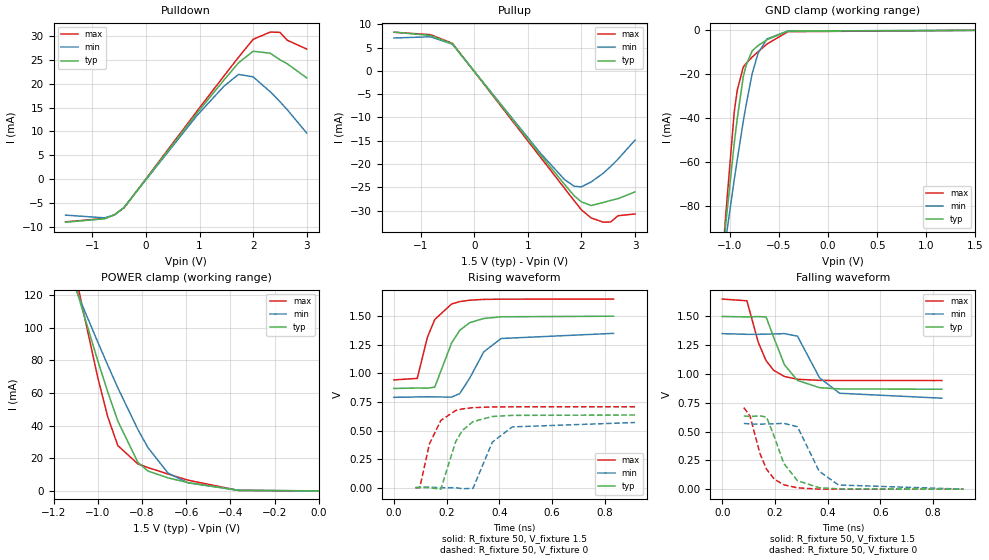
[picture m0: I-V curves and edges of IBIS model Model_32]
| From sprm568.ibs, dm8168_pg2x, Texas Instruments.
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| Model based on original model for BSHTLTCSCDVGPBFZ
|   Sub model FASTEST_6MA_10PER_1P5
[model]   Model_32
|[Description]  [1.5V-3-STATE-X-FASTEST:6MA, IND, 10%]
|   Fastest slew rate (SR[1:0] = "00"), 1.33 * RExt = 0.750 * Iout
|   (I[2:0] = "001"), 6mA nominal with Rext = 50R, ,Industrial
|   temperature range (-40C to 125C, 25C nominal),10% power supply
|   tolerance
|[Input Load]
|[Output Drive] FASTEST:6MA
|Voltage   1.5V
|Mode   3-STATE
Model_type   3-state
Polarity   Non-Inverting
Enable   Active-Low
Cref =  15.0000pF
Rref =  100.0000M
Vref =  0V
Vmeas =  0.75
C_comp   1.5249p   1.4275p   1.6205p
[Model Spec]
[Temperature Range]   25   125   -40
[Voltage Range]   1.5   1.35   1.65
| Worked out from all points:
|   slope of the pulldown table from 0 to 0.225 V, typ, clamps not added: 67.5 ohm
|   slope of the pullup table from 0 to 0.225 V, typ, clamps not added: 67.5 ohm
|   GND clamp passes 1 mA (typ) near -0.47 V on its own axis
|   POWER clamp passes 1 mA (typ) near -0.42 V on its own axis
|   rising waveform, R_fixture 50, V_fixture 1.5: 20-80 % time 68.5ps typ, 87.8ps min, 61.8ps max; typ from 0.868 V to 1.5 V
|   rising waveform, R_fixture 50, V_fixture 0: 20-80 % time 65.3ps typ, 72.3ps min, 59.7ps max; typ from 0 V to 0.636 V
|   falling waveform, R_fixture 50, V_fixture 1.5: 20-80 % time 73.3ps typ, 86.3ps min, 66.2ps max; typ from 1.5 V to 0.867 V
|   falling waveform, R_fixture 50, V_fixture 0: 20-80 % time 69.6ps typ, 78.8ps min, 62.5ps max; typ from 0.636 V to 0 V
[POWER_clamp]
-1.5V     321.6mA    260.6mA    415.8mA
-1.091V   121.1mA    120.8mA    126.6mA
-1.076V   114.1mA    115.8mA    116.8mA
-1V       79.88mA    91.3mA     69.56mA
-954.5mV  60.58mA    77.05mA    45.34mA
-909.1mV  42.84mA    63.2mA     27.8mA
-818.2mV  17.47mA    37.6mA     16.51mA
-772.7mV  12.19mA    26.53mA    14.33mA
-681.8mV  7.985mA    10.89mA    10.33mA
-590.9mV  5.092mA    4.952mA    6.596mA
-363.6mV  298.9uA    465.6uA    298.1uA
0V        1.518nA    23.05nA    396.5pA
[Pulldown]
-1.5V     -9.02mA    -7.54mA    -8.95mA
-772.7mV  -8.299mA   -8.105mA   -8.235mA
-590.9mV  -7.513mA   -7.517mA   -7.478mA
-409.1mV  -5.951mA   -5.915mA   -6.017mA
954.5mV   13.88mA    13.38mA    14.3mA
1.455V    20.79mA    19.48mA    21.63mA
1.727V    24.39mA    21.97mA    25.55mA
2V        26.82mA    21.46mA    29.32mA
2.318V    26.42mA    18.34mA    30.84mA
2.5V      25.05mA    16.26mA    30.79mA
2.636V    24.2mA     14.57mA    29.14mA
3V        21.24mA    9.67mA     27.28mA
[Pullup]
-1.5V     8.32mA     7.05mA     8.28mA
-818.2mV  7.591mA    7.315mA    7.769mA
-409.1mV  5.809mA    5.727mA    5.921mA
1.227V    -17.92mA   -17.56mA   -18.4mA
1.682V    -24.33mA   -23.3mA    -25.16mA
1.864V    -26.79mA   -24.75mA   -27.86mA
2V        -28.11mA   -24.88mA   -29.82mA
2.182V    -28.88mA   -23.81mA   -31.56mA
2.409V    -28.22mA   -21.94mA   -32.46mA
2.545V    -27.79mA   -20.51mA   -32.42mA
2.682V    -27.41mA   -18.93mA   -31.08mA
3V        -25.95mA   -14.85mA   -30.69mA
[GND_clamp]
-1.5V     -310mA     -250.5mA   -402.4mA
-1.076V   -103.5mA   -106.1mA   -105.2mA
-1.045V   -89.74mA   -96.32mA   -85.93mA
-954.5mV  -51.19mA   -67.85mA   -36.85mA
-924.2mV  -40.06mA   -58.84mA   -27.27mA
-863.6mV  -21.23mA   -41.55mA   -16.73mA
-833.3mV  -15.79mA   -33.74mA   -15.03mA
-772.7mV  -9.342mA   -19.74mA   -12.19mA
-712.1mV  -6.927mA   -10.35mA   -9.702mA
-621.2mV  -4.26mA    -3.894mA   -6.224mA
-409.1mV  -336.9uA   -288.9uA   -618.6uA
1.5V      1.518nA    2.298uA    269.6pA
[Ramp]
dV/dt_f   0.50884/0.11619298n   0.452232/0.13701948n   0.565872/0.10424319n
dV/dt_r  0.5232344/0.10555537n   0.474184/0.1177486n  0.5752104/95.752592p
R_load = 50
[Rising Waveform]
R_fixture = 50
V_fixture = 1.5
V_fixture_min = 1.35
V_fixture_max = 1.65
0s        867.9mV    790.4mV    942.9mV
88.61ps   872mV      793.8mV    956.2mV
127ps     870.7mV    795.5mV    1.315V
154.9ps   879.1mV    793.9mV    1.471V
218.9ps   1.266V     792.7mV    1.607V
250.1ps   1.377V     823.6mV    1.628V
287.9ps   1.444V     959.7mV    1.64V
340.9ps   1.48V      1.188V     1.647V
406.8ps   1.495V     1.305V     1.649V
833.3ps   1.5V       1.35V      1.65V
[Rising Waveform]
R_fixture = 50
V_fixture = 0
V_fixture_min = 0
V_fixture_max = 0
81.76ps   0V         0V         0V
98.09ps   3.332mV    2.857mV    0V
134.7ps   0V         4.954mV    383.1mV
178.1ps   -12.83mV   0V         588.6mV
234.5ps   403.6mV    0V         675.4mV
259.8ps   500.3mV    -9.191mV   689.1mV
300ps     577.5mV    -5.574mV   700.2mV
373.4ps   622.8mV    398.5mV    706.2mV
449.3ps   632.7mV    531.9mV    707.5mV
915.1ps   635.6mV    570.2mV    707.9mV
[Falling Waveform]
R_fixture = 50
V_fixture = 1.5
V_fixture_min = 1.35
V_fixture_max = 1.65
0s        1.499V     1.35V      1.65V
93.56ps   1.495V     1.344V     1.635V
136.4ps   1.498V     1.344V     1.276V
166.5ps   1.494V     1.346V     1.115V
194.9ps   1.32V      1.347V     1.032V
236.2ps   1.079V     1.35V      977.8mV
285.4ps   944.1mV    1.328V     953.8mV
369.3ps   880.9mV    966.3mV    944.4mV
445.6ps   870mV      832.5mV    943mV
833.3ps   867.2mV    789.5mV    942.7mV
[Falling Waveform]
R_fixture = 50
V_fixture = 0
V_fixture_min = 0
V_fixture_max = 0
81.76ps   635.6mV    570.4mV    707.9mV
105.2ps   630.7mV    566.5mV    635.3mV
142.9ps   636mV      564mV      310.2mV
168.1ps   625.5mV    566.6mV    173.5mV
197.5ps   455.1mV    567.4mV    86.73mV
233.6ps   223.2mV    571.4mV    37.77mV
285.4ps   73.83mV    542mV      11.67mV
367.7ps   12.79mV    156.1mV    0V
441.2ps   2.867mV    36.24mV    0V
915.1ps   0V         0V         0V
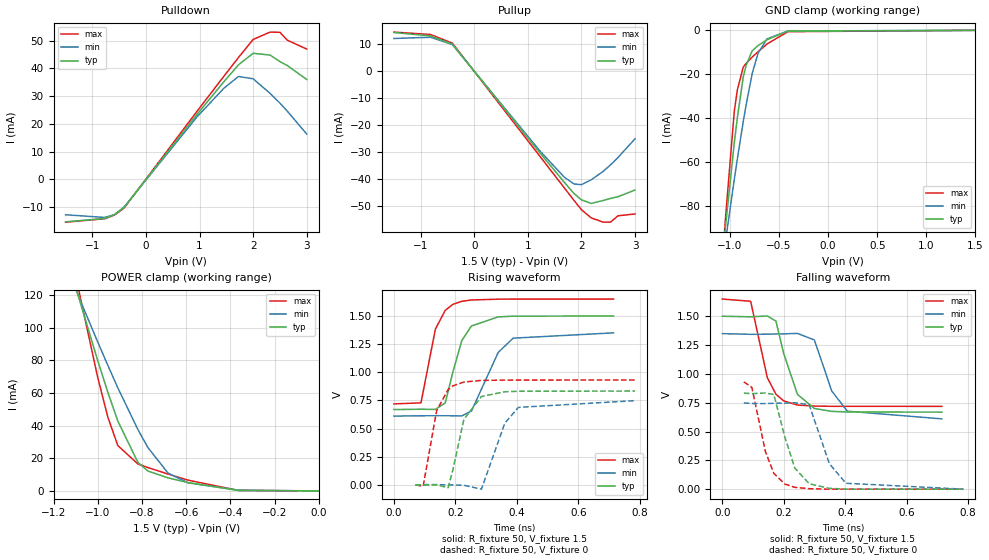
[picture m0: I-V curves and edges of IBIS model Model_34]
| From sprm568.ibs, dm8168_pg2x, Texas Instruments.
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| Model based on original model for BSHTLTCSCDVGPBFZ
|   Sub model FASTEST_10MA_10PER_1P5
[model]   Model_34
|[Description]  [1.5V-3-STATE-X-FASTEST:10MA, IND, 10%]
|   Fastest slew rate (SR[1:0] = "00"), 0.80 * RExt = 1.250 * Iout
|   (I[2:0] = "101"), 10mA nominal with Rext = 50R, ,Industrial
|   temperature range (-40C to 125C, 25C nominal),10% power supply
|   tolerance
|[Input Load]
|[Output Drive] FASTEST:10MA
|Voltage   1.5V
|Mode   3-STATE
Model_type   3-state
Polarity   Non-Inverting
Enable   Active-Low
Cref =  15.0000pF
Rref =  100.0000M
Vref =  0V
Vmeas =  0.75
C_comp   1.5249p   1.4275p   1.6205p
[Model Spec]
[Temperature Range]   25   125   -40
[Voltage Range]   1.5   1.35   1.65
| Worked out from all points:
|   slope of the pulldown table from 0 to 0.225 V, typ, clamps not added: 39.9 ohm
|   slope of the pullup table from 0 to 0.225 V, typ, clamps not added: 39.8 ohm
|   GND clamp passes 1 mA (typ) near -0.47 V on its own axis
|   POWER clamp passes 1 mA (typ) near -0.42 V on its own axis
|   rising waveform, R_fixture 50, V_fixture 1.5: 20-80 % time 50.6ps typ, 71.4ps min, 45.2ps max; typ from 0.669 V to 1.5 V
|   rising waveform, R_fixture 50, V_fixture 0: 20-80 % time 48.3ps typ, 53.3ps min, 43.9ps max; typ from 0 V to 0.833 V
|   falling waveform, R_fixture 50, V_fixture 1.5: 20-80 % time 54.6ps typ, 61.9ps min, 50.8ps max; typ from 1.5 V to 0.669 V
|   falling waveform, R_fixture 50, V_fixture 0: 20-80 % time 53ps typ, 57.1ps min, 49.4ps max; typ from 0.834 V to 0 V
[POWER_clamp]
-1.5V     321.6mA    260.6mA    415.8mA
-1.091V   121.1mA    120.8mA    126.6mA
-1.076V   114.1mA    115.8mA    116.8mA
-1V       79.88mA    91.3mA     69.56mA
-954.5mV  60.58mA    77.05mA    45.34mA
-909.1mV  42.84mA    63.2mA     27.8mA
-818.2mV  17.47mA    37.6mA     16.51mA
-772.7mV  12.19mA    26.53mA    14.33mA
-681.8mV  7.985mA    10.89mA    10.33mA
-590.9mV  5.092mA    4.952mA    6.596mA
-363.6mV  298.9uA    465.6uA    298.1uA
0V        1.518nA    23.05nA    396.5pA
[Pulldown]
-1.5V     -15.29mA   -12.74mA   -15.41mA
-772.7mV  -14.07mA   -13.69mA   -14.18mA
-590.9mV  -12.73mA   -12.7mA    -12.87mA
-409.1mV  -10.08mA   -9.986mA   -10.35mA
954.5mV   23.5mA     22.59mA    24.6mA
1.455V    35.23mA    32.88mA    37.21mA
1.727V    41.32mA    37.11mA    43.96mA
2V        45.47mA    36.28mA    50.45mA
2.318V    44.82mA    31mA       53.11mA
2.5V      42.49mA    27.5mA     53.03mA
2.636V    41.06mA    24.65mA    50.21mA
3V        36.04mA    16.36mA    46.99mA
[Pullup]
-1.5V     14.1mA     11.91mA    14.27mA
-818.2mV  12.87mA    12.36mA    13.38mA
-409.1mV  9.843mA    9.671mA    10.19mA
1.227V    -30.35mA   -29.65mA   -31.65mA
1.682V    -41.22mA   -39.34mA   -43.29mA
1.864V    -45.39mA   -41.81mA   -47.93mA
2V        -47.64mA   -42.04mA   -51.31mA
2.182V    -48.97mA   -40.26mA   -54.32mA
2.409V    -47.87mA   -37.09mA   -55.9mA
2.545V    -47.12mA   -34.69mA   -55.85mA
2.682V    -46.49mA   -32.02mA   -53.53mA
3V        -44.02mA   -25.11mA   -52.86mA
[GND_clamp]
-1.5V     -310mA     -250.5mA   -402.4mA
-1.076V   -103.5mA   -106.1mA   -105.2mA
-1.045V   -89.74mA   -96.32mA   -85.93mA
-954.5mV  -51.19mA   -67.85mA   -36.85mA
-924.2mV  -40.06mA   -58.84mA   -27.27mA
-863.6mV  -21.23mA   -41.55mA   -16.73mA
-833.3mV  -15.79mA   -33.74mA   -15.03mA
-772.7mV  -9.342mA   -19.74mA   -12.19mA
-712.1mV  -6.927mA   -10.35mA   -9.702mA
-621.2mV  -4.26mA    -3.894mA   -6.224mA
-409.1mV  -336.9uA   -288.9uA   -618.6uA
1.5V      1.518nA    2.298uA    269.6pA
[Ramp]
dV/dt_f   0.669816/86.99153p   0.596264/0.10044363n   0.74756/79.093037p
dV/dt_r   0.691208/78.486763p  0.6287512/87.727857p  0.7619776/70.723037p
R_load = 50
[Rising Waveform]
R_fixture = 50
V_fixture = 1.5
V_fixture_min = 1.35
V_fixture_max = 1.65
0s        669.2mV    611mV      719.5mV
88.05ps   672mV      614mV      728.7mV
134.9ps   670.4mV    614.3mV    1.383V
167ps     727.9mV    614.2mV    1.55V
191.9ps   1.002V     614mV      1.603V
220.9ps   1.282V     612.4mV    1.63V
252.2ps   1.411V     655.8mV    1.642V
339.3ps   1.492V     1.176V     1.649V
387.9ps   1.498V     1.303V     1.65V
714.3ps   1.5V       1.35V      1.65V
[Rising Waveform]
R_fixture = 50
V_fixture = 0
V_fixture_min = 0
V_fixture_max = 0
70.19ps   0V         0V         0V
95.12ps   2.126mV    2.536mV    -11.77mV
139ps     0V         2.818mV    659.7mV
176.2ps   -24.27mV   0V         846.4mV
191.6ps   131.5mV    0V         879mV
227.6ps   582mV      -2.744mV   913.7mV
284.8ps   785mV      -37.52mV   927.7mV
360.7ps   827.1mV    548.2mV    930.6mV
405.2ps   831.4mV    688.5mV    930.9mV
784.5ps   833.5mV    748.2mV    931.2mV
[Falling Waveform]
R_fixture = 50
V_fixture = 1.5
V_fixture_min = 1.35
V_fixture_max = 1.65
0s        1.501V     1.35V      1.65V
92.4ps    1.496V     1.344V     1.631V
146.7ps   1.503V     1.345V     967.3mV
174.6ps   1.459V     1.347V     824.7mV
199.7ps   1.18V      1.348V     766.4mV
244.6ps   823mV      1.352V     730.3mV
299.7ps   700.3mV    1.295V     721.1mV
356.3ps   675.3mV    852mV      719.2mV
406.8ps   670.1mV    676.9mV    718.8mV
714.3ps   668.5mV    610.2mV    718.6mV
[Falling Waveform]
R_fixture = 50
V_fixture = 0
V_fixture_min = 0
V_fixture_max = 0
70.19ps   833.7mV    748.4mV    931.1mV
96.31ps   829.1mV    743.2mV    883.6mV
140.2ps   834.4mV    742.7mV    328.6mV
167.7ps   822.2mV    745.5mV    137.7mV
203.4ps   454.1mV    746.5mV    44.18mV
236.2ps   182.4mV    750.2mV    15.95mV
282.8ps   46.97mV    733mV      4.069mV
348.5ps   7.416mV    221.3mV    0V
402.1ps   0V         51.3mV     0V
784.5ps   0V         0V         0V
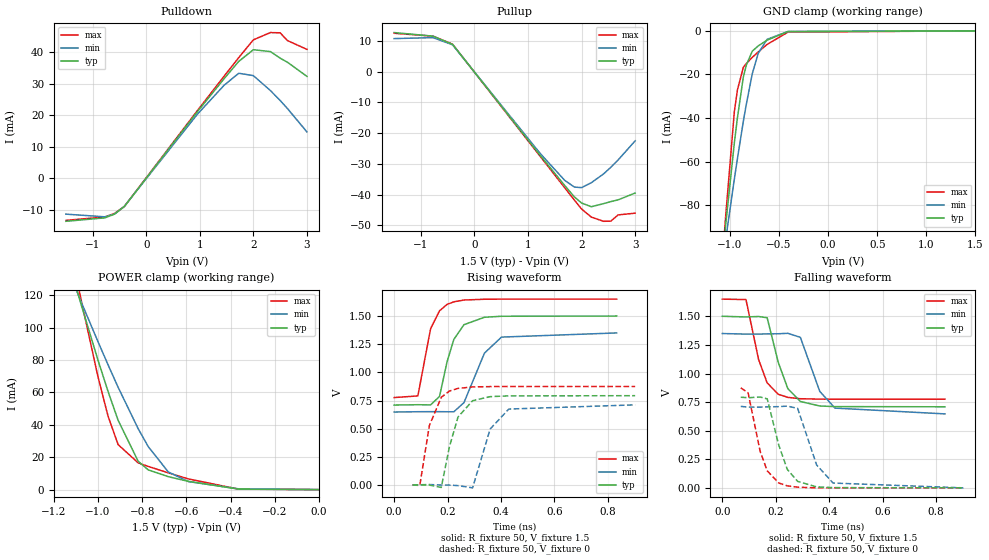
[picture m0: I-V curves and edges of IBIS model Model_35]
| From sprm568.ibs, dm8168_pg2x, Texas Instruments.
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| Model based on original model for BSHTLTCSCDVGPBFZ
|   Sub model FASTEST_9MA_10PER_1P5
[model]   Model_35
|[Description]  [1.5V-3-STATE-X-FASTEST:9MA, IND, 10%]
|   Fastest slew rate (SR[1:0] = "00"), 0.88 * RExt = 1.125 * Iout
|   (I[2:0] = "100"), 9mA nominal with Rext = 50R, ,Industrial
|   temperature range (-40C to 125C, 25C nominal),10% power supply
|   tolerance
|[Input Load]
|[Output Drive] FASTEST:9MA
|Voltage   1.5V
|Mode   3-STATE
Model_type   3-state
Polarity   Non-Inverting
Enable   Active-Low
Cref =  15.0000pF
Rref =  100.0000M
Vref =  0V
Vmeas =  0.75
C_comp   1.5249p   1.4275p   1.6205p
[Model Spec]
[Temperature Range]   25   125   -40
[Voltage Range]   1.5   1.35   1.65
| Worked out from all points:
|   slope of the pulldown table from 0 to 0.225 V, typ, clamps not added: 44.4 ohm
|   slope of the pullup table from 0 to 0.225 V, typ, clamps not added: 44.4 ohm
|   GND clamp passes 1 mA (typ) near -0.47 V on its own axis
|   POWER clamp passes 1 mA (typ) near -0.42 V on its own axis
|   rising waveform, R_fixture 50, V_fixture 1.5: 20-80 % time 54.4ps typ, 74.6ps min, 49.4ps max; typ from 0.71 V to 1.5 V
|   rising waveform, R_fixture 50, V_fixture 0: 20-80 % time 51.8ps typ, 57ps min, 47.6ps max; typ from 0 V to 0.793 V
|   falling waveform, R_fixture 50, V_fixture 1.5: 20-80 % time 59ps typ, 67.1ps min, 54.6ps max; typ from 1.5 V to 0.709 V
|   falling waveform, R_fixture 50, V_fixture 0: 20-80 % time 57.2ps typ, 61.9ps min, 52.5ps max; typ from 0.793 V to 0 V
[POWER_clamp]
-1.5V     321.6mA    260.6mA    415.8mA
-1.091V   121.1mA    120.8mA    126.6mA
-1.076V   114.1mA    115.8mA    116.8mA
-1V       79.88mA    91.3mA     69.56mA
-954.5mV  60.58mA    77.05mA    45.34mA
-909.1mV  42.84mA    63.2mA     27.8mA
-818.2mV  17.47mA    37.6mA     16.51mA
-772.7mV  12.19mA    26.53mA    14.33mA
-681.8mV  7.985mA    10.89mA    10.33mA
-590.9mV  5.092mA    4.952mA    6.596mA
-363.6mV  298.9uA    465.6uA    298.1uA
0V        1.518nA    23.05nA    396.5pA
[Pulldown]
-1.5V     -13.72mA   -11.44mA   -13.42mA
-772.7mV  -12.63mA   -12.3mA    -12.35mA
-590.9mV  -11.43mA   -11.4mA    -11.21mA
-409.1mV  -9.05mA    -8.969mA   -9.02mA
954.5mV   21.1mA     20.29mA    21.44mA
1.455V    31.62mA    29.53mA    32.42mA
1.727V    37.09mA    33.33mA    38.3mA
2V        40.81mA    32.58mA    43.95mA
2.318V    40.22mA    27.84mA    46.26mA
2.5V      38.13mA    24.69mA    46.18mA
2.636V    36.84mA    22.13mA    43.72mA
3V        32.34mA    14.69mA    40.92mA
[Pullup]
-1.5V     12.66mA    10.7mA     12.43mA
-772.7mV  11.49mA    11.01mA    11.49mA
-409.1mV  8.835mA    8.685mA    8.877mA
1.227V    -27.25mA   -26.63mA   -27.57mA
1.682V    -37mA      -35.33mA   -37.72mA
1.864V    -40.74mA   -37.55mA   -41.76mA
2V        -42.75mA   -37.75mA   -44.71mA
2.182V    -43.95mA   -36.14mA   -47.32mA
2.409V    -42.96mA   -33.3mA    -48.69mA
2.545V    -42.29mA   -31.14mA   -48.64mA
2.682V    -41.72mA   -28.75mA   -46.62mA
3V        -39.5mA    -22.54mA   -46.04mA
[GND_clamp]
-1.5V     -310mA     -250.5mA   -402.4mA
-1.076V   -103.5mA   -106.1mA   -105.2mA
-1.045V   -89.74mA   -96.32mA   -85.93mA
-954.5mV  -51.19mA   -67.85mA   -36.85mA
-924.2mV  -40.06mA   -58.84mA   -27.27mA
-863.6mV  -21.23mA   -41.55mA   -16.73mA
-833.3mV  -15.79mA   -33.74mA   -15.03mA
-772.7mV  -9.342mA   -19.74mA   -12.19mA
-712.1mV  -6.927mA   -10.35mA   -9.702mA
-621.2mV  -4.26mA    -3.894mA   -6.224mA
-409.1mV  -336.9uA   -288.9uA   -618.6uA
1.5V      1.518nA    2.298uA    269.6pA
[Ramp]
dV/dt_f   0.636864/93.541059p   0.566864/0.10807122n   0.701424/85.122008p
dV/dt_r  0.6566816/84.30946p   0.596696/93.996933p  0.7143248/77.192684p
R_load = 50
[Rising Waveform]
R_fixture = 50
V_fixture = 1.5
V_fixture_min = 1.35
V_fixture_max = 1.65
0s        709.9mV    647.9mV    776.3mV
88.89ps   712.9mV    650.7mV    791mV
136.6ps   711.4mV    651.2mV    1.388V
170ps     786.3mV    651.2mV    1.546V
198.1ps   1.093V     650.5mV    1.603V
223.5ps   1.292V     650.1mV    1.626V
261.4ps   1.423V     731.2mV    1.642V
338.2ps   1.489V     1.171V     1.649V
402ps     1.498V     1.313V     1.65V
833.3ps   1.5V       1.35V      1.65V
[Rising Waveform]
R_fixture = 50
V_fixture = 0
V_fixture_min = 0
V_fixture_max = 0
68.98ps   0V         0V         0V
96.21ps   2.319mV    2.557mV    -3.294mV
131.9ps   0V         4.385mV    527.2mV
176.5ps   -21.36mV   0V         778.4mV
207.1ps   339.8mV    0V         834.5mV
239.1ps   603.5mV    -5.16mV    857.7mV
293.8ps   748.5mV    -25.02mV   870.6mV
359.5ps   784.6mV    497.1mV    873.7mV
429.4ps   791.3mV    674.4mV    874.4mV
902.3ps   793mV      711.7mV    874.6mV
[Falling Waveform]
R_fixture = 50
V_fixture = 1.5
V_fixture_min = 1.35
V_fixture_max = 1.65
0s        1.501V     1.35V      1.651V
88.45ps   1.495V     1.345V     1.647V
135.8ps   1.499V     1.345V     1.122V
167.7ps   1.488V     1.347V     918.6mV
209.4ps   1.097V     1.348V     818.5mV
245.2ps   868.1mV    1.352V     791.5mV
292ps     755.8mV    1.317V     779.7mV
364.7ps   716.2mV    843.7mV    776.1mV
421.8ps   710.8mV    697.6mV    775.6mV
833.3ps   709.2mV    647mV      775.3mV
[Falling Waveform]
R_fixture = 50
V_fixture = 0
V_fixture_min = 0
V_fixture_max = 0
68.98ps   792.9mV    712.6mV    874.8mV
96.46ps   788.4mV    706.7mV    830.7mV
141.6ps   794.4mV    706.1mV    319.4mV
168.1ps   778.4mV    708.9mV    148.7mV
210.7ps   377.9mV    710.3mV    42.91mV
243.1ps   161.5mV    715.2mV    17.59mV
281.9ps   56.54mV    695.7mV    6.065mV
352.8ps   8.481mV    200.5mV    0V
414.5ps   2.13mV     42.03mV    0V
902.3ps   0V         0V         0V
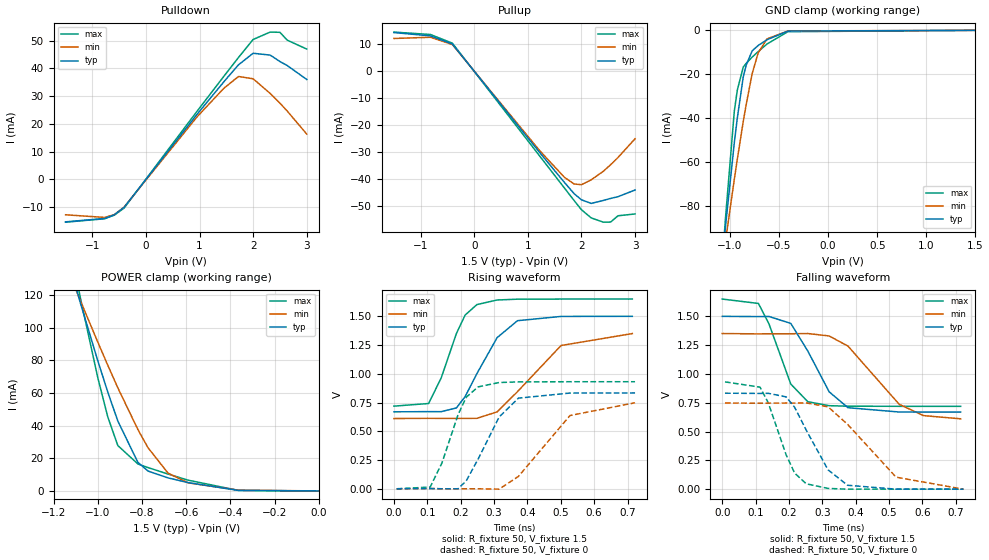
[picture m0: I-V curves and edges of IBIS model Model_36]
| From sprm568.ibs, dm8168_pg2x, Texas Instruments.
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| Model based on original model for BSHTLTCSCDVGPBFZ
|   Sub model FAST_10MA_10PER_1P5
[model]   Model_36
|[Description]  [1.5V-3-STATE-X-FAST:10MA, IND, 10%]
|   Fast slew rate (SR[1:0] = "10"), 0.80 * RExt = 1.250 * Iout
|   (I[2:0] = "101"), 10mA nominal with Rext = 50R, ,Industrial
|   temperature range (-40C to 125C, 25C nominal),10% power supply
|   tolerance
|[Input Load]
|[Output Drive] FAST:10MA
|Voltage   1.5V
|Mode   3-STATE
Model_type   3-state
Polarity   Non-Inverting
Enable   Active-Low
Cref =  15.0000pF
Rref =  100.0000M
Vref =  0V
Vmeas =  0.75
C_comp   1.5249p   1.4275p   1.6205p
[Model Spec]
[Temperature Range]   25   125   -40
[Voltage Range]   1.5   1.35   1.65
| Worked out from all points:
|   slope of the pulldown table from 0 to 0.225 V, typ, clamps not added: 39.9 ohm
|   slope of the pullup table from 0 to 0.225 V, typ, clamps not added: 39.8 ohm
|   GND clamp passes 1 mA (typ) near -0.47 V on its own axis
|   POWER clamp passes 1 mA (typ) near -0.42 V on its own axis
|   rising waveform, R_fixture 50, V_fixture 1.5: 20-80 % time 94.3ps typ, 134ps min, 70.6ps max; typ from 0.669 V to 1.5 V
|   rising waveform, R_fixture 50, V_fixture 0: 20-80 % time 88.9ps typ, 125ps min, 68.1ps max; typ from 0 V to 0.833 V
|   falling waveform, R_fixture 50, V_fixture 1.5: 20-80 % time 90.7ps typ, 130ps min, 71.1ps max; typ from 1.5 V to 0.669 V
|   falling waveform, R_fixture 50, V_fixture 0: 20-80 % time 92ps typ, 133ps min, 69.2ps max; typ from 0.833 V to 0 V
[POWER_clamp]
-1.5V     321.6mA    260.6mA    415.8mA
-1.091V   121.1mA    120.8mA    126.6mA
-1.076V   114.1mA    115.8mA    116.8mA
-1V       79.88mA    91.3mA     69.56mA
-954.5mV  60.58mA    77.05mA    45.34mA
-909.1mV  42.84mA    63.2mA     27.8mA
-818.2mV  17.47mA    37.6mA     16.51mA
-772.7mV  12.19mA    26.53mA    14.33mA
-681.8mV  7.985mA    10.89mA    10.33mA
-590.9mV  5.092mA    4.952mA    6.596mA
-363.6mV  298.9uA    465.6uA    298.1uA
0V        1.518nA    23.05nA    396.5pA
[Pulldown]
-1.5V     -15.29mA   -12.74mA   -15.41mA
-772.7mV  -14.07mA   -13.69mA   -14.18mA
-590.9mV  -12.73mA   -12.7mA    -12.87mA
-409.1mV  -10.08mA   -9.986mA   -10.35mA
954.5mV   23.5mA     22.59mA    24.6mA
1.455V    35.23mA    32.88mA    37.21mA
1.727V    41.32mA    37.11mA    43.96mA
2V        45.47mA    36.28mA    50.45mA
2.318V    44.82mA    31mA       53.11mA
2.5V      42.49mA    27.5mA     53.03mA
2.636V    41.06mA    24.65mA    50.21mA
3V        36.04mA    16.36mA    46.99mA
[Pullup]
-1.5V     14.1mA     11.91mA    14.27mA
-818.2mV  12.87mA    12.36mA    13.38mA
-409.1mV  9.843mA    9.671mA    10.19mA
1.227V    -30.35mA   -29.65mA   -31.65mA
1.682V    -41.22mA   -39.34mA   -43.29mA
1.864V    -45.39mA   -41.81mA   -47.93mA
2V        -47.64mA   -42.04mA   -51.31mA
2.182V    -48.97mA   -40.26mA   -54.32mA
2.409V    -47.87mA   -37.09mA   -55.9mA
2.545V    -47.12mA   -34.69mA   -55.85mA
2.682V    -46.49mA   -32.02mA   -53.53mA
3V        -44.02mA   -25.11mA   -52.86mA
[GND_clamp]
-1.5V     -310mA     -250.5mA   -402.4mA
-1.076V   -103.5mA   -106.1mA   -105.2mA
-1.045V   -89.74mA   -96.32mA   -85.93mA
-954.5mV  -51.19mA   -67.85mA   -36.85mA
-924.2mV  -40.06mA   -58.84mA   -27.27mA
-863.6mV  -21.23mA   -41.55mA   -16.73mA
-833.3mV  -15.79mA   -33.74mA   -15.03mA
-772.7mV  -9.342mA   -19.74mA   -12.19mA
-712.1mV  -6.927mA   -10.35mA   -9.702mA
-621.2mV  -4.26mA    -3.894mA   -6.224mA
-409.1mV  -336.9uA   -288.9uA   -618.6uA
1.5V      1.518nA    2.298uA    269.6pA
[Ramp]
dV/dt_f   0.665336/0.13627215n   0.592256/0.20022916n   0.74524/0.10888073n
dV/dt_r 0.67165152/0.1316502n 0.60468336/0.19377842n 0.74752248/0.1039235n
R_load = 50
[Rising Waveform]
R_fixture = 50
V_fixture = 1.5
V_fixture_min = 1.35
V_fixture_max = 1.65
0s        669.2mV    611mV      718.8mV
104ps     671.1mV    612.9mV    741.6mV
141.7ps   670.6mV    612.1mV    964.5mV
187.3ps   703.3mV    612.1mV    1.351V
213.4ps   802mV      612mV      1.511V
248.7ps   1.002V     612.8mV    1.602V
309.3ps   1.315V     668.9mV    1.642V
370.4ps   1.462V     845.2mV    1.649V
500.8ps   1.499V     1.246V     1.65V
714.3ps   1.5V       1.35V      1.65V
[Rising Waveform]
R_fixture = 50
V_fixture = 0
V_fixture_min = 0
V_fixture_max = 0
8.21ps    0V         0V         0V
108.6ps   2.372mV    2.355mV    14.99mV
144ps     0V         0V         225.2mV
192.1ps   0V         0V         644mV
216.8ps   69.18mV    0V         796.7mV
252.3ps   258.6mV    0V         886.2mV
315ps     623.1mV    -3.309mV   924.1mV
373.1ps   788.4mV    107.5mV    929.6mV
527.5ps   832.6mV    637mV      931.1mV
722.5ps   833.5mV    748.2mV    931.2mV
[Falling Waveform]
R_fixture = 50
V_fixture = 1.5
V_fixture_min = 1.35
V_fixture_max = 1.65
0s        1.499V     1.35V      1.649V
108.4ps   1.497V     1.347V     1.611V
140.1ps   1.498V     1.348V     1.433V
205.3ps   1.438V     1.348V     911.9mV
256.4ps   1.198V     1.35V      758.5mV
320.3ps   844.5mV    1.329V     724.1mV
376.7ps   706.6mV    1.241V     719.7mV
530.1ps   669.2mV    736.3mV    718.7mV
602.8ps   668.7mV    638.1mV    718.6mV
714.3ps   668.5mV    610.2mV    718.6mV
[Falling Waveform]
R_fixture = 50
V_fixture = 0
V_fixture_min = 0
V_fixture_max = 0
8.21ps    832.6mV    747.6mV    930.6mV
113.2ps   830.4mV    745.2mV    884.9mV
137.9ps   831.5mV    746.2mV    748.7mV
191.6ps   800.2mV    747mV      296.2mV
217ps     709.6mV    746.4mV    138.8mV
251.8ps   510.8mV    748.2mV    46.36mV
317.2ps   167mV      713.8mV    6.516mV
375.5ps   33.88mV    562.3mV    0V
520.8ps   0V         104mV      0V
722.5ps   0V         0V         0V
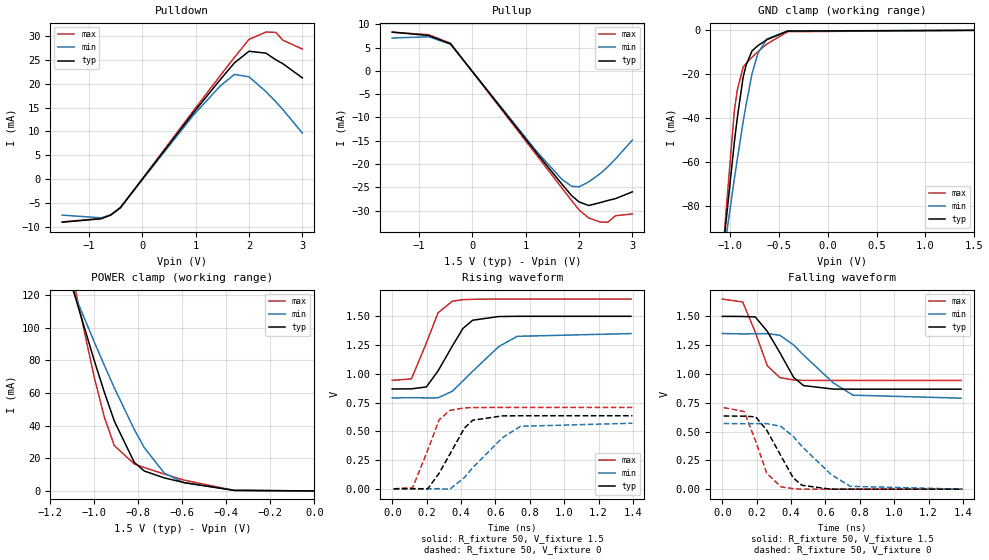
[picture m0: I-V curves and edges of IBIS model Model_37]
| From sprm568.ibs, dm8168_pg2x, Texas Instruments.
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| Model based on original model for BSHTLTCSCDVGPBFZ
|   Sub model SLOWEST_6MA_10PER_1P5
[model]   Model_37
|[Description]  [1.5V-3-STATE-X-SLOWEST:6MA, IND, 10%]
|   Slowest slew rate (SR[1:0] = "11"), 1.33 * RExt = 0.750 * Iout
|   (I[2:0] = "001"), 6mA nominal with Rext = 50R, ,Industrial
|   temperature range (-40C to 125C, 25C nominal),10% power supply
|   tolerance
|[Input Load]
|[Output Drive] SLOWEST:6MA
|Voltage   1.5V
|Mode   3-STATE
Model_type   3-state
Polarity   Non-Inverting
Enable   Active-Low
Cref =  15.0000pF
Rref =  100.0000M
Vref =  0V
Vmeas =  0.75
C_comp   1.5249p   1.4275p   1.6205p
[Model Spec]
[Temperature Range]   25   125   -40
[Voltage Range]   1.5   1.35   1.65
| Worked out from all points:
|   slope of the pulldown table from 0 to 0.225 V, typ, clamps not added: 67.5 ohm
|   slope of the pullup table from 0 to 0.225 V, typ, clamps not added: 67.5 ohm
|   GND clamp passes 1 mA (typ) near -0.47 V on its own axis
|   POWER clamp passes 1 mA (typ) near -0.42 V on its own axis
|   rising waveform, R_fixture 50, V_fixture 1.5: 20-80 % time 147ps typ, 233ps min, 104ps max; typ from 0.868 V to 1.5 V
|   rising waveform, R_fixture 50, V_fixture 0: 20-80 % time 142ps typ, 221ps min, 101ps max; typ from 0 V to 0.636 V
|   falling waveform, R_fixture 50, V_fixture 1.5: 20-80 % time 144ps typ, 241ps min, 100ps max; typ from 1.5 V to 0.867 V
|   falling waveform, R_fixture 50, V_fixture 0: 20-80 % time 140ps typ, 231ps min, 96.9ps max; typ from 0.635 V to 0 V
[POWER_clamp]
-1.5V     321.6mA    260.6mA    415.8mA
-1.091V   121.1mA    120.8mA    126.6mA
-1.076V   114.1mA    115.8mA    116.8mA
-1V       79.88mA    91.3mA     69.56mA
-954.5mV  60.58mA    77.05mA    45.34mA
-909.1mV  42.84mA    63.2mA     27.8mA
-818.2mV  17.47mA    37.6mA     16.51mA
-772.7mV  12.19mA    26.53mA    14.33mA
-681.8mV  7.985mA    10.89mA    10.33mA
-590.9mV  5.092mA    4.952mA    6.596mA
-363.6mV  298.9uA    465.6uA    298.1uA
0V        1.518nA    23.05nA    396.5pA
[Pulldown]
-1.5V     -9.02mA    -7.54mA    -8.95mA
-772.7mV  -8.299mA   -8.105mA   -8.235mA
-590.9mV  -7.513mA   -7.517mA   -7.478mA
-409.1mV  -5.951mA   -5.915mA   -6.017mA
954.5mV   13.88mA    13.38mA    14.3mA
1.455V    20.79mA    19.48mA    21.63mA
1.727V    24.39mA    21.97mA    25.55mA
2V        26.82mA    21.46mA    29.32mA
2.318V    26.42mA    18.34mA    30.84mA
2.5V      25.05mA    16.26mA    30.79mA
2.636V    24.2mA     14.57mA    29.14mA
3V        21.24mA    9.67mA     27.28mA
[Pullup]
-1.5V     8.32mA     7.05mA     8.28mA
-818.2mV  7.591mA    7.315mA    7.769mA
-409.1mV  5.809mA    5.727mA    5.921mA
1.227V    -17.92mA   -17.56mA   -18.4mA
1.682V    -24.33mA   -23.3mA    -25.16mA
1.864V    -26.79mA   -24.75mA   -27.86mA
2V        -28.11mA   -24.88mA   -29.82mA
2.182V    -28.88mA   -23.81mA   -31.56mA
2.409V    -28.22mA   -21.94mA   -32.46mA
2.545V    -27.79mA   -20.51mA   -32.42mA
2.682V    -27.41mA   -18.93mA   -31.08mA
3V        -25.95mA   -14.85mA   -30.69mA
[GND_clamp]
-1.5V     -310mA     -250.5mA   -402.4mA
-1.076V   -103.5mA   -106.1mA   -105.2mA
-1.045V   -89.74mA   -96.32mA   -85.93mA
-954.5mV  -51.19mA   -67.85mA   -36.85mA
-924.2mV  -40.06mA   -58.84mA   -27.27mA
-863.6mV  -21.23mA   -41.55mA   -16.73mA
-833.3mV  -15.79mA   -33.74mA   -15.03mA
-772.7mV  -9.342mA   -19.74mA   -12.19mA
-712.1mV  -6.927mA   -10.35mA   -9.702mA
-621.2mV  -4.26mA    -3.894mA   -6.224mA
-409.1mV  -336.9uA   -288.9uA   -618.6uA
1.5V      1.518nA    2.298uA    269.6pA
[Ramp]
dV/dt_f   0.506288/0.20734459n   0.448944/0.34634145n   0.565952/0.15085287n
dV/dt_r 0.51057768/0.20460921n 0.45951736/0.32492707n  0.5665081/0.14902098n
R_load = 50
[Rising Waveform]
R_fixture = 50
V_fixture = 1.5
V_fixture_min = 1.35
V_fixture_max = 1.65
0s        867.9mV    790.4mV    943mV
111.1ps   869.3mV    792.3mV    955.6mV
198.2ps   885.8mV    790.8mV    1.267V
266.2ps   1.025V     791.3mV    1.531V
349.2ps   1.241V     848.1mV    1.631V
410.8ps   1.394V     937.3mV    1.645V
467.7ps   1.466V     1.022V     1.648V
618.1ps   1.498V     1.235V     1.65V
726.3ps   1.5V       1.326V     1.65V
1.389ns   1.5V       1.35V      1.65V
[Rising Waveform]
R_fixture = 50
V_fixture = 0
V_fixture_min = 0
V_fixture_max = 0
8.2ps     0V         0V         0V
118.8ps   0V         2.265mV    10.53mV
206.3ps   0V         0V         337mV
273ps     136.5mV    0V         600.7mV
335ps     300.8mV    -3.13mV    681.8mV
419.7ps   527.9mV    97.73mV    703.7mV
468ps     596.4mV    184.3mV    706.4mV
641.4ps   634.3mV    444.6mV    707.8mV
746ps     635.3mV    543.8mV    707.9mV
1.397ns   635.6mV    570.2mV    707.9mV
[Falling Waveform]
R_fixture = 50
V_fixture = 1.5
V_fixture_min = 1.35
V_fixture_max = 1.65
0s        1.499V     1.35V      1.649V
118.5ps   1.498V     1.347V     1.624V
191.8ps   1.494V     1.348V     1.363V
262ps     1.369V     1.349V     1.07V
335.5ps   1.183V     1.335V     967mV
415.5ps   968.6mV    1.25V      946.7mV
473.1ps   898.4mV    1.163V     943.8mV
646.6ps   868mV      921.1mV    942.8mV
760.9ps   867.3mV    815.3mV    942.7mV
1.389ns   867.2mV    789.5mV    942.7mV
[Falling Waveform]
R_fixture = 50
V_fixture = 0
V_fixture_min = 0
V_fixture_max = 0
8.2ps     634.7mV    569.3mV    707.3mV
127.6ps   633.2mV    567.7mV    673.5mV
194.2ps   627.4mV    568.6mV    416.5mV
258.5ps   511.9mV    568.8mV    139.2mV
341.3ps   288.8mV    544.1mV    20.55mV
412.4ps   98.97mV    457.8mV    4.32mV
463.6ps   33.57mV    371.3mV    0V
630.3ps   0V         131mV      0V
744ps     0V         24.81mV    0V
1.397ns   0V         0V         0V
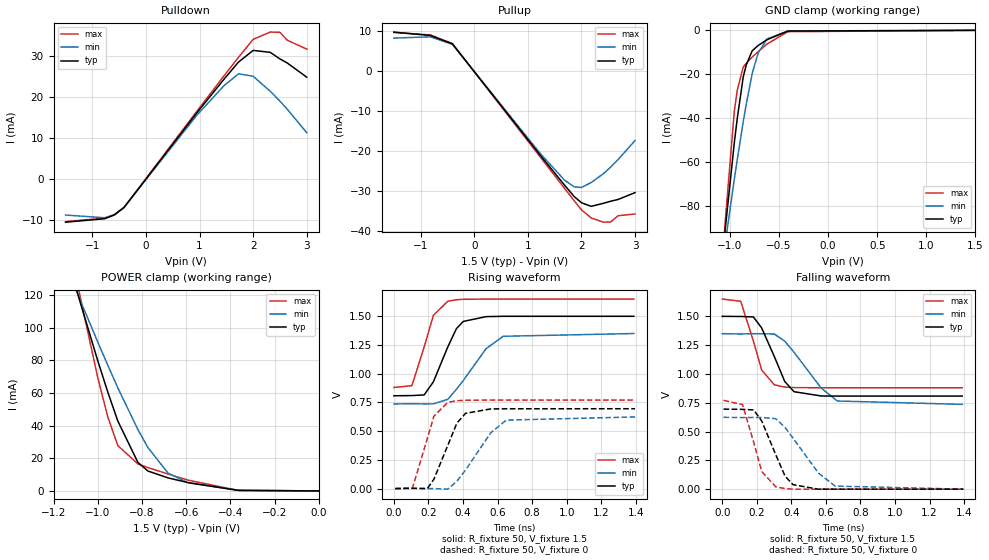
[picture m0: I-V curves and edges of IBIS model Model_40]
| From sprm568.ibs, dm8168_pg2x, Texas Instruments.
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| Model based on original model for BSHTLTCSCDVGPBFZ
|   Sub model SLOW_7MA_10PER_1P5
[model]   Model_40
|[Description]  [1.5V-3-STATE-X-SLOW:7MA, IND, 10%]
|   Slow slew rate (SR[1:0] = "01"), 1.14 * RExt = 0.875 * Iout
|   (I[2:0] = "010"), 7mA nominal with Rext = 50R, ,Industrial
|   temperature range (-40C to 125C, 25C nominal),10% power supply
|   tolerance
|[Input Load]
|[Output Drive] SLOW:7MA
|Voltage   1.5V
|Mode   3-STATE
Model_type   3-state
Polarity   Non-Inverting
Enable   Active-Low
Cref =  15.0000pF
Rref =  100.0000M
Vref =  0V
Vmeas =  0.75
C_comp   1.5249p   1.4275p   1.6205p
[Model Spec]
[Temperature Range]   25   125   -40
[Voltage Range]   1.5   1.35   1.65
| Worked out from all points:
|   slope of the pulldown table from 0 to 0.225 V, typ, clamps not added: 57.5 ohm
|   slope of the pullup table from 0 to 0.225 V, typ, clamps not added: 57.5 ohm
|   GND clamp passes 1 mA (typ) near -0.47 V on its own axis
|   POWER clamp passes 1 mA (typ) near -0.42 V on its own axis
|   rising waveform, R_fixture 50, V_fixture 1.5: 20-80 % time 117ps typ, 180ps min, 86.9ps max; typ from 0.808 V to 1.5 V
|   rising waveform, R_fixture 50, V_fixture 0: 20-80 % time 112ps typ, 168ps min, 83.5ps max; typ from 0 V to 0.695 V
|   falling waveform, R_fixture 50, V_fixture 1.5: 20-80 % time 117ps typ, 189ps min, 85.9ps max; typ from 1.5 V to 0.807 V
|   falling waveform, R_fixture 50, V_fixture 0: 20-80 % time 114ps typ, 183ps min, 83.2ps max; typ from 0.695 V to 0 V
[POWER_clamp]
-1.5V     321.6mA    260.6mA    415.8mA
-1.091V   121.1mA    120.8mA    126.6mA
-1.076V   114.1mA    115.8mA    116.8mA
-1V       79.88mA    91.3mA     69.56mA
-954.5mV  60.58mA    77.05mA    45.34mA
-909.1mV  42.84mA    63.2mA     27.8mA
-818.2mV  17.47mA    37.6mA     16.51mA
-772.7mV  12.19mA    26.53mA    14.33mA
-681.8mV  7.985mA    10.89mA    10.33mA
-590.9mV  5.092mA    4.952mA    6.596mA
-363.6mV  298.9uA    465.6uA    298.1uA
0V        1.518nA    23.05nA    396.5pA
[Pulldown]
-1.5V     -10.59mA   -8.84mA    -10.44mA
-772.7mV  -9.742mA   -9.502mA   -9.607mA
-590.9mV  -8.819mA   -8.812mA   -8.723mA
-409.1mV  -6.984mA   -6.933mA   -7.018mA
954.5mV   16.28mA    15.69mA    16.68mA
1.455V    24.41mA    22.83mA    25.23mA
1.727V    28.63mA    25.76mA    29.8mA
2V        31.49mA    25.17mA    34.2mA
2.318V    31.02mA    21.5mA     35.98mA
2.5V      29.41mA    19.07mA    35.92mA
2.636V    28.42mA    17.09mA    34mA
3V        24.94mA    11.34mA    31.82mA
[Pullup]
-1.5V     9.77mA     8.27mA     9.66mA
-818.2mV  8.911mA    8.576mA    9.063mA
-409.1mV  6.818mA    6.713mA    6.907mA
1.227V    -21.03mA   -20.59mA   -21.46mA
1.682V    -28.55mA   -27.31mA   -29.35mA
1.864V    -31.44mA   -29.02mA   -32.49mA
2V        -32.99mA   -29.17mA   -34.79mA
2.182V    -33.9mA    -27.92mA   -36.81mA
2.409V    -33.14mA   -25.72mA   -37.87mA
2.545V    -32.62mA   -24.06mA   -37.83mA
2.682V    -32.18mA   -22.2mA    -36.26mA
3V        -30.46mA   -17.41mA   -35.81mA
[GND_clamp]
-1.5V     -310mA     -250.5mA   -402.4mA
-1.076V   -103.5mA   -106.1mA   -105.2mA
-1.045V   -89.74mA   -96.32mA   -85.93mA
-954.5mV  -51.19mA   -67.85mA   -36.85mA
-924.2mV  -40.06mA   -58.84mA   -27.27mA
-863.6mV  -21.23mA   -41.55mA   -16.73mA
-833.3mV  -15.79mA   -33.74mA   -15.03mA
-772.7mV  -9.342mA   -19.74mA   -12.19mA
-712.1mV  -6.927mA   -10.35mA   -9.702mA
-621.2mV  -4.26mA    -3.894mA   -6.224mA
-409.1mV  -336.9uA   -288.9uA   -618.6uA
1.5V      1.518nA    2.298uA    269.6pA
[Ramp]
dV/dt_f   0.5542/0.17339068n   0.491888/0.27117326n   0.616528/0.13122789n
dV/dt_r  0.5591376/0.16500006n  0.5031784/0.25017584n 0.61777296/0.12651381n
R_load = 50
[Rising Waveform]
R_fixture = 50
V_fixture = 1.5
V_fixture_min = 1.35
V_fixture_max = 1.65
0s        808.1mV    736.6mV    880.1mV
104.2ps   809.9mV    738.8mV    896.2mV
175ps     815.3mV    737mV      1.233V
228.5ps   929.5mV    737.4mV    1.508V
311.5ps   1.232V     776.6mV    1.631V
361.6ps   1.392V     864.2mV    1.644V
401.2ps   1.455V     939.8mV    1.648V
533.4ps   1.497V     1.218V     1.65V
632.7ps   1.5V       1.326V     1.65V
1.389ns   1.5V       1.35V      1.65V
[Rising Waveform]
R_fixture = 50
V_fixture = 0
V_fixture_min = 0
V_fixture_max = 0
7.44ps    0V         0V         0V
107.6ps   2.409mV    2.769mV    5.233mV
193.7ps   0V         0V         438.1mV
231.6ps   82.22mV    0V         630mV
311.8ps   375.5mV    -5.011mV   751.1mV
364.2ps   569.2mV    62.98mV    765mV
414.6ps   655.1mV    161.3mV    769mV
560.5ps   693.5mV    485.5mV    770.7mV
650.6ps   694.9mV    596.1mV    770.8mV
1.396ns   695.2mV    623.8mV    770.9mV
[Falling Waveform]
R_fixture = 50
V_fixture = 1.5
V_fixture_min = 1.35
V_fixture_max = 1.65
0s        1.499V     1.349V     1.649V
106.8ps   1.498V     1.346V     1.63V
180.3ps   1.494V     1.349V     1.285V
228ps     1.399V     1.348V     1.034V
301.6ps   1.15V      1.346V     904.9mV
361.7ps   934.3mV    1.284V     885.5mV
415.8ps   845.3mV    1.187V     881.1mV
573.4ps   808.3mV    876.1mV    879.6mV
666.1ps   807.5mV    764.7mV    879.5mV
1.389ns   807.4mV    735.6mV    879.4mV
[Falling Waveform]
R_fixture = 50
V_fixture = 0
V_fixture_min = 0
V_fixture_max = 0
7.44ps    694.5mV    623.2mV    770.2mV
117.4ps   692.2mV    620.8mV    733.6mV
182.1ps   687.4mV    622.4mV    406mV
229ps     589.9mV    621.9mV    152.4mV
309.6ps   299.4mV    611.4mV    20.48mV
363.8ps   112.4mV    534.6mV    5.548mV
409.9ps   38.94mV    441.8mV    0V
556.3ps   0V         141.1mV    0V
652.8ps   0V         26.83mV    0V
1.396ns   0V         0V         0V
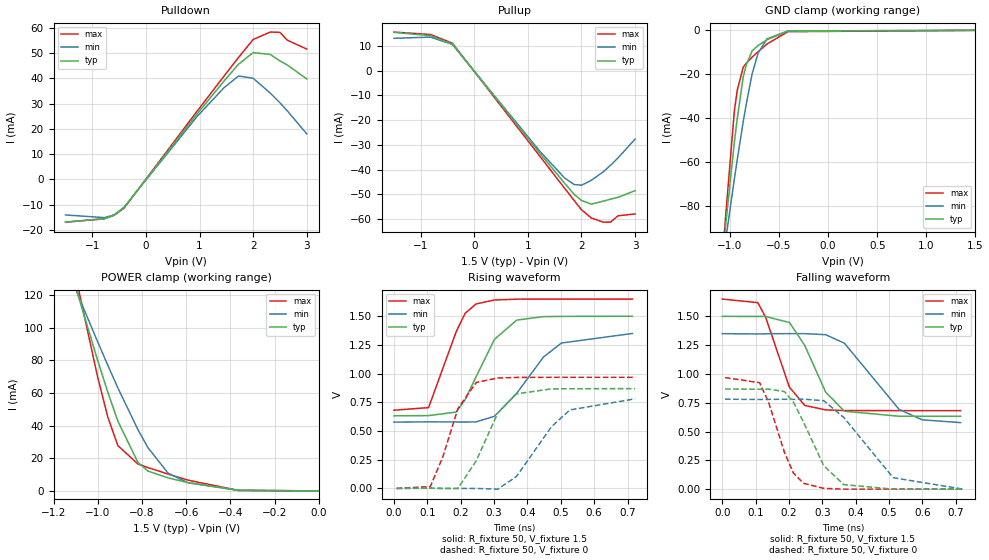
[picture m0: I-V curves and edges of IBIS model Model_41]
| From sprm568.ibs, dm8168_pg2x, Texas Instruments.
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| Model based on original model for BSHTLTCSCDVGPBFZ
|   Sub model FAST_11MA_10PER_1P5
[model]   Model_41
|[Description]  [1.5V-3-STATE-X-FAST:11MA, IND, 10%]
|   Fast slew rate (SR[1:0] = "10"), 0.73 * RExt = 1.325 * Iout
|   (I[2:0] = "110"), 11mA nominal with Rext = 50R, ,Industrial
|   temperature range (-40C to 125C, 25C nominal),10% power supply
|   tolerance
|[Input Load]
|[Output Drive] FAST:11MA
|Voltage   1.5V
|Mode   3-STATE
Model_type   3-state
Polarity   Non-Inverting
Enable   Active-Low
Cref =  15.0000pF
Rref =  100.0000M
Vref =  0V
Vmeas =  0.75
C_comp   1.5249p   1.4275p   1.6205p
[Model Spec]
[Temperature Range]   25   125   -40
[Voltage Range]   1.5   1.35   1.65
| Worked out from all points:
|   slope of the pulldown table from 0 to 0.225 V, typ, clamps not added: 36.2 ohm
|   slope of the pullup table from 0 to 0.225 V, typ, clamps not added: 36.1 ohm
|   GND clamp passes 1 mA (typ) near -0.47 V on its own axis
|   POWER clamp passes 1 mA (typ) near -0.42 V on its own axis
|   rising waveform, R_fixture 50, V_fixture 1.5: 20-80 % time 88.7ps typ, 124ps min, 68.4ps max; typ from 0.633 V to 1.5 V
|   rising waveform, R_fixture 50, V_fixture 0: 20-80 % time 84.2ps typ, 119ps min, 65.8ps max; typ from 0 V to 0.87 V
|   falling waveform, R_fixture 50, V_fixture 1.5: 20-80 % time 85.7ps typ, 124ps min, 68.3ps max; typ from 1.5 V to 0.632 V
|   falling waveform, R_fixture 50, V_fixture 0: 20-80 % time 86.4ps typ, 123ps min, 67ps max; typ from 0.869 V to 0 V
[POWER_clamp]
-1.5V     321.6mA    260.6mA    415.8mA
-1.091V   121.1mA    120.8mA    126.6mA
-1.076V   114.1mA    115.8mA    116.8mA
-1V       79.88mA    91.3mA     69.56mA
-954.5mV  60.58mA    77.05mA    45.34mA
-909.1mV  42.84mA    63.2mA     27.8mA
-818.2mV  17.47mA    37.6mA     16.51mA
-772.7mV  12.19mA    26.53mA    14.33mA
-681.8mV  7.985mA    10.89mA    10.33mA
-590.9mV  5.092mA    4.952mA    6.596mA
-363.6mV  298.9uA    465.6uA    298.1uA
0V        1.518nA    23.05nA    396.5pA
[Pulldown]
-1.5V     -16.86mA   -14.04mA   -16.9mA
-772.7mV  -15.51mA   -15.09mA   -15.55mA
-590.9mV  -14.04mA   -13.99mA   -14.12mA
-409.1mV  -11.11mA   -11mA      -11.35mA
954.5mV   25.91mA    24.89mA    26.98mA
1.455V    38.83mA    36.23mA    40.8mA
1.727V    45.55mA    40.89mA    48.2mA
2V        50.13mA    39.99mA    55.32mA
2.318V    49.42mA    34.17mA    58.25mA
2.5V      46.85mA    30.32mA    58.16mA
2.636V    45.27mA    27.17mA    55.07mA
3V        39.74mA    18.03mA    51.54mA
[Pullup]
-1.5V     15.55mA    13.13mA    15.65mA
-818.2mV  14.19mA    13.62mA    14.67mA
-409.1mV  10.85mA    10.66mA    11.17mA
1.227V    -33.46mA   -32.67mA   -34.7mA
1.682V    -45.43mA   -43.35mA   -47.47mA
1.864V    -50.03mA   -46.07mA   -52.55mA
2V        -52.51mA   -46.33mA   -56.27mA
2.182V    -53.99mA   -44.37mA   -59.58mA
2.409V    -52.78mA   -40.88mA   -61.31mA
2.545V    -51.96mA   -38.24mA   -61.26mA
2.682V    -51.26mA   -35.3mA    -58.71mA
3V        -48.54mA   -27.68mA   -57.97mA
[GND_clamp]
-1.5V     -310mA     -250.5mA   -402.4mA
-1.076V   -103.5mA   -106.1mA   -105.2mA
-1.045V   -89.74mA   -96.32mA   -85.93mA
-954.5mV  -51.19mA   -67.85mA   -36.85mA
-924.2mV  -40.06mA   -58.84mA   -27.27mA
-863.6mV  -21.23mA   -41.55mA   -16.73mA
-833.3mV  -15.79mA   -33.74mA   -15.03mA
-772.7mV  -9.342mA   -19.74mA   -12.19mA
-712.1mV  -6.927mA   -10.35mA   -9.702mA
-621.2mV  -4.26mA    -3.894mA   -6.224mA
-409.1mV  -336.9uA   -288.9uA   -618.6uA
1.5V      1.518nA    2.298uA    269.6pA
[Ramp]
dV/dt_f   0.694536/0.13104925n   0.61876/0.18856959n   0.775184/0.10361092n
dV/dt_r 0.70107072/0.12737486n 0.63137504/0.18457146n 0.77787232/99.556213p
R_load = 50
[Rising Waveform]
R_fixture = 50
V_fixture = 1.5
V_fixture_min = 1.35
V_fixture_max = 1.65
0s        632.9mV    578.2mV    681.4mV
103.8ps   634.6mV    579.9mV    704.3mV
186.5ps   665.5mV    579.1mV    1.365V
213.4ps   773.7mV    579mV      1.526V
246ps     972.2mV    579.4mV    1.607V
301.3ps   1.299V     629.1mV    1.642V
368.2ps   1.467V     830mV      1.649V
447.9ps   1.497V     1.144V     1.65V
501.8ps   1.499V     1.267V     1.65V
714.3ps   1.5V       1.35V      1.65V
[Rising Waveform]
R_fixture = 50
V_fixture = 0
V_fixture_min = 0
V_fixture_max = 0
8.21ps    0V         0V         0V
109.1ps   2.233mV    2.184mV    16.99mV
146.7ps   0V         0V         275.7mV
191.7ps   0V         0V         696mV
246.9ps   242.2mV    0V         923.7mV
311ps     656mV      -6.32mV    962.3mV
367.1ps   824.6mV    103.7mV    967.2mV
472ps     867.2mV    537.6mV    968.3mV
527.4ps   868.9mV    684.1mV    968.4mV
722.5ps   869.6mV    780.8mV    968.5mV
[Falling Waveform]
R_fixture = 50
V_fixture = 1.5
V_fixture_min = 1.35
V_fixture_max = 1.65
0s        1.499V     1.349V     1.649V
106.5ps   1.498V     1.346V     1.618V
129.9ps   1.498V     1.348V     1.492V
201.1ps   1.446V     1.349V     885.5mV
247.2ps   1.247V     1.349V     726.5mV
310ps     841mV      1.34V      687.3mV
366.1ps   676.2mV    1.266V     682.3mV
529.6ps   632.7mV    692.7mV    681.3mV
599.1ps   632.4mV    601.4mV    681.2mV
714.3ps   632.2mV    577.3mV    681.1mV
[Falling Waveform]
R_fixture = 50
V_fixture = 0
V_fixture_min = 0
V_fixture_max = 0
8.21ps    868.9mV    780.5mV    967.9mV
111.9ps   866.7mV    777.8mV    923.9mV
139.1ps   867.7mV    779mV      752.3mV
186.4ps   846.6mV    779.8mV    318.8mV
213.3ps   754.6mV    779mV      139.5mV
243.6ps   581.5mV    780.6mV    50.69mV
303.8ps   204.7mV    767.8mV    7.463mV
364ps     39.54mV    622.6mV    0V
512ps     0V         99.6mV     0V
722.5ps   0V         0V         0V
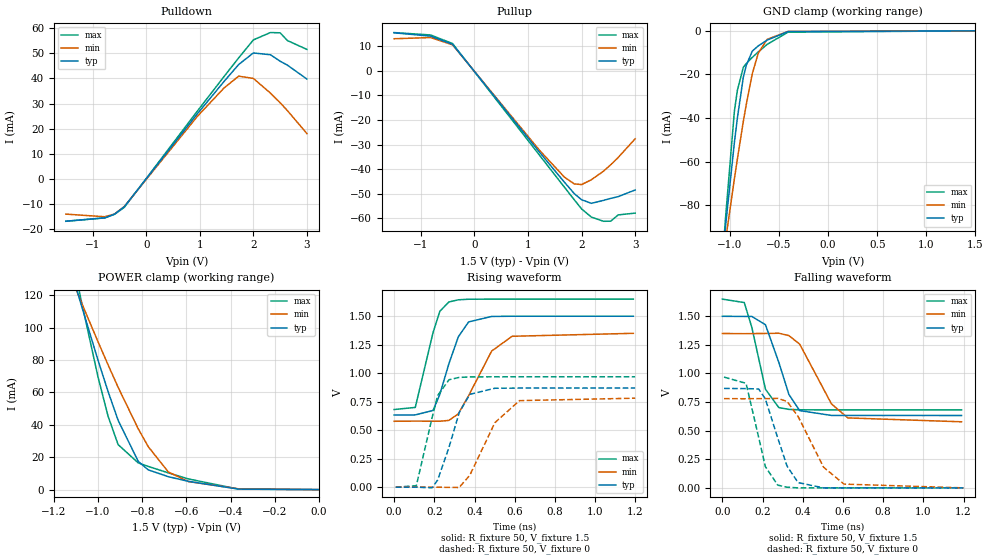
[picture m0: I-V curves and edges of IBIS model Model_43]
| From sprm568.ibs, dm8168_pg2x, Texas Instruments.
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| Model based on original model for BSHTLTCSCDVGPBFZ
|   Sub model SLOW_11MA_10PER_1P5
[model]   Model_43
|[Description]  [1.5V-3-STATE-X-SLOW:11MA, IND, 10%]
|   Slow slew rate (SR[1:0] = "01"), 0.73 * RExt = 1.325 * Iout
|   (I[2:0] = "110"), 11mA nominal with Rext = 50R, ,Industrial
|   temperature range (-40C to 125C, 25C nominal),10% power supply
|   tolerance
|[Input Load]
|[Output Drive] SLOW:11MA
|Voltage   1.5V
|Mode   3-STATE
Model_type   3-state
Polarity   Non-Inverting
Enable   Active-Low
Cref =  15.0000pF
Rref =  100.0000M
Vref =  0V
Vmeas =  0.75
C_comp   1.5249p   1.4275p   1.6205p
[Model Spec]
[Temperature Range]   25   125   -40
[Voltage Range]   1.5   1.35   1.65
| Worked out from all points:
|   slope of the pulldown table from 0 to 0.225 V, typ, clamps not added: 36.2 ohm
|   slope of the pullup table from 0 to 0.225 V, typ, clamps not added: 36.1 ohm
|   GND clamp passes 1 mA (typ) near -0.47 V on its own axis
|   POWER clamp passes 1 mA (typ) near -0.42 V on its own axis
|   rising waveform, R_fixture 50, V_fixture 1.5: 20-80 % time 95.7ps typ, 135ps min, 73.4ps max; typ from 0.633 V to 1.5 V
|   rising waveform, R_fixture 50, V_fixture 0: 20-80 % time 91ps typ, 130ps min, 71ps max; typ from 0 V to 0.87 V
|   falling waveform, R_fixture 50, V_fixture 1.5: 20-80 % time 93.7ps typ, 138ps min, 73ps max; typ from 1.5 V to 0.632 V
|   falling waveform, R_fixture 50, V_fixture 0: 20-80 % time 94.1ps typ, 137ps min, 71.9ps max; typ from 0.869 V to 0 V
[POWER_clamp]
-1.5V     321.6mA    260.6mA    415.8mA
-1.091V   121.1mA    120.8mA    126.6mA
-1.076V   114.1mA    115.8mA    116.8mA
-1V       79.88mA    91.3mA     69.56mA
-954.5mV  60.58mA    77.05mA    45.34mA
-909.1mV  42.84mA    63.2mA     27.8mA
-818.2mV  17.47mA    37.6mA     16.51mA
-772.7mV  12.19mA    26.53mA    14.33mA
-681.8mV  7.985mA    10.89mA    10.33mA
-590.9mV  5.092mA    4.952mA    6.596mA
-363.6mV  298.9uA    465.6uA    298.1uA
0V        1.518nA    23.05nA    396.5pA
[Pulldown]
-1.5V     -16.86mA   -14.04mA   -16.9mA
-772.7mV  -15.51mA   -15.09mA   -15.55mA
-590.9mV  -14.04mA   -13.99mA   -14.12mA
-409.1mV  -11.11mA   -11mA      -11.35mA
954.5mV   25.91mA    24.89mA    26.98mA
1.455V    38.83mA    36.23mA    40.8mA
1.727V    45.55mA    40.89mA    48.2mA
2V        50.13mA    39.99mA    55.32mA
2.318V    49.42mA    34.17mA    58.25mA
2.5V      46.85mA    30.32mA    58.16mA
2.636V    45.27mA    27.17mA    55.07mA
3V        39.74mA    18.03mA    51.54mA
[Pullup]
-1.5V     15.55mA    13.13mA    15.65mA
-818.2mV  14.19mA    13.62mA    14.67mA
-409.1mV  10.85mA    10.66mA    11.17mA
1.227V    -33.46mA   -32.67mA   -34.7mA
1.682V    -45.43mA   -43.35mA   -47.47mA
1.864V    -50.03mA   -46.07mA   -52.55mA
2V        -52.51mA   -46.33mA   -56.27mA
2.182V    -53.99mA   -44.37mA   -59.58mA
2.409V    -52.78mA   -40.88mA   -61.31mA
2.545V    -51.96mA   -38.24mA   -61.26mA
2.682V    -51.26mA   -35.3mA    -58.71mA
3V        -48.54mA   -27.68mA   -57.97mA
[GND_clamp]
-1.5V     -310mA     -250.5mA   -402.4mA
-1.076V   -103.5mA   -106.1mA   -105.2mA
-1.045V   -89.74mA   -96.32mA   -85.93mA
-954.5mV  -51.19mA   -67.85mA   -36.85mA
-924.2mV  -40.06mA   -58.84mA   -27.27mA
-863.6mV  -21.23mA   -41.55mA   -16.73mA
-833.3mV  -15.79mA   -33.74mA   -15.03mA
-772.7mV  -9.342mA   -19.74mA   -12.19mA
-712.1mV  -6.927mA   -10.35mA   -9.702mA
-621.2mV  -4.26mA    -3.894mA   -6.224mA
-409.1mV  -336.9uA   -288.9uA   -618.6uA
1.5V      1.518nA    2.298uA    269.6pA
[Ramp]
dV/dt_f   0.694384/0.14220511n   0.618936/0.20945458n   0.775184/0.10939435n
dV/dt_r   0.70109/0.13866583n 0.63117344/0.20326564n 0.77804632/0.10549622n
R_load = 50
[Rising Waveform]
R_fixture = 50
V_fixture = 1.5
V_fixture_min = 1.35
V_fixture_max = 1.65
0s        632.9mV    578.2mV    681.4mV
105.3ps   634.1mV    579.7mV    699.8mV
193.7ps   673.1mV    578.8mV    1.357V
227.4ps   814.1mV    578.8mV    1.543V
272.1ps   1.081V     585.8mV    1.625V
319.3ps   1.319V     643.2mV    1.644V
370.5ps   1.45V      802.5mV    1.649V
485.1ps   1.498V     1.194V     1.65V
586.9ps   1.5V       1.324V     1.65V
1.19ns    1.5V       1.35V      1.65V
[Rising Waveform]
R_fixture = 50
V_fixture = 0
V_fixture_min = 0
V_fixture_max = 0
8.2ps     0V         0V         0V
110.5ps   0V         2.017mV    12.51mV
189.1ps   -6.057mV   0V         610.6mV
216.8ps   63.54mV    0V         805.1mV
273.4ps   351.8mV    -2.024mV   942.8mV
323.9ps   654.6mV    -2.642mV   963.1mV
376.4ps   814.6mV    104.1mV    967.2mV
501.3ps   868mV      566mV      968.4mV
623.7ps   869.4mV    759.4mV    968.5mV
1.199ns   869.6mV    780.8mV    968.5mV
[Falling Waveform]
R_fixture = 50
V_fixture = 1.5
V_fixture_min = 1.35
V_fixture_max = 1.65
0s        1.499V     1.349V     1.649V
109ps     1.498V     1.347V     1.619V
146.6ps   1.498V     1.348V     1.403V
214.5ps   1.425V     1.349V     861.6mV
280.8ps   1.097V     1.351V     701.6mV
331.2ps   815.8mV    1.33V      685.5mV
384.6ps   675mV      1.256V     682.1mV
542.8ps   632.8mV    733.5mV    681.2mV
624.6ps   632.4mV    611mV      681.2mV
1.19ns    632.2mV    577.2mV    681.1mV
[Falling Waveform]
R_fixture = 50
V_fixture = 0
V_fixture_min = 0
V_fixture_max = 0
8.2ps     868.9mV    779.9mV    967.9mV
118ps     867.1mV    778.4mV    913.4mV
180.7ps   864.1mV    779.8mV    440.7mV
214.1ps   776.3mV    779.5mV    185.1mV
275.7ps   434.7mV    781.7mV    23.83mV
321.7ps   190.7mV    755.4mV    5.619mV
376.7ps   45.98mV    624.4mV    0V
503.2ps   0V         180.9mV    0V
605.3ps   0V         32.69mV    0V
1.199ns   0V         0V         0V
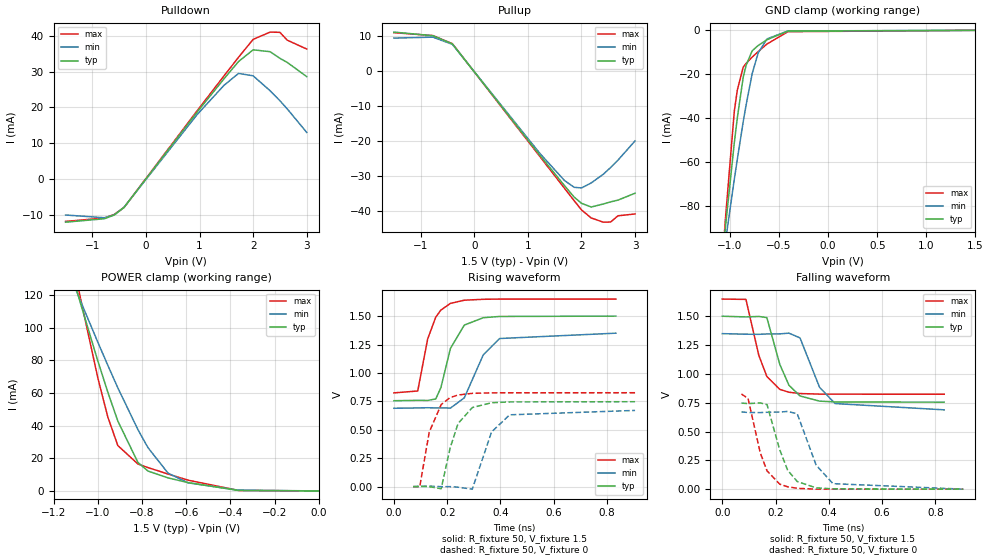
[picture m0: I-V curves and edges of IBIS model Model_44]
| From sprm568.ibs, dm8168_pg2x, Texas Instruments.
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| Model based on original model for BSHTLTCSCDVGPBFZ
|   Sub model FASTEST_8MA_10PER_1P5
[model]   Model_44
|[Description]  [1.5V-3-STATE-X-FASTEST:8MA, IND, 10%]
|   Fastest slew rate (SR[1:0] = "00"), 1.00 * RExt = 1.000 * Iout
|   (I[2:0] = "011"), 8mA nominal with Rext = 50R, ,Industrial
|   temperature range (-40C to 125C, 25C nominal),10% power supply
|   tolerance
|[Input Load]
|[Output Drive] FASTEST:8MA
|Voltage   1.5V
|Mode   3-STATE
Model_type   3-state
Polarity   Non-Inverting
Enable   Active-Low
Cref =  15.0000pF
Rref =  100.0000M
Vref =  0V
Vmeas =  0.75
C_comp   1.5249p   1.4275p   1.6205p
[Model Spec]
[Temperature Range]   25   125   -40
[Voltage Range]   1.5   1.35   1.65
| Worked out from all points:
|   slope of the pulldown table from 0 to 0.225 V, typ, clamps not added: 50.1 ohm
|   slope of the pullup table from 0 to 0.225 V, typ, clamps not added: 50.1 ohm
|   GND clamp passes 1 mA (typ) near -0.47 V on its own axis
|   POWER clamp passes 1 mA (typ) near -0.42 V on its own axis
|   rising waveform, R_fixture 50, V_fixture 1.5: 20-80 % time 58.3ps typ, 78.5ps min, 53.2ps max; typ from 0.756 V to 1.5 V
|   rising waveform, R_fixture 50, V_fixture 0: 20-80 % time 55.5ps typ, 61.5ps min, 51.2ps max; typ from 0 V to 0.747 V
|   falling waveform, R_fixture 50, V_fixture 1.5: 20-80 % time 63.9ps typ, 72.8ps min, 57.9ps max; typ from 1.5 V to 0.755 V
|   falling waveform, R_fixture 50, V_fixture 0: 20-80 % time 61.7ps typ, 67.2ps min, 55.4ps max; typ from 0.747 V to 0 V
[POWER_clamp]
-1.5V     321.6mA    260.6mA    415.8mA
-1.091V   121.1mA    120.8mA    126.6mA
-1.076V   114.1mA    115.8mA    116.8mA
-1V       79.88mA    91.3mA     69.56mA
-954.5mV  60.58mA    77.05mA    45.34mA
-909.1mV  42.84mA    63.2mA     27.8mA
-818.2mV  17.47mA    37.6mA     16.51mA
-772.7mV  12.19mA    26.53mA    14.33mA
-681.8mV  7.985mA    10.89mA    10.33mA
-590.9mV  5.092mA    4.952mA    6.596mA
-363.6mV  298.9uA    465.6uA    298.1uA
0V        1.518nA    23.05nA    396.5pA
[Pulldown]
-1.5V     -12.15mA   -10.14mA   -11.93mA
-772.7mV  -11.18mA   -10.9mA    -10.98mA
-590.9mV  -10.12mA   -10.11mA   -9.968mA
-409.1mV  -8.017mA   -7.951mA   -8.019mA
954.5mV   18.69mA    17.99mA    19.06mA
1.455V    28.01mA    26.18mA    28.82mA
1.727V    32.86mA    29.54mA    34.05mA
2V        36.15mA    28.87mA    39.08mA
2.318V    35.62mA    24.67mA    41.12mA
2.5V      33.77mA    21.88mA    41.05mA
2.636V    32.63mA    19.61mA    38.86mA
3V        28.64mA    13.01mA    36.37mA
[Pullup]
-1.5V     11.21mA    9.48mA     11.04mA
-772.7mV  10.17mA    9.762mA    10.21mA
-409.1mV  7.827mA    7.7mA      7.892mA
1.227V    -24.14mA   -23.61mA   -24.51mA
1.682V    -32.78mA   -31.32mA   -33.54mA
1.864V    -36.09mA   -33.28mA   -37.13mA
2V        -37.87mA   -33.46mA   -39.75mA
2.182V    -38.93mA   -32.03mA   -42.07mA
2.409V    -38.05mA   -29.51mA   -43.28mA
2.545V    -37.45mA   -27.6mA    -43.23mA
2.682V    -36.95mA   -25.48mA   -41.44mA
3V        -34.98mA   -19.98mA   -40.92mA
[GND_clamp]
-1.5V     -310mA     -250.5mA   -402.4mA
-1.076V   -103.5mA   -106.1mA   -105.2mA
-1.045V   -89.74mA   -96.32mA   -85.93mA
-954.5mV  -51.19mA   -67.85mA   -36.85mA
-924.2mV  -40.06mA   -58.84mA   -27.27mA
-863.6mV  -21.23mA   -41.55mA   -16.73mA
-833.3mV  -15.79mA   -33.74mA   -15.03mA
-772.7mV  -9.342mA   -19.74mA   -12.19mA
-712.1mV  -6.927mA   -10.35mA   -9.702mA
-621.2mV  -4.26mA    -3.894mA   -6.224mA
-409.1mV  -336.9uA   -288.9uA   -618.6uA
1.5V      1.518nA    2.298uA    269.6pA
[Ramp]
dV/dt_f   0.599968/0.10060699n   0.533568/0.11719928n   0.661736/90.123445p
dV/dt_r  0.6179112/90.322405p  0.5607216/0.1012291n  0.6735032/82.915016p
R_load = 50
[Rising Waveform]
R_fixture = 50
V_fixture = 1.5
V_fixture_min = 1.35
V_fixture_max = 1.65
0s        755.8mV    689.4mV    824.8mV
89.46ps   759.1mV    692.3mV    841.3mV
126.7ps   758.2mV    694.1mV    1.299V
157.1ps   771.8mV    692.4mV    1.491V
176.3ps   870.6mV    692.9mV    1.553V
212.2ps   1.216V     691.1mV    1.612V
264.2ps   1.421V     780.9mV    1.64V
335.4ps   1.486V     1.159V     1.648V
396.8ps   1.497V     1.303V     1.65V
833.3ps   1.5V       1.35V      1.65V
[Rising Waveform]
R_fixture = 50
V_fixture = 0
V_fixture_min = 0
V_fixture_max = 0
71.95ps   0V         0V         0V
96.83ps   2.581mV    2.651mV    -2.141mV
132.6ps   0V         4.597mV    479.4mV
177.4ps   -18.22mV   0V         722.1mV
211ps     339.9mV    0V         783.6mV
240.9ps   555.4mV    -4.65mV    806mV
294.3ps   695.7mV    -22.18mV   820.8mV
366.5ps   737.9mV    480.8mV    824.9mV
434.6ps   745.2mV    631.8mV    825.7mV
905.3ps   747.2mV    670.5mV    826mV
[Falling Waveform]
R_fixture = 50
V_fixture = 1.5
V_fixture_min = 1.35
V_fixture_max = 1.65
0s        1.501V     1.35V      1.65V
88.92ps   1.495V     1.345V     1.647V
137.3ps   1.499V     1.344V     1.161V
167.4ps   1.489V     1.347V     978.4mV
216.2ps   1.082V     1.348V     866.1mV
250.5ps   901.9mV    1.354V     841.4mV
291.9ps   809.1mV    1.313V     830mV
365.3ps   764.1mV    884.1mV    825mV
423.8ps   757.2mV    742.9mV    824.5mV
833.3ps   755.1mV    688.5mV    824.1mV
[Falling Waveform]
R_fixture = 50
V_fixture = 0
V_fixture_min = 0
V_fixture_max = 0
71.95ps   747.4mV    670.6mV    825.6mV
96.85ps   742.4mV    665.4mV    787.5mV
142.7ps   748.8mV    664.7mV    315.1mV
168.2ps   733.4mV    667.5mV    159.1mV
215.4ps   344.1mV    669.3mV    44.05mV
245.6ps   164mV      674.7mV    20.58mV
281.6ps   66.21mV    654.2mV    7.556mV
352.7ps   11.41mV    207.7mV    0V
415.7ps   2.629mV    47.69mV    0V
905.3ps   0V         0V         0V
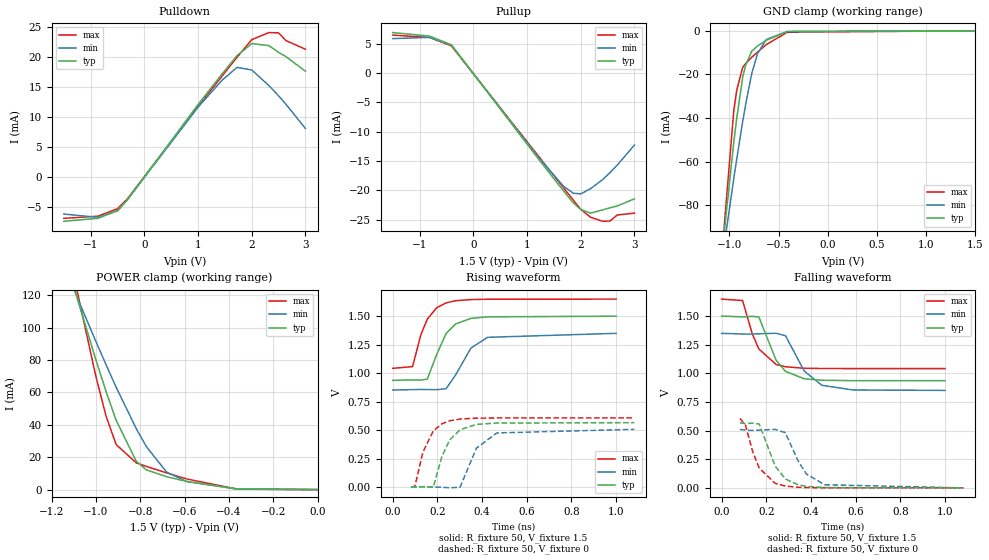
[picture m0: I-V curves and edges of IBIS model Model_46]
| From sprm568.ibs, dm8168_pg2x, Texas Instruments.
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| Model based on original model for BSHTLTCSCDVGPBFZ
|   Sub model FASTEST_5MA_10PER_1P5
[model]   Model_46
|[Description]  [1.5V-3-STATE-X-FASTEST:5MA, IND, 10%]
|   Fastest slew rate (SR[1:0] = "00"), 1.60 * RExt = 0.625 * Iout
|   (I[2:0] = "000"), 5mA nominal with Rext = 50R, ,Industrial
|   temperature range (-40C to 125C, 25C nominal),10% power supply
|   tolerance
|[Input Load]
|[Output Drive] FASTEST:5MA
|Voltage   1.5V
|Mode   3-STATE
Model_type   3-state
Polarity   Non-Inverting
Enable   Active-Low
Cref =  15.0000pF
Rref =  100.0000M
Vref =  0V
Vmeas =  0.75
C_comp   1.5249p   1.4275p   1.6205p
[Model Spec]
[Temperature Range]   25   125   -40
[Voltage Range]   1.5   1.35   1.65
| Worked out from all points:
|   slope of the pulldown table from 0 to 0.225 V, typ, clamps not added: 81.7 ohm
|   slope of the pullup table from 0 to 0.225 V, typ, clamps not added: 81.7 ohm
|   GND clamp passes 1 mA (typ) near -0.47 V on its own axis
|   POWER clamp passes 1 mA (typ) near -0.42 V on its own axis
|   rising waveform, R_fixture 50, V_fixture 1.5: 20-80 % time 74.9ps typ, 93.5ps min, 69.8ps max; typ from 0.937 V to 1.5 V
|   rising waveform, R_fixture 50, V_fixture 0: 20-80 % time 71.5ps typ, 78.4ps min, 66.9ps max; typ from 0 V to 0.566 V
|   falling waveform, R_fixture 50, V_fixture 1.5: 20-80 % time 79.4ps typ, 92.7ps min, 73.1ps max; typ from 1.5 V to 0.937 V
|   falling waveform, R_fixture 50, V_fixture 0: 20-80 % time 74.7ps typ, 83.9ps min, 68.6ps max; typ from 0.567 V to 0 V
[POWER_clamp]
-1.5V     321.6mA    260.6mA    415.8mA
-1.091V   121.1mA    120.8mA    126.6mA
-1.076V   114.1mA    115.8mA    116.8mA
-1V       79.88mA    91.3mA     69.56mA
-954.5mV  60.58mA    77.05mA    45.34mA
-909.1mV  42.84mA    63.2mA     27.8mA
-818.2mV  17.47mA    37.6mA     16.51mA
-772.7mV  12.19mA    26.53mA    14.33mA
-681.8mV  7.985mA    10.89mA    10.33mA
-590.9mV  5.092mA    4.952mA    6.596mA
-363.6mV  298.9uA    465.6uA    298.1uA
0V        1.518nA    23.05nA    396.5pA
[Pulldown]
-1.5V     -7.45mA    -6.24mA    -6.96mA
-863.6mV  -6.95mA    -6.794mA   -6.6mA
-500mV    -5.682mA   -5.687mA   -5.359mA
-318.2mV  -3.897mA   -3.877mA   -3.74mA
1V        12mA       11.57mA    11.65mA
1.455V    17.18mA    16.12mA    16.83mA
1.727V    20.16mA    18.19mA    19.88mA
2V        22.16mA    17.76mA    22.81mA
2.318V    21.82mA    15.17mA    23.99mA
2.5V      20.69mA    13.46mA    23.94mA
2.636V    19.99mA    12.06mA    22.66mA
3V        17.55mA    8mA        21.21mA
[Pullup]
-1.5V     6.87mA     5.84mA     6.44mA
-818.2mV  6.271mA    6.054mA    6.043mA
-409.1mV  4.8mA      4.74mA     4.606mA
1.227V    -14.81mA   -14.54mA   -14.31mA
1.682V    -20.1mA    -19.29mA   -19.58mA
1.864V    -22.13mA   -20.48mA   -21.67mA
2V        -23.22mA   -20.59mA   -23.2mA
2.182V    -23.86mA   -19.71mA   -24.55mA
2.409V    -23.31mA   -18.15mA   -25.25mA
2.545V    -22.95mA   -16.97mA   -25.21mA
2.682V    -22.64mA   -15.67mA   -24.17mA
3V        -21.43mA   -12.28mA   -23.87mA
[GND_clamp]
-1.5V     -310mA     -250.5mA   -402.4mA
-1.076V   -103.5mA   -106.1mA   -105.2mA
-1.045V   -89.74mA   -96.32mA   -85.93mA
-954.5mV  -51.19mA   -67.85mA   -36.85mA
-924.2mV  -40.06mA   -58.84mA   -27.27mA
-863.6mV  -21.23mA   -41.55mA   -16.73mA
-833.3mV  -15.79mA   -33.74mA   -15.03mA
-772.7mV  -9.342mA   -19.74mA   -12.19mA
-712.1mV  -6.927mA   -10.35mA   -9.702mA
-621.2mV  -4.26mA    -3.894mA   -6.224mA
-409.1mV  -336.9uA   -288.9uA   -618.6uA
1.5V      1.518nA    2.298uA    269.6pA
[Ramp]
dV/dt_f   0.452568/0.12546419n   0.401712/0.14725586n   0.486/0.11512219n
dV/dt_r  0.4651504/0.11495333n   0.421408/0.12796395n  0.4929764/0.1068926n
R_load = 50
[Rising Waveform]
R_fixture = 50
V_fixture = 1.5
V_fixture_min = 1.35
V_fixture_max = 1.65
0s        937.3mV    852.6mV    1.043V
88.74ps   941.7mV    856mV      1.058V
125.8ps   940.3mV    857.9mV    1.336V
154.9ps   948.6mV    856.3mV    1.475V
196.7ps   1.164V     855.8mV    1.574V
239ps     1.349V     864.7mV    1.617V
281.3ps   1.432V     984.2mV    1.636V
350.2ps   1.481V     1.221V     1.646V
424.5ps   1.495V     1.315V     1.649V
1ns       1.5V       1.35V      1.65V
[Rising Waveform]
R_fixture = 50
V_fixture = 0
V_fixture_min = 0
V_fixture_max = 0
81.78ps   0V         0V         0V
99.43ps   3.661mV    2.943mV    8.429mV
135.1ps   2.023mV    5.208mV    308.9mV
181.8ps   0V         2.079mV    494.5mV
220.2ps   270.4mV    0V         556.5mV
254.6ps   414.4mV    -5.423mV   582.9mV
301.5ps   504.5mV    0V         598.3mV
374.5ps   551mV      342.6mV    605.9mV
466.3ps   563.5mV    476.3mV    608mV
1.082ns   566.4mV    508.1mV    608.4mV
[Falling Waveform]
R_fixture = 50
V_fixture = 1.5
V_fixture_min = 1.35
V_fixture_max = 1.65
0s        1.501V     1.35V      1.649V
93.58ps   1.494V     1.344V     1.637V
136.8ps   1.498V     1.344V     1.347V
166.2ps   1.494V     1.346V     1.214V
243.7ps   1.115V     1.351V     1.078V
285.9ps   1.018V     1.329V     1.058V
369.2ps   953.1mV    1.022V     1.045V
448.6ps   940.1mV    896.1mV    1.043V
588.3ps   936.8mV    855.3mV    1.042V
1ns       936.6mV    851.7mV    1.042V
[Falling Waveform]
R_fixture = 50
V_fixture = 0
V_fixture_min = 0
V_fixture_max = 0
81.78ps   567.1mV    509.1mV    607.4mV
106.7ps   561.5mV    504.7mV    547.1mV
139.5ps   565.4mV    501.8mV    311.2mV
167.9ps   557.4mV    504.3mV    172.8mV
239.9ps   189.1mV    510.3mV    38.69mV
285ps     78.07mV    482.4mV    15.89mV
343ps     25.87mV    231.6mV    4.909mV
379.5ps   12.48mV    121mV      2.399mV
461.2ps   2.681mV    27.09mV    0V
1.082ns   0V         0V         0V
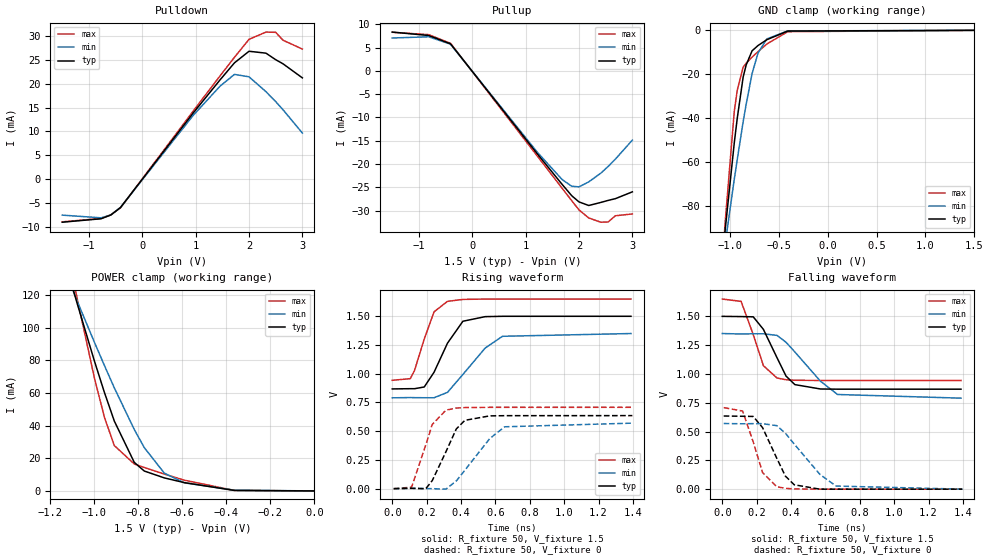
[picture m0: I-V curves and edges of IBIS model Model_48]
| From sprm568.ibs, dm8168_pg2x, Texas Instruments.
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| Model based on original model for BSHTLTCSCDVGPBFZ
|   Sub model SLOW_6MA_10PER_1P5
[model]   Model_48
|[Description]  [1.5V-3-STATE-X-SLOW:6MA, IND, 10%]
|   Slow slew rate (SR[1:0] = "01"), 1.33 * RExt = 0.750 * Iout
|   (I[2:0] = "001"), 6mA nominal with Rext = 50R, ,Industrial
|   temperature range (-40C to 125C, 25C nominal),10% power supply
|   tolerance
|[Input Load]
|[Output Drive] SLOW:6MA
|Voltage   1.5V
|Mode   3-STATE
Model_type   3-state
Polarity   Non-Inverting
Enable   Active-Low
Cref =  15.0000pF
Rref =  100.0000M
Vref =  0V
Vmeas =  0.75
C_comp   1.5249p   1.4275p   1.6205p
[Model Spec]
[Temperature Range]   25   125   -40
[Voltage Range]   1.5   1.35   1.65
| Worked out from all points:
|   slope of the pulldown table from 0 to 0.225 V, typ, clamps not added: 67.5 ohm
|   slope of the pullup table from 0 to 0.225 V, typ, clamps not added: 67.5 ohm
|   GND clamp passes 1 mA (typ) near -0.47 V on its own axis
|   POWER clamp passes 1 mA (typ) near -0.42 V on its own axis
|   rising waveform, R_fixture 50, V_fixture 1.5: 20-80 % time 122ps typ, 192ps min, 89.5ps max; typ from 0.868 V to 1.5 V
|   rising waveform, R_fixture 50, V_fixture 0: 20-80 % time 116ps typ, 180ps min, 85.6ps max; typ from 0 V to 0.636 V
|   falling waveform, R_fixture 50, V_fixture 1.5: 20-80 % time 122ps typ, 202ps min, 88.7ps max; typ from 1.5 V to 0.867 V
|   falling waveform, R_fixture 50, V_fixture 0: 20-80 % time 118ps typ, 194ps min, 85.7ps max; typ from 0.635 V to 0 V
[POWER_clamp]
-1.5V     321.6mA    260.6mA    415.8mA
-1.091V   121.1mA    120.8mA    126.6mA
-1.076V   114.1mA    115.8mA    116.8mA
-1V       79.88mA    91.3mA     69.56mA
-954.5mV  60.58mA    77.05mA    45.34mA
-909.1mV  42.84mA    63.2mA     27.8mA
-818.2mV  17.47mA    37.6mA     16.51mA
-772.7mV  12.19mA    26.53mA    14.33mA
-681.8mV  7.985mA    10.89mA    10.33mA
-590.9mV  5.092mA    4.952mA    6.596mA
-363.6mV  298.9uA    465.6uA    298.1uA
0V        1.518nA    23.05nA    396.5pA
[Pulldown]
-1.5V     -9.02mA    -7.54mA    -8.95mA
-772.7mV  -8.299mA   -8.105mA   -8.235mA
-590.9mV  -7.513mA   -7.517mA   -7.478mA
-409.1mV  -5.951mA   -5.915mA   -6.017mA
954.5mV   13.88mA    13.38mA    14.3mA
1.455V    20.79mA    19.48mA    21.63mA
1.727V    24.39mA    21.97mA    25.55mA
2V        26.82mA    21.46mA    29.32mA
2.318V    26.42mA    18.34mA    30.84mA
2.5V      25.05mA    16.26mA    30.79mA
2.636V    24.2mA     14.57mA    29.14mA
3V        21.24mA    9.67mA     27.28mA
[Pullup]
-1.5V     8.32mA     7.05mA     8.28mA
-818.2mV  7.591mA    7.315mA    7.769mA
-409.1mV  5.809mA    5.727mA    5.921mA
1.227V    -17.92mA   -17.56mA   -18.4mA
1.682V    -24.33mA   -23.3mA    -25.16mA
1.864V    -26.79mA   -24.75mA   -27.86mA
2V        -28.11mA   -24.88mA   -29.82mA
2.182V    -28.88mA   -23.81mA   -31.56mA
2.409V    -28.22mA   -21.94mA   -32.46mA
2.545V    -27.79mA   -20.51mA   -32.42mA
2.682V    -27.41mA   -18.93mA   -31.08mA
3V        -25.95mA   -14.85mA   -30.69mA
[GND_clamp]
-1.5V     -310mA     -250.5mA   -402.4mA
-1.076V   -103.5mA   -106.1mA   -105.2mA
-1.045V   -89.74mA   -96.32mA   -85.93mA
-954.5mV  -51.19mA   -67.85mA   -36.85mA
-924.2mV  -40.06mA   -58.84mA   -27.27mA
-863.6mV  -21.23mA   -41.55mA   -16.73mA
-833.3mV  -15.79mA   -33.74mA   -15.03mA
-772.7mV  -9.342mA   -19.74mA   -12.19mA
-712.1mV  -6.927mA   -10.35mA   -9.702mA
-621.2mV  -4.26mA    -3.894mA   -6.224mA
-409.1mV  -336.9uA   -288.9uA   -618.6uA
1.5V      1.518nA    2.298uA    269.6pA
[Ramp]
dV/dt_f   0.506296/0.1810334n   0.448624/0.28600213n   0.565872/0.13728853n
dV/dt_r 0.51066592/0.17218614n 0.45982072/0.26089974n 0.56667778/0.13255149n
R_load = 50
[Rising Waveform]
R_fixture = 50
V_fixture = 1.5
V_fixture_min = 1.35
V_fixture_max = 1.65
0s        867.9mV    790.4mV    943mV
104.7ps   870mV      792.8mV    957.3mV
129.3ps   869.8mV    792mV      1.028V
185.9ps   884.8mV    791.2mV    1.302V
243ps     1.013V     791.1mV    1.539V
321.1ps   1.266V     837.9mV    1.63V
411ps     1.457V     994mV      1.647V
540.7ps   1.497V     1.224V     1.65V
641.2ps   1.5V       1.326V     1.65V
1.389ns   1.5V       1.35V      1.65V
[Rising Waveform]
R_fixture = 50
V_fixture = 0
V_fixture_min = 0
V_fixture_max = 0
8.2ps     0V         0V         0V
112.4ps   2.798mV    2.691mV    12.71mV
195.1ps   0V         0V         380.6mV
232.4ps   69.41mV    0V         557.9mV
312.1ps   320.8mV    -4.488mV   683.3mV
372.3ps   519.5mV    66.8mV     701.5mV
422.4ps   594.6mV    160.5mV    705.6mV
566.6ps   633.3mV    435.2mV    707.7mV
653.5ps   635.1mV    538.3mV    707.8mV
1.397ns   635.6mV    570.2mV    707.9mV
[Falling Waveform]
R_fixture = 50
V_fixture = 1.5
V_fixture_min = 1.35
V_fixture_max = 1.65
0s        1.499V     1.35V      1.649V
109.5ps   1.497V     1.346V     1.629V
180.1ps   1.495V     1.348V     1.341V
239.3ps   1.386V     1.348V     1.071V
318.2ps   1.141V     1.334V     964.5mV
371.1ps   980.6mV    1.274V     949.1mV
422.4ps   906.9mV    1.19V      944.7mV
571.8ps   868.9mV    935.6mV    942.8mV
670.9ps   867.4mV    821.2mV    942.8mV
1.389ns   867.2mV    789.5mV    942.7mV
[Falling Waveform]
R_fixture = 50
V_fixture = 0
V_fixture_min = 0
V_fixture_max = 0
8.2ps     634.6mV    569.5mV    707.3mV
118.4ps   632.3mV    567.1mV    677.7mV
180.1ps   630.8mV    568.5mV    409mV
234.4ps   533.8mV    568.3mV    144.1mV
317.2ps   267.7mV    550.9mV    21.2mV
367.4ps   112.9mV    484.8mV    7.079mV
418.6ps   38.06mV    391.5mV    2.332mV
567.6ps   0V         128.9mV    0V
661.7ps   0V         26.93mV    0V
1.397ns   0V         0V         0V
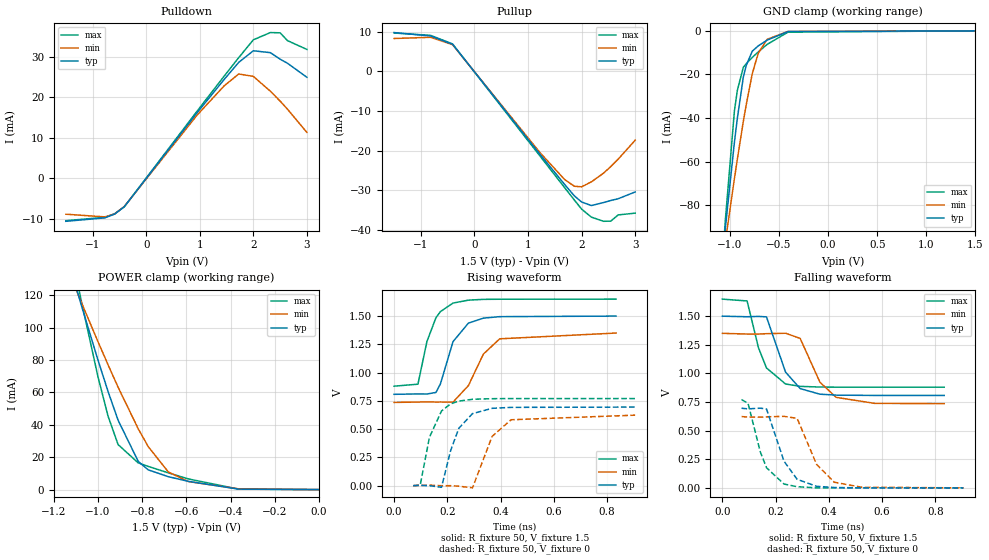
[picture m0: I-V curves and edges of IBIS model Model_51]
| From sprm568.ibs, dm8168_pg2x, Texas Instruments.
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| Model based on original model for BSHTLTCSCDVGPBFZ
|   Sub model FASTEST_7MA_10PER_1P5
[model]   Model_51
|[Description]  [1.5V-3-STATE-X-FASTEST:7MA, IND, 10%]
|   Fastest slew rate (SR[1:0] = "00"), 1.14 * RExt = 0.875 * Iout
|   (I[2:0] = "010"), 7mA nominal with Rext = 50R, ,Industrial
|   temperature range (-40C to 125C, 25C nominal),10% power supply
|   tolerance
|[Input Load]
|[Output Drive] FASTEST:7MA
|Voltage   1.5V
|Mode   3-STATE
Model_type   3-state
Polarity   Non-Inverting
Enable   Active-Low
Cref =  15.0000pF
Rref =  100.0000M
Vref =  0V
Vmeas =  0.75
C_comp   1.5249p   1.4275p   1.6205p
[Model Spec]
[Temperature Range]   25   125   -40
[Voltage Range]   1.5   1.35   1.65
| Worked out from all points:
|   slope of the pulldown table from 0 to 0.225 V, typ, clamps not added: 57.5 ohm
|   slope of the pullup table from 0 to 0.225 V, typ, clamps not added: 57.5 ohm
|   GND clamp passes 1 mA (typ) near -0.47 V on its own axis
|   POWER clamp passes 1 mA (typ) near -0.42 V on its own axis
|   rising waveform, R_fixture 50, V_fixture 1.5: 20-80 % time 63.2ps typ, 82.7ps min, 57.2ps max; typ from 0.808 V to 1.5 V
|   rising waveform, R_fixture 50, V_fixture 0: 20-80 % time 60.1ps typ, 66.7ps min, 55.3ps max; typ from 0 V to 0.695 V
|   falling waveform, R_fixture 50, V_fixture 1.5: 20-80 % time 68.2ps typ, 79.8ps min, 61.6ps max; typ from 1.5 V to 0.807 V
|   falling waveform, R_fixture 50, V_fixture 0: 20-80 % time 65.3ps typ, 73.2ps min, 58.5ps max; typ from 0.696 V to 0 V
[POWER_clamp]
-1.5V     321.6mA    260.6mA    415.8mA
-1.091V   121.1mA    120.8mA    126.6mA
-1.076V   114.1mA    115.8mA    116.8mA
-1V       79.88mA    91.3mA     69.56mA
-954.5mV  60.58mA    77.05mA    45.34mA
-909.1mV  42.84mA    63.2mA     27.8mA
-818.2mV  17.47mA    37.6mA     16.51mA
-772.7mV  12.19mA    26.53mA    14.33mA
-681.8mV  7.985mA    10.89mA    10.33mA
-590.9mV  5.092mA    4.952mA    6.596mA
-363.6mV  298.9uA    465.6uA    298.1uA
0V        1.517nA    23.05nA    396.5pA
[Pulldown]
-1.5V     -10.59mA   -8.84mA    -10.44mA
-772.7mV  -9.742mA   -9.502mA   -9.607mA
-590.9mV  -8.819mA   -8.812mA   -8.723mA
-409.1mV  -6.984mA   -6.933mA   -7.018mA
954.5mV   16.28mA    15.69mA    16.68mA
1.455V    24.41mA    22.83mA    25.23mA
1.727V    28.63mA    25.76mA    29.8mA
2V        31.49mA    25.17mA    34.2mA
2.318V    31.02mA    21.5mA     35.98mA
2.5V      29.41mA    19.07mA    35.92mA
2.636V    28.42mA    17.09mA    34mA
3V        24.94mA    11.34mA    31.82mA
[Pullup]
-1.5V     9.77mA     8.27mA     9.66mA
-818.2mV  8.911mA    8.576mA    9.063mA
-409.1mV  6.818mA    6.713mA    6.907mA
1.227V    -21.03mA   -20.59mA   -21.46mA
1.682V    -28.55mA   -27.31mA   -29.35mA
1.864V    -31.44mA   -29.02mA   -32.49mA
2V        -32.99mA   -29.17mA   -34.79mA
2.182V    -33.9mA    -27.92mA   -36.81mA
2.409V    -33.14mA   -25.72mA   -37.87mA
2.545V    -32.62mA   -24.06mA   -37.83mA
2.682V    -32.18mA   -22.2mA    -36.26mA
3V        -30.46mA   -17.41mA   -35.81mA
[GND_clamp]
-1.5V     -310mA     -250.5mA   -402.4mA
-1.076V   -103.5mA   -106.1mA   -105.2mA
-1.045V   -89.74mA   -96.32mA   -85.93mA
-954.5mV  -51.19mA   -67.85mA   -36.85mA
-924.2mV  -40.06mA   -58.84mA   -27.27mA
-863.6mV  -21.23mA   -41.55mA   -16.73mA
-833.3mV  -15.79mA   -33.74mA   -15.03mA
-772.7mV  -9.342mA   -19.74mA   -12.19mA
-712.1mV  -6.927mA   -10.35mA   -9.702mA
-621.2mV  -4.26mA    -3.894mA   -6.224mA
-409.1mV  -336.9uA   -288.9uA   -618.6uA
1.5V      1.518nA    2.298uA    269.6pA
[Ramp]
dV/dt_f   0.557552/0.10777913n   0.4958/0.12707843n   0.616848/96.466815p
dV/dt_r   0.573676/97.048329p  0.5202232/0.1086754n  0.6274656/88.509172p
R_load = 50
[Rising Waveform]
R_fixture = 50
V_fixture = 1.5
V_fixture_min = 1.35
V_fixture_max = 1.65
0s        808mV      736.5mV    880.1mV
89.45ps   811.7mV    739.5mV    897.8mV
123.2ps   810.8mV    741.5mV    1.275V
157.2ps   824.8mV    739.7mV    1.486V
174.1ps   901.5mV    740.1mV    1.54V
221.2ps   1.274V     739mV      1.615V
279.1ps   1.438V     885.7mV    1.641V
335.3ps   1.482V     1.164V     1.648V
396.6ps   1.495V     1.299V     1.649V
833.3ps   1.5V       1.35V      1.65V
[Rising Waveform]
R_fixture = 50
V_fixture = 0
V_fixture_min = 0
V_fixture_max = 0
71.93ps   0V         0V         0V
98.12ps   2.907mV    2.722mV    6.619mV
132.8ps   0V         4.865mV    428.9mV
177.9ps   -14.03mV   0V         660.2mV
212ps     308.8mV    0V         723.5mV
243.1ps   507.9mV    -4.289mV   748.2mV
294.4ps   637.4mV    -19.17mV   764.2mV
368.1ps   684.2mV    436.1mV    769.5mV
439.1ps   692.7mV    583.1mV    770.5mV
905.3ps   695.2mV    623.8mV    770.9mV
[Falling Waveform]
R_fixture = 50
V_fixture = 1.5
V_fixture_min = 1.35
V_fixture_max = 1.65
0s        1.5V       1.35V      1.649V
93ps      1.495V     1.344V     1.633V
135.6ps   1.498V     1.344V     1.225V
165.7ps   1.494V     1.347V     1.048V
237.4ps   1.011V     1.351V     907.5mV
292.3ps   867.5mV    1.306V     886.8mV
366.4ps   818.4mV    923.5mV    880.8mV
427.5ps   810.2mV    790.7mV    879.9mV
572.1ps   807.5mV    738.2mV    879.5mV
833.3ps   807.4mV    735.7mV    879.4mV
[Falling Waveform]
R_fixture = 50
V_fixture = 0
V_fixture_min = 0
V_fixture_max = 0
71.93ps   695.6mV    622.8mV    771.5mV
96.66ps   690.2mV    618.5mV    737.8mV
142.4ps   696.3mV    617.8mV    315.6mV
165.9ps   688.8mV    620.4mV    175.7mV
231.6ps   232.8mV    624.9mV    33.52mV
280.9ps   74.65mV    607.1mV    10.07mV
353.9ps   13.53mV    205.4mV    0V
420.4ps   3.117mV    49.09mV    0V
523.5ps   0V         5.43mV     0V
905.3ps   0V         0V         0V
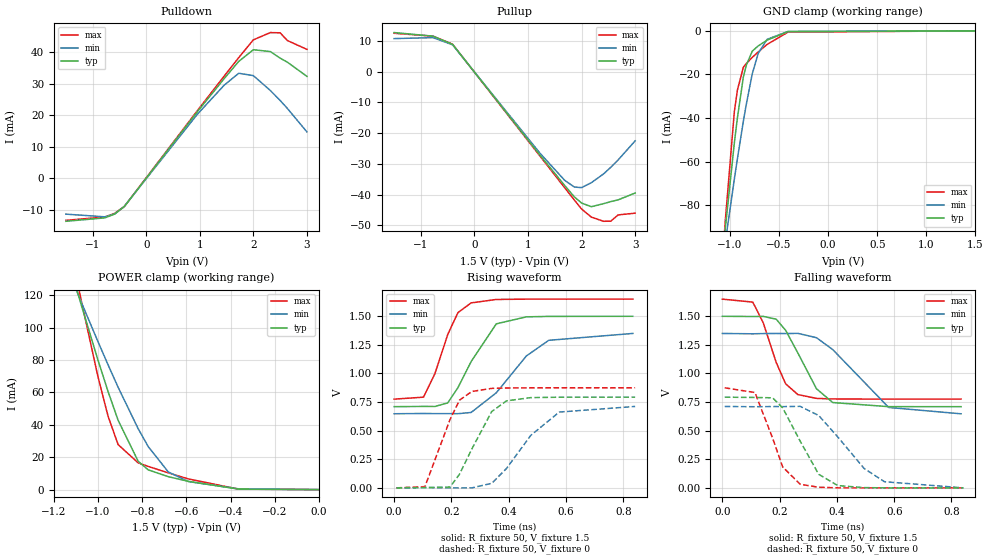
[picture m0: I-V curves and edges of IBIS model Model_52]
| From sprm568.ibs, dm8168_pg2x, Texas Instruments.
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| Model based on original model for BSHTLTCSCDVGPBFZ
|   Sub model FAST_9MA_10PER_1P5
[model]   Model_52
|[Description]  [1.5V-3-STATE-X-FAST:9MA, IND, 10%]
|   Fast slew rate (SR[1:0] = "10"), 0.88 * RExt = 1.125 * Iout
|   (I[2:0] = "100"), 9mA nominal with Rext = 50R, ,Industrial
|   temperature range (-40C to 125C, 25C nominal),10% power supply
|   tolerance
|[Input Load]
|[Output Drive] FAST:9MA
|Voltage   1.5V
|Mode   3-STATE
Model_type   3-state
Polarity   Non-Inverting
Enable   Active-Low
Cref =  15.0000pF
Rref =  100.0000M
Vref =  0V
Vmeas =  0.75
C_comp   1.5249p   1.4275p   1.6205p
[Model Spec]
[Temperature Range]   25   125   -40
[Voltage Range]   1.5   1.35   1.65
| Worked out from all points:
|   slope of the pulldown table from 0 to 0.225 V, typ, clamps not added: 44.4 ohm
|   slope of the pullup table from 0 to 0.225 V, typ, clamps not added: 44.4 ohm
|   GND clamp passes 1 mA (typ) near -0.47 V on its own axis
|   POWER clamp passes 1 mA (typ) near -0.42 V on its own axis
|   rising waveform, R_fixture 50, V_fixture 1.5: 20-80 % time 101ps typ, 145ps min, 73.9ps max; typ from 0.71 V to 1.5 V
|   rising waveform, R_fixture 50, V_fixture 0: 20-80 % time 95.7ps typ, 135ps min, 71ps max; typ from 0 V to 0.793 V
|   falling waveform, R_fixture 50, V_fixture 1.5: 20-80 % time 99.2ps typ, 144ps min, 74.1ps max; typ from 1.5 V to 0.709 V
|   falling waveform, R_fixture 50, V_fixture 0: 20-80 % time 98.9ps typ, 144ps min, 72ps max; typ from 0.792 V to 0 V
[POWER_clamp]
-1.5V     321.6mA    260.6mA    415.8mA
-1.091V   121.1mA    120.8mA    126.6mA
-1.076V   114.1mA    115.8mA    116.8mA
-1V       79.88mA    91.3mA     69.56mA
-954.5mV  60.58mA    77.05mA    45.34mA
-909.1mV  42.84mA    63.2mA     27.8mA
-818.2mV  17.47mA    37.6mA     16.51mA
-772.7mV  12.19mA    26.53mA    14.33mA
-681.8mV  7.985mA    10.89mA    10.33mA
-590.9mV  5.092mA    4.952mA    6.596mA
-363.6mV  298.9uA    465.6uA    298.1uA
0V        1.518nA    23.05nA    396.5pA
[Pulldown]
-1.5V     -13.72mA   -11.44mA   -13.42mA
-772.7mV  -12.63mA   -12.3mA    -12.35mA
-590.9mV  -11.43mA   -11.4mA    -11.21mA
-409.1mV  -9.05mA    -8.969mA   -9.02mA
954.5mV   21.1mA     20.29mA    21.44mA
1.455V    31.62mA    29.53mA    32.42mA
1.727V    37.09mA    33.33mA    38.3mA
2V        40.81mA    32.58mA    43.95mA
2.318V    40.22mA    27.84mA    46.26mA
2.5V      38.13mA    24.69mA    46.18mA
2.636V    36.84mA    22.13mA    43.72mA
3V        32.34mA    14.69mA    40.92mA
[Pullup]
-1.5V     12.66mA    10.7mA     12.43mA
-772.7mV  11.49mA    11.01mA    11.49mA
-409.1mV  8.835mA    8.685mA    8.877mA
1.227V    -27.25mA   -26.63mA   -27.57mA
1.682V    -37mA      -35.33mA   -37.72mA
1.864V    -40.74mA   -37.55mA   -41.76mA
2V        -42.75mA   -37.75mA   -44.71mA
2.182V    -43.95mA   -36.14mA   -47.32mA
2.409V    -42.96mA   -33.3mA    -48.69mA
2.545V    -42.29mA   -31.14mA   -48.64mA
2.682V    -41.72mA   -28.75mA   -46.62mA
3V        -39.5mA    -22.54mA   -46.04mA
[GND_clamp]
-1.5V     -310mA     -250.5mA   -402.4mA
-1.076V   -103.5mA   -106.1mA   -105.2mA
-1.045V   -89.74mA   -96.32mA   -85.93mA
-954.5mV  -51.19mA   -67.85mA   -36.85mA
-924.2mV  -40.06mA   -58.84mA   -27.27mA
-863.6mV  -21.23mA   -41.55mA   -16.73mA
-833.3mV  -15.79mA   -33.74mA   -15.03mA
-772.7mV  -9.342mA   -19.74mA   -12.19mA
-712.1mV  -6.927mA   -10.35mA   -9.702mA
-621.2mV  -4.26mA    -3.894mA   -6.224mA
-409.1mV  -336.9uA   -288.9uA   -618.6uA
1.5V      1.518nA    2.298uA    269.6pA
[Ramp]
dV/dt_f   0.632704/0.14699627n   0.562784/0.21841789n   0.699824/0.11437665n
dV/dt_r 0.63890112/0.14121935n 0.57537448/0.20751383n 0.70149584/0.10949647n
R_load = 50
[Rising Waveform]
R_fixture = 50
V_fixture = 1.5
V_fixture_min = 1.35
V_fixture_max = 1.65
0s        709.9mV    647.9mV    775.6mV
102.6ps   711.9mV    650.1mV    792.9mV
142.5ps   711.5mV    649.1mV    998.8mV
187.3ps   743mV      649.1mV    1.341V
222.8ps   875.8mV    648.5mV    1.532V
268.9ps   1.104V     659.1mV    1.617V
356.8ps   1.434V     831.2mV    1.647V
461.7ps   1.495V     1.153V     1.65V
539.9ps   1.499V     1.29V      1.65V
833.3ps   1.5V       1.35V      1.65V
[Rising Waveform]
R_fixture = 50
V_fixture = 0
V_fixture_min = 0
V_fixture_max = 0
8.21ps    0V         0V         0V
107.7ps   2.512mV    2.553mV    10.84mV
195.1ps   7.342mV    0V         596.6mV
228.3ps   119.3mV    0V         766.6mV
271.4ps   340.1mV    0V         842.7mV
340.7ps   667.1mV    39.39mV    869.6mV
392.3ps   760.5mV    169.2mV    873.2mV
477.2ps   789mV      459.3mV    874.3mV
576.7ps   792.5mV    662.7mV    874.5mV
841.5ps   793mV      711.7mV    874.6mV
[Falling Waveform]
R_fixture = 50
V_fixture = 1.5
V_fixture_min = 1.35
V_fixture_max = 1.65
0s        1.499V     1.349V     1.649V
106.3ps   1.497V     1.346V     1.623V
142.9ps   1.498V     1.348V     1.441V
188ps     1.474V     1.349V     1.096V
221.1ps   1.376V     1.348V     908.5mV
263.7ps   1.178V     1.35V      815.1mV
328.6ps   866mV      1.312V     781.7mV
385.5ps   745.4mV    1.208V     776.8mV
580.7ps   709.5mV    702.5mV    775.4mV
833.3ps   709.2mV    647mV      775.3mV
[Falling Waveform]
R_fixture = 50
V_fixture = 0
V_fixture_min = 0
V_fixture_max = 0
8.21ps    792.3mV    711.1mV    874mV
113.8ps   789.8mV    708.7mV    833.1mV
175.6ps   786.7mV    710.6mV    433.4mV
210.6ps   699.4mV    709.8mV    182.9mV
271.6ps   408.7mV    712.3mV    31.47mV
336.4ps   118.3mV    632.4mV    5.267mV
403.1ps   20.06mV    444.6mV    0V
495ps     2.158mV    169.3mV    0V
566ps     0V         53.57mV    0V
841.5ps   0V         0V         0V
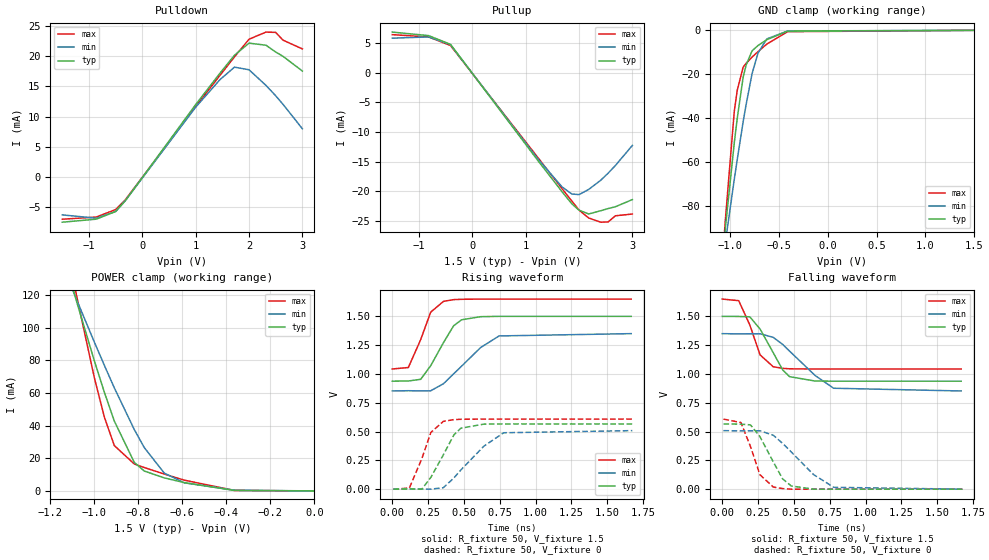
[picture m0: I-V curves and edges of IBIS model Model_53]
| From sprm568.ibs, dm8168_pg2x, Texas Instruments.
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| Model based on original model for BSHTLTCSCDVGPBFZ
|   Sub model SLOWEST_5MA_10PER_1P5
[model]   Model_53
|[Description]  [1.5V-3-STATE-X-SLOWEST:5MA, IND, 10%]
|   Slowest slew rate (SR[1:0] = "11"), 1.60 * RExt = 0.625 * Iout
|   (I[2:0] = "000"), 5mA nominal with Rext = 50R, ,Industrial
|   temperature range (-40C to 125C, 25C nominal),10% power supply
|   tolerance
|[Input Load]
|[Output Drive] SLOWEST:5MA
|Voltage   1.5V
|Mode   3-STATE
Model_type   3-state
Polarity   Non-Inverting
Enable   Active-Low
Cref =  15.0000pF
Rref =  100.0000M
Vref =  0V
Vmeas =  0.75
C_comp   1.5249p   1.4275p   1.6205p
[Model Spec]
[Temperature Range]   25   125   -40
[Voltage Range]   1.5   1.35   1.65
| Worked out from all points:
|   slope of the pulldown table from 0 to 0.225 V, typ, clamps not added: 81.7 ohm
|   slope of the pullup table from 0 to 0.225 V, typ, clamps not added: 81.7 ohm
|   GND clamp passes 1 mA (typ) near -0.47 V on its own axis
|   POWER clamp passes 1 mA (typ) near -0.42 V on its own axis
|   rising waveform, R_fixture 50, V_fixture 1.5: 20-80 % time 153ps typ, 250ps min, 107ps max; typ from 0.937 V to 1.5 V
|   rising waveform, R_fixture 50, V_fixture 0: 20-80 % time 147ps typ, 238ps min, 103ps max; typ from 0 V to 0.566 V
|   falling waveform, R_fixture 50, V_fixture 1.5: 20-80 % time 149ps typ, 257ps min, 102ps max; typ from 1.5 V to 0.937 V
|   falling waveform, R_fixture 50, V_fixture 0: 20-80 % time 144ps typ, 247ps min, 99.3ps max; typ from 0.565 V to 0 V
[POWER_clamp]
-1.5V     321.6mA    260.6mA    415.8mA
-1.091V   121.1mA    120.8mA    126.6mA
-1.076V   114.1mA    115.8mA    116.8mA
-1V       79.88mA    91.3mA     69.56mA
-954.5mV  60.58mA    77.05mA    45.34mA
-909.1mV  42.84mA    63.2mA     27.8mA
-818.2mV  17.47mA    37.6mA     16.51mA
-772.7mV  12.19mA    26.53mA    14.33mA
-681.8mV  7.985mA    10.89mA    10.33mA
-590.9mV  5.092mA    4.952mA    6.596mA
-363.6mV  298.9uA    465.6uA    298.1uA
0V        1.518nA    23.05nA    396.5pA
[Pulldown]
-1.5V     -7.45mA    -6.24mA    -6.96mA
-863.6mV  -6.95mA    -6.794mA   -6.6mA
-500mV    -5.682mA   -5.687mA   -5.359mA
-318.2mV  -3.897mA   -3.877mA   -3.74mA
1V        12mA       11.57mA    11.65mA
1.455V    17.18mA    16.12mA    16.83mA
1.727V    20.16mA    18.19mA    19.88mA
2V        22.16mA    17.76mA    22.81mA
2.318V    21.82mA    15.17mA    23.99mA
2.5V      20.69mA    13.46mA    23.94mA
2.636V    19.99mA    12.06mA    22.66mA
3V        17.55mA    8mA        21.21mA
[Pullup]
-1.5V     6.87mA     5.84mA     6.44mA
-818.2mV  6.271mA    6.054mA    6.043mA
-409.1mV  4.8mA      4.74mA     4.606mA
1.227V    -14.81mA   -14.54mA   -14.31mA
1.682V    -20.1mA    -19.29mA   -19.58mA
1.864V    -22.13mA   -20.48mA   -21.67mA
2V        -23.22mA   -20.59mA   -23.2mA
2.182V    -23.86mA   -19.71mA   -24.55mA
2.409V    -23.31mA   -18.15mA   -25.25mA
2.545V    -22.95mA   -16.97mA   -25.21mA
2.682V    -22.64mA   -15.67mA   -24.17mA
3V        -21.43mA   -12.28mA   -23.87mA
[GND_clamp]
-1.5V     -310mA     -250.5mA   -402.4mA
-1.076V   -103.5mA   -106.1mA   -105.2mA
-1.045V   -89.74mA   -96.32mA   -85.93mA
-954.5mV  -51.19mA   -67.85mA   -36.85mA
-924.2mV  -40.06mA   -58.84mA   -27.27mA
-863.6mV  -21.23mA   -41.55mA   -16.73mA
-833.3mV  -15.79mA   -33.74mA   -15.03mA
-772.7mV  -9.342mA   -19.74mA   -12.19mA
-712.1mV  -6.927mA   -10.35mA   -9.702mA
-621.2mV  -4.26mA    -3.894mA   -6.224mA
-409.1mV  -336.9uA   -288.9uA   -618.6uA
1.5V      1.518nA    2.298uA    269.6pA
[Ramp]
dV/dt_f   0.450816/0.21619172n   0.398992/0.36026706n   0.486/0.15859638n
dV/dt_r 0.45458752/0.21204457n 0.40934344/0.33876801n 0.48679424/0.15603352n
R_load = 50
[Rising Waveform]
R_fixture = 50
V_fixture = 1.5
V_fixture_min = 1.35
V_fixture_max = 1.65
0s        937.3mV    852.6mV    1.043V
112.1ps   938.8mV    854.5mV    1.056V
198.2ps   953.5mV    853.1mV    1.298V
267.7ps   1.071V     853.7mV    1.536V
357.2ps   1.272V     915.3mV    1.63V
428ps     1.418V     1.001V     1.645V
483.1ps   1.47V      1.067V     1.648V
616.1ps   1.497V     1.229V     1.65V
745.3ps   1.5V       1.33V      1.65V
1.667ns   1.5V       1.35V      1.65V
[Rising Waveform]
R_fixture = 50
V_fixture = 0
V_fixture_min = 0
V_fixture_max = 0
8.2ps     0V         0V         0V
119.2ps   2.05mV     2.427mV    9.532mV
205.9ps   0V         0V         264.2mV
269.2ps   102.6mV    0V         492.1mV
356.3ps   297.9mV    12.87mV    588.7mV
430ps     471.5mV    97.38mV    603.8mV
478.6ps   529.2mV    166.8mV    606.6mV
638.4ps   564.5mV    372.5mV    608.3mV
777.2ps   566.2mV    489.6mV    608.4mV
1.675ns   566.4mV    508.1mV    608.4mV
[Falling Waveform]
R_fixture = 50
V_fixture = 1.5
V_fixture_min = 1.35
V_fixture_max = 1.65
0s        1.499V     1.349V     1.649V
114.8ps   1.498V     1.347V     1.635V
192.1ps   1.495V     1.348V     1.424V
263.6ps   1.389V     1.348V     1.165V
355.3ps   1.184V     1.317V     1.062V
422ps     1.033V     1.255V     1.048V
469.8ps   975.9mV    1.197V     1.044V
647.8ps   937.8mV    985.9mV    1.042V
776.6ps   936.7mV    875.5mV    1.042V
1.667ns   936.6mV    851.7mV    1.042V
[Falling Waveform]
R_fixture = 50
V_fixture = 0
V_fixture_min = 0
V_fixture_max = 0
8.2ps     565.5mV    507.7mV    607.8mV
130ps     563.8mV    505.6mV    578.2mV
196.6ps   557.8mV    506.5mV    370.5mV
262.4ps   456.6mV    506.7mV    125.7mV
356.4ps   235.4mV    467.2mV    18.02mV
421ps     89.24mV    397.3mV    5.035mV
480.9ps   27.87mV    322.7mV    0V
636.2ps   0V         127.1mV    0V
778ps     0V         15.95mV    0V
1.675ns   0V         0V         0V
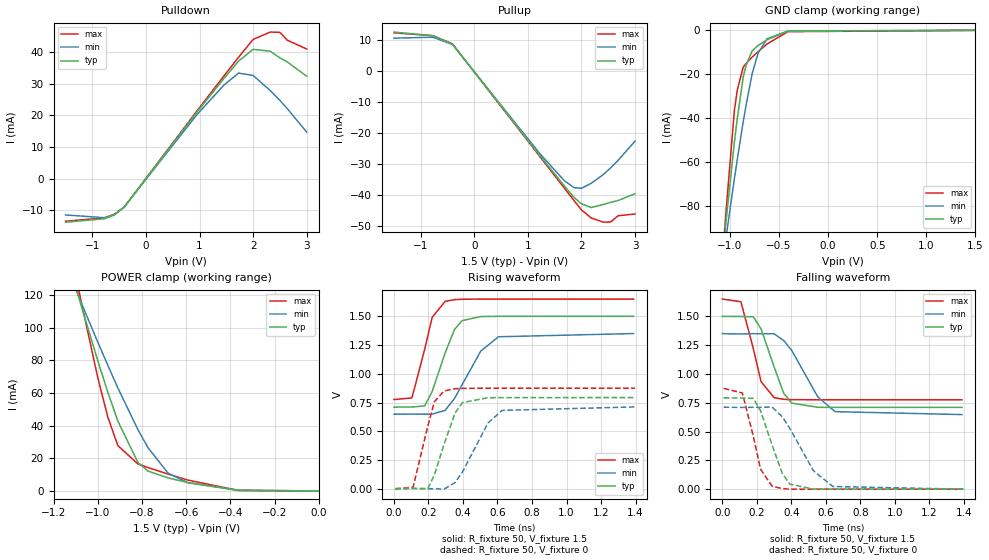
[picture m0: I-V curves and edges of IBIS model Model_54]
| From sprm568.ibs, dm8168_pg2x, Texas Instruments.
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| Model based on original model for BSHTLTCSCDVGPBFZ
|   Sub model SLOW_9MA_10PER_1P5
[model]   Model_54
|[Description]  [1.5V-3-STATE-X-SLOW:9MA, IND, 10%]
|   Slow slew rate (SR[1:0] = "01"), 0.88 * RExt = 1.125 * Iout
|   (I[2:0] = "100"), 9mA nominal with Rext = 50R, ,Industrial
|   temperature range (-40C to 125C, 25C nominal),10% power supply
|   tolerance
|[Input Load]
|[Output Drive] SLOW:9MA
|Voltage   1.5V
|Mode   3-STATE
Model_type   3-state
Polarity   Non-Inverting
Enable   Active-Low
Cref =  15.0000pF
Rref =  100.0000M
Vref =  0V
Vmeas =  0.75
C_comp   1.5249p   1.4275p   1.6205p
[Model Spec]
[Temperature Range]   25   125   -40
[Voltage Range]   1.5   1.35   1.65
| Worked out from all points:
|   slope of the pulldown table from 0 to 0.225 V, typ, clamps not added: 44.4 ohm
|   slope of the pullup table from 0 to 0.225 V, typ, clamps not added: 44.4 ohm
|   GND clamp passes 1 mA (typ) near -0.47 V on its own axis
|   POWER clamp passes 1 mA (typ) near -0.42 V on its own axis
|   rising waveform, R_fixture 50, V_fixture 1.5: 20-80 % time 109ps typ, 158ps min, 79ps max; typ from 0.71 V to 1.5 V
|   rising waveform, R_fixture 50, V_fixture 0: 20-80 % time 104ps typ, 148ps min, 76.1ps max; typ from 0 V to 0.793 V
|   falling waveform, R_fixture 50, V_fixture 1.5: 20-80 % time 109ps typ, 160ps min, 78.7ps max; typ from 1.5 V to 0.709 V
|   falling waveform, R_fixture 50, V_fixture 0: 20-80 % time 108ps typ, 161ps min, 76.5ps max; typ from 0.792 V to 0 V
[POWER_clamp]
-1.5V     321.6mA    260.6mA    415.8mA
-1.091V   121.1mA    120.8mA    126.6mA
-1.076V   114.1mA    115.8mA    116.8mA
-1V       79.88mA    91.3mA     69.56mA
-954.5mV  60.58mA    77.05mA    45.34mA
-909.1mV  42.84mA    63.2mA     27.8mA
-818.2mV  17.47mA    37.6mA     16.51mA
-772.7mV  12.19mA    26.53mA    14.33mA
-681.8mV  7.985mA    10.89mA    10.33mA
-590.9mV  5.092mA    4.952mA    6.596mA
-363.6mV  298.9uA    465.6uA    298.1uA
0V        1.518nA    23.05nA    396.5pA
[Pulldown]
-1.5V     -13.72mA   -11.44mA   -13.42mA
-772.7mV  -12.63mA   -12.3mA    -12.35mA
-590.9mV  -11.43mA   -11.4mA    -11.21mA
-409.1mV  -9.05mA    -8.969mA   -9.02mA
954.5mV   21.1mA     20.29mA    21.44mA
1.455V    31.62mA    29.53mA    32.42mA
1.727V    37.09mA    33.33mA    38.3mA
2V        40.81mA    32.58mA    43.95mA
2.318V    40.22mA    27.84mA    46.26mA
2.5V      38.13mA    24.69mA    46.18mA
2.636V    36.84mA    22.13mA    43.72mA
3V        32.34mA    14.69mA    40.92mA
[Pullup]
-1.5V     12.66mA    10.7mA     12.43mA
-772.7mV  11.49mA    11.01mA    11.49mA
-409.1mV  8.835mA    8.685mA    8.877mA
1.227V    -27.25mA   -26.63mA   -27.57mA
1.682V    -37mA      -35.33mA   -37.72mA
1.864V    -40.74mA   -37.55mA   -41.76mA
2V        -42.75mA   -37.75mA   -44.71mA
2.182V    -43.95mA   -36.14mA   -47.32mA
2.409V    -42.96mA   -33.3mA    -48.69mA
2.545V    -42.29mA   -31.14mA   -48.64mA
2.682V    -41.72mA   -28.75mA   -46.62mA
3V        -39.5mA    -22.54mA   -46.04mA
[GND_clamp]
-1.5V     -310mA     -250.5mA   -402.4mA
-1.076V   -103.5mA   -106.1mA   -105.2mA
-1.045V   -89.74mA   -96.32mA   -85.93mA
-954.5mV  -51.19mA   -67.85mA   -36.85mA
-924.2mV  -40.06mA   -58.84mA   -27.27mA
-863.6mV  -21.23mA   -41.55mA   -16.73mA
-833.3mV  -15.79mA   -33.74mA   -15.03mA
-772.7mV  -9.342mA   -19.74mA   -12.19mA
-712.1mV  -6.927mA   -10.35mA   -9.702mA
-621.2mV  -4.26mA    -3.894mA   -6.224mA
-409.1mV  -336.9uA   -288.9uA   -618.6uA
1.5V      1.518nA    2.298uA    269.6pA
[Ramp]
dV/dt_f   0.632712/0.15852514n   0.563032/0.24472839n   0.699824/0.11998509n
dV/dt_r 0.63898296/0.15259227n 0.57522672/0.22902544n 0.70168392/0.11536384n
R_load = 50
[Rising Waveform]
R_fixture = 50
V_fixture = 1.5
V_fixture_min = 1.35
V_fixture_max = 1.65
0s        709.9mV    647.9mV    775.6mV
104.5ps   711.3mV    649.9mV    790.3mV
177.8ps   720mV      648.1mV    1.21V
221.3ps   843.6mV    649.1mV    1.49V
296.3ps   1.179V     681.2mV    1.63V
350.4ps   1.384V     783.4mV    1.645V
394.2ps   1.462V     902.6mV    1.648V
503.5ps   1.498V     1.198V     1.65V
606ps     1.5V       1.322V     1.65V
1.389ns   1.5V       1.35V      1.65V
[Rising Waveform]
R_fixture = 50
V_fixture = 0
V_fixture_min = 0
V_fixture_max = 0
8.2ps     0V         0V         0V
111.1ps   2.126mV    2.275mV    13.27mV
196.1ps   0V         0V         543.9mV
234.6ps   119.8mV    0V         757.3mV
289.8ps   383.7mV    -3.94mV    849.7mV
353.8ps   658.1mV    52.75mV    870mV
396.9ps   749.3mV    145.3mV    873mV
545.2ps   791.8mV    572.5mV    874.5mV
627.6ps   792.7mV    681.6mV    874.6mV
1.397ns   793mV      711.7mV    874.6mV
[Falling Waveform]
R_fixture = 50
V_fixture = 1.5
V_fixture_min = 1.35
V_fixture_max = 1.65
0s        1.499V     1.349V     1.649V
108ps     1.498V     1.346V     1.626V
180.1ps   1.495V     1.349V     1.219V
224.8ps   1.39V      1.348V     932.5mV
300.8ps   1.059V     1.348V     793.5mV
356.6ps   830.5mV    1.288V     779.3mV
402.1ps   746.6mV    1.204V     776.5mV
553.6ps   709.9mV    800.4mV    775.5mV
653.3ps   709.4mV    672.4mV    775.4mV
1.389ns   709.2mV    647mV      775.3mV
[Falling Waveform]
R_fixture = 50
V_fixture = 0
V_fixture_min = 0
V_fixture_max = 0
8.2ps     792.1mV    711mV      874mV
116.5ps   790.3mV    708.9mV    834.3mV
179.3ps   788.1mV    710.5mV    463.3mV
222.2ps   679mV      710.1mV    172.5mV
289ps     381.5mV    711.7mV    25.11mV
348.5ps   134.4mV    627.2mV    5.117mV
391.8ps   43.61mV    526.1mV    0V
527.9ps   0V         160.3mV    0V
641.1ps   0V         22.89mV    0V
1.397ns   0V         0V         0V
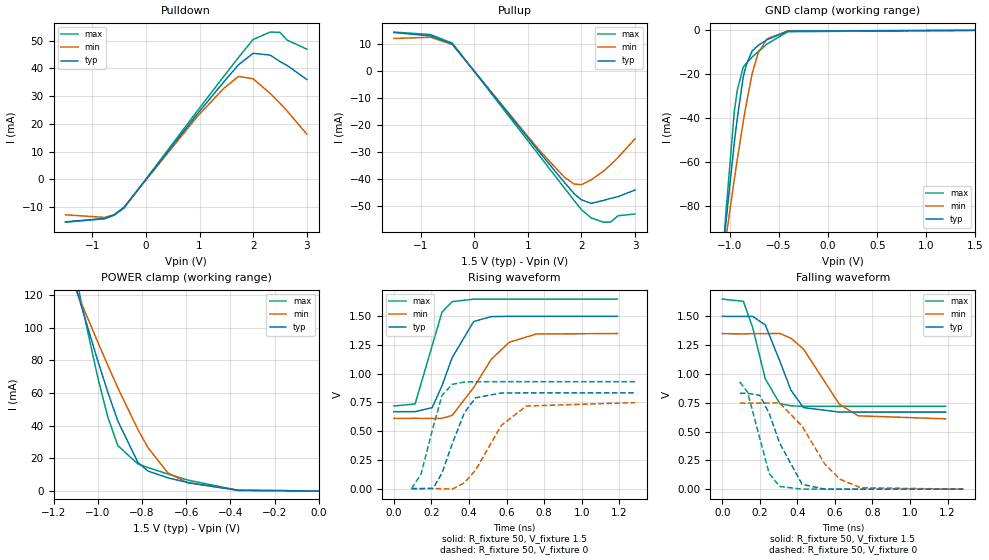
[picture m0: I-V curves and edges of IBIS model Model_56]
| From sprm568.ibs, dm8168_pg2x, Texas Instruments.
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| Model based on original model for BSHTLTCSCDVGPBFZ
|   Sub model SLOWEST_10MA_10PER_1P5
[model]   Model_56
|[Description]  [1.5V-3-STATE-X-SLOWEST:10MA, IND, 10%]
|   Slowest slew rate (SR[1:0] = "11"), 0.80 * RExt = 1.250 * Iout
|   (I[2:0] = "101"), 10mA nominal with Rext = 50R, ,Industrial
|   temperature range (-40C to 125C, 25C nominal),10% power supply
|   tolerance
|[Input Load]
|[Output Drive] SLOWEST:10MA
|Voltage   1.5V
|Mode   3-STATE
Model_type   3-state
Polarity   Non-Inverting
Enable   Active-Low
Cref =  15.0000pF
Rref =  100.0000M
Vref =  0V
Vmeas =  0.75
C_comp   1.5249p   1.4275p   1.6205p
[Model Spec]
[Temperature Range]   25   125   -40
[Voltage Range]   1.5   1.35   1.65
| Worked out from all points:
|   slope of the pulldown table from 0 to 0.225 V, typ, clamps not added: 39.9 ohm
|   slope of the pullup table from 0 to 0.225 V, typ, clamps not added: 39.8 ohm
|   GND clamp passes 1 mA (typ) near -0.47 V on its own axis
|   POWER clamp passes 1 mA (typ) near -0.42 V on its own axis
|   rising waveform, R_fixture 50, V_fixture 1.5: 20-80 % time 123ps typ, 180ps min, 90.4ps max; typ from 0.669 V to 1.5 V
|   rising waveform, R_fixture 50, V_fixture 0: 20-80 % time 115ps typ, 168ps min, 88ps max; typ from 0 V to 0.833 V
|   falling waveform, R_fixture 50, V_fixture 1.5: 20-80 % time 117ps typ, 176ps min, 87.8ps max; typ from 1.5 V to 0.669 V
|   falling waveform, R_fixture 50, V_fixture 0: 20-80 % time 118ps typ, 180ps min, 86ps max; typ from 0.833 V to 0 V
[POWER_clamp]
-1.5V     321.6mA    260.6mA    415.8mA
-1.091V   121.1mA    120.8mA    126.6mA
-1.076V   114.1mA    115.8mA    116.8mA
-1V       79.88mA    91.3mA     69.56mA
-954.5mV  60.58mA    77.05mA    45.34mA
-909.1mV  42.84mA    63.2mA     27.8mA
-818.2mV  17.47mA    37.6mA     16.51mA
-772.7mV  12.19mA    26.53mA    14.33mA
-681.8mV  7.985mA    10.89mA    10.33mA
-590.9mV  5.092mA    4.952mA    6.596mA
-363.6mV  298.9uA    465.6uA    298.1uA
0V        1.518nA    23.05nA    396.5pA
[Pulldown]
-1.5V     -15.29mA   -12.74mA   -15.41mA
-772.7mV  -14.07mA   -13.69mA   -14.18mA
-590.9mV  -12.73mA   -12.7mA    -12.87mA
-409.1mV  -10.08mA   -9.986mA   -10.35mA
954.5mV   23.5mA     22.59mA    24.6mA
1.455V    35.23mA    32.88mA    37.21mA
1.727V    41.32mA    37.11mA    43.96mA
2V        45.47mA    36.28mA    50.45mA
2.318V    44.82mA    31mA       53.11mA
2.5V      42.49mA    27.5mA     53.03mA
2.636V    41.06mA    24.65mA    50.21mA
3V        36.04mA    16.36mA    46.99mA
[Pullup]
-1.5V     14.1mA     11.91mA    14.27mA
-818.2mV  12.87mA    12.36mA    13.38mA
-409.1mV  9.843mA    9.671mA    10.19mA
1.227V    -30.35mA   -29.65mA   -31.65mA
1.682V    -41.22mA   -39.34mA   -43.29mA
1.864V    -45.39mA   -41.81mA   -47.93mA
2V        -47.64mA   -42.04mA   -51.31mA
2.182V    -48.97mA   -40.26mA   -54.32mA
2.409V    -47.87mA   -37.09mA   -55.9mA
2.545V    -47.12mA   -34.69mA   -55.85mA
2.682V    -46.49mA   -32.02mA   -53.53mA
3V        -44.02mA   -25.11mA   -52.86mA
[GND_clamp]
-1.5V     -310mA     -250.5mA   -402.4mA
-1.076V   -103.5mA   -106.1mA   -105.2mA
-1.045V   -89.74mA   -96.32mA   -85.93mA
-954.5mV  -51.19mA   -67.85mA   -36.85mA
-924.2mV  -40.06mA   -58.84mA   -27.27mA
-863.6mV  -21.23mA   -41.55mA   -16.73mA
-833.3mV  -15.79mA   -33.74mA   -15.03mA
-772.7mV  -9.342mA   -19.74mA   -12.19mA
-712.1mV  -6.927mA   -10.35mA   -9.702mA
-621.2mV  -4.26mA    -3.894mA   -6.224mA
-409.1mV  -336.9uA   -288.9uA   -618.6uA
1.5V      1.518nA    2.298uA    269.6pA
[Ramp]
dV/dt_f   0.665504/0.17255533n   0.59284/0.26964328n   0.74524/0.12912092n
dV/dt_r 0.67145792/0.17522198n 0.60391592/0.26496747n 0.74732944/0.12850822n
R_load = 50
[Rising Waveform]
R_fixture = 50
V_fixture = 1.5
V_fixture_min = 1.35
V_fixture_max = 1.65
0s        669.2mV    611.1mV    718.8mV
112.8ps   669.8mV    612.2mV    737mV
203.7ps   704.6mV    611.1mV    1.244V
255.9ps   895.3mV    611.6mV    1.536V
310.1ps   1.14V      637.5mV    1.628V
424.8ps   1.455V     880.2mV    1.649V
518.4ps   1.497V     1.125V     1.65V
614.1ps   1.5V       1.274V     1.65V
758.1ps   1.5V       1.346V     1.65V
1.19ns    1.5V       1.35V      1.65V
[Rising Waveform]
R_fixture = 50
V_fixture = 0
V_fixture_min = 0
V_fixture_max = 0
93.25ps   0V         0V         0V
144.4ps   0V         0V         125.5mV
208.9ps   3.52mV     0V         536.5mV
255.9ps   134.6mV    0V         810mV
309.8ps   386.9mV    -4.885mV   908.1mV
375.1ps   660mV      49.72mV    927.6mV
435.4ps   791.1mV    162.6mV    930.4mV
571.9ps   832.3mV    550.3mV    931.1mV
705.1ps   833.3mV    718.9mV    931.2mV
1.284ns   833.5mV    748.2mV    931.2mV
[Falling Waveform]
R_fixture = 50
V_fixture = 1.5
V_fixture_min = 1.35
V_fixture_max = 1.65
0s        1.499V     1.349V     1.649V
112.5ps   1.498V     1.347V     1.629V
161.6ps   1.499V     1.349V     1.405V
229.1ps   1.425V     1.349V     957.2mV
306.6ps   1.111V     1.351V     742mV
366.1ps   857.2mV    1.309V     722.6mV
432.8ps   707.5mV    1.215V     719.3mV
622.9ps   668.8mV    738.2mV    718.6mV
723.6ps   668.6mV    636.2mV    718.6mV
1.19ns    668.5mV    610.1mV    718.6mV
[Falling Waveform]
R_fixture = 50
V_fixture = 0
V_fixture_min = 0
V_fixture_max = 0
93.25ps   832.6mV    747.5mV    930.3mV
134.6ps   831.4mV    746.8mV    842.5mV
199.9ps   814mV      747.3mV    442.6mV
249.8ps   659.2mV    747.1mV    136.3mV
305.2ps   401.2mV    749mV      24.02mV
425.1ps   41.93mV    546.7mV    0V
546.6ps   0V         216.7mV    0V
628.7ps   0V         84.8mV     0V
736.5ps   0V         12.81mV    0V
1.284ns   0V         0V         0V
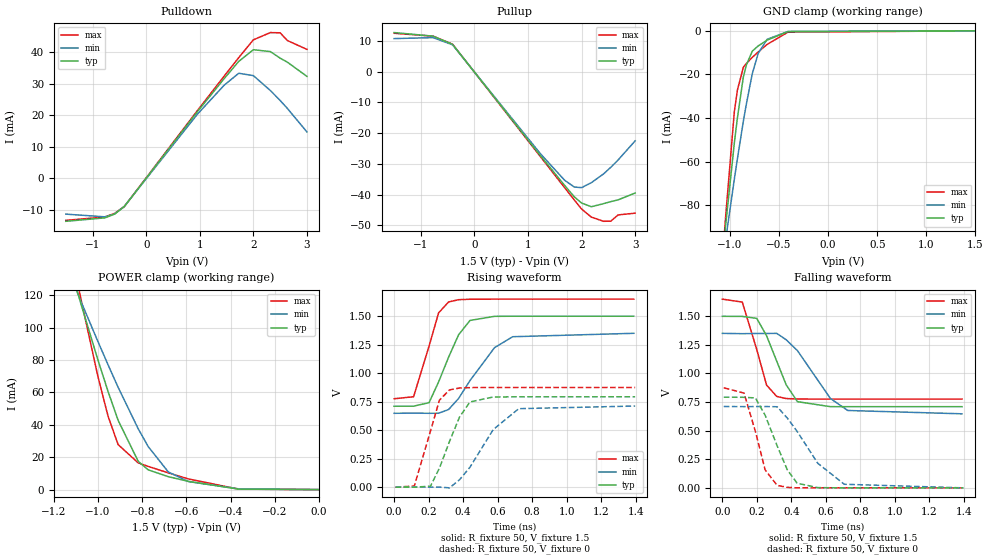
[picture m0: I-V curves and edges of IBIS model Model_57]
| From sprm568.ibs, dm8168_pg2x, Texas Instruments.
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| Model based on original model for BSHTLTCSCDVGPBFZ
|   Sub model SLOWEST_9MA_10PER_1P5
[model]   Model_57
|[Description]  [1.5V-3-STATE-X-SLOWEST:9MA, IND, 10%]
|   Slowest slew rate (SR[1:0] = "11"), 0.88 * RExt = 1.125 * Iout
|   (I[2:0] = "100"), 9mA nominal with Rext = 50R, ,Industrial
|   temperature range (-40C to 125C, 25C nominal),10% power supply
|   tolerance
|[Input Load]
|[Output Drive] SLOWEST:9MA
|Voltage   1.5V
|Mode   3-STATE
Model_type   3-state
Polarity   Non-Inverting
Enable   Active-Low
Cref =  15.0000pF
Rref =  100.0000M
Vref =  0V
Vmeas =  0.75
C_comp   1.5249p   1.4275p   1.6205p
[Model Spec]
[Temperature Range]   25   125   -40
[Voltage Range]   1.5   1.35   1.65
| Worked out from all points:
|   slope of the pulldown table from 0 to 0.225 V, typ, clamps not added: 44.4 ohm
|   slope of the pullup table from 0 to 0.225 V, typ, clamps not added: 44.4 ohm
|   GND clamp passes 1 mA (typ) near -0.47 V on its own axis
|   POWER clamp passes 1 mA (typ) near -0.42 V on its own axis
|   rising waveform, R_fixture 50, V_fixture 1.5: 20-80 % time 132ps typ, 195ps min, 93.6ps max; typ from 0.71 V to 1.5 V
|   rising waveform, R_fixture 50, V_fixture 0: 20-80 % time 125ps typ, 186ps min, 91ps max; typ from 0 V to 0.793 V
|   falling waveform, R_fixture 50, V_fixture 1.5: 20-80 % time 129ps typ, 192ps min, 90.7ps max; typ from 1.5 V to 0.709 V
|   falling waveform, R_fixture 50, V_fixture 0: 20-80 % time 128ps typ, 197ps min, 88.5ps max; typ from 0.793 V to 0 V
[POWER_clamp]
-1.5V     321.6mA    260.6mA    415.8mA
-1.091V   121.1mA    120.8mA    126.6mA
-1.076V   114.1mA    115.8mA    116.8mA
-1V       79.88mA    91.3mA     69.56mA
-954.5mV  60.58mA    77.05mA    45.34mA
-909.1mV  42.84mA    63.2mA     27.8mA
-818.2mV  17.47mA    37.6mA     16.51mA
-772.7mV  12.19mA    26.53mA    14.33mA
-681.8mV  7.985mA    10.89mA    10.33mA
-590.9mV  5.092mA    4.952mA    6.596mA
-363.6mV  298.9uA    465.6uA    298.1uA
0V        1.518nA    23.05nA    396.5pA
[Pulldown]
-1.5V     -13.72mA   -11.44mA   -13.42mA
-772.7mV  -12.63mA   -12.3mA    -12.35mA
-590.9mV  -11.43mA   -11.4mA    -11.21mA
-409.1mV  -9.05mA    -8.969mA   -9.02mA
954.5mV   21.1mA     20.29mA    21.44mA
1.455V    31.62mA    29.53mA    32.42mA
1.727V    37.09mA    33.33mA    38.3mA
2V        40.81mA    32.58mA    43.95mA
2.318V    40.22mA    27.84mA    46.26mA
2.5V      38.13mA    24.69mA    46.18mA
2.636V    36.84mA    22.13mA    43.72mA
3V        32.34mA    14.69mA    40.92mA
[Pullup]
-1.5V     12.66mA    10.7mA     12.43mA
-772.7mV  11.49mA    11.01mA    11.49mA
-409.1mV  8.835mA    8.685mA    8.877mA
1.227V    -27.25mA   -26.63mA   -27.57mA
1.682V    -37mA      -35.33mA   -37.72mA
1.864V    -40.74mA   -37.55mA   -41.76mA
2V        -42.75mA   -37.75mA   -44.71mA
2.182V    -43.95mA   -36.14mA   -47.32mA
2.409V    -42.96mA   -33.3mA    -48.69mA
2.545V    -42.29mA   -31.14mA   -48.64mA
2.682V    -41.72mA   -28.75mA   -46.62mA
3V        -39.5mA    -22.54mA   -46.04mA
[GND_clamp]
-1.5V     -310mA     -250.5mA   -402.4mA
-1.076V   -103.5mA   -106.1mA   -105.2mA
-1.045V   -89.74mA   -96.32mA   -85.93mA
-954.5mV  -51.19mA   -67.85mA   -36.85mA
-924.2mV  -40.06mA   -58.84mA   -27.27mA
-863.6mV  -21.23mA   -41.55mA   -16.73mA
-833.3mV  -15.79mA   -33.74mA   -15.03mA
-772.7mV  -9.342mA   -19.74mA   -12.19mA
-712.1mV  -6.927mA   -10.35mA   -9.702mA
-621.2mV  -4.26mA    -3.894mA   -6.224mA
-409.1mV  -336.9uA   -288.9uA   -618.6uA
1.5V      1.518nA    2.298uA    269.6pA
[Ramp]
dV/dt_f   0.632872/0.18546709n   0.563352/0.29962549n   0.699824/0.13417336n
dV/dt_r 0.63880616/0.18547635n 0.57470912/0.28429446n 0.70137144/0.13333905n
R_load = 50
[Rising Waveform]
R_fixture = 50
V_fixture = 1.5
V_fixture_min = 1.35
V_fixture_max = 1.65
0s        709.9mV    648mV      775.6mV
112.8ps   710.6mV    649.2mV    793.2mV
202.4ps   741.2mV    648mV      1.237V
257.8ps   923.1mV    648.5mV    1.529V
315.4ps   1.139V     680.8mV    1.625V
373.4ps   1.336V     777.4mV    1.645V
439.8ps   1.463V     935.3mV    1.649V
582ps     1.499V     1.224V     1.65V
687.1ps   1.5V       1.32V      1.65V
1.389ns   1.5V       1.35V      1.65V
[Rising Waveform]
R_fixture = 50
V_fixture = 0
V_fixture_min = 0
V_fixture_max = 0
8.2ps     0V         0V         0V
117.1ps   0V         0V         9.37mV
210.7ps   8.167mV    0V         492.1mV
262.9ps   167.5mV    0V         764mV
321.1ps   401.2mV    -6.416mV   853.1mV
379.5ps   616.3mV    65.31mV    870.1mV
439.5ps   747.4mV    174.5mV    873.6mV
574.5ps   791.3mV    505.6mV    874.5mV
722.5ps   792.8mV    688.6mV    874.6mV
1.397ns   793mV      711.7mV    874.6mV
[Falling Waveform]
R_fixture = 50
V_fixture = 1.5
V_fixture_min = 1.35
V_fixture_max = 1.65
0s        1.499V     1.35V      1.649V
115.6ps   1.498V     1.347V     1.623V
199.3ps   1.481V     1.349V     1.209V
256.3ps   1.329V     1.349V     898.1mV
315.2ps   1.107V     1.35V      798.6mV
370.1ps   900mV      1.294V     780.4mV
435.3ps   753mV      1.199V     776.3mV
626.3ps   709.6mV    781.1mV    775.4mV
726.7ps   709.3mV    676mV      775.4mV
1.389ns   709.2mV    647mV      775.3mV
[Falling Waveform]
R_fixture = 50
V_fixture = 0
V_fixture_min = 0
V_fixture_max = 0
8.2ps     792.6mV    710.8mV    874mV
125.7ps   791.1mV    709.7mV    828.3mV
191.6ps   785.7mV    710.4mV    491.9mV
248.3ps   633.6mV    710.6mV    156.2mV
317.8ps   366.6mV    708.6mV    21.34mV
376.8ps   156.6mV    609mV      4.518mV
433.6ps   40.51mV    493.1mV    0V
553.2ps   2.004mV    214.5mV    0V
707ps     0V         31.37mV    0V
1.397ns   0V         0V         0V
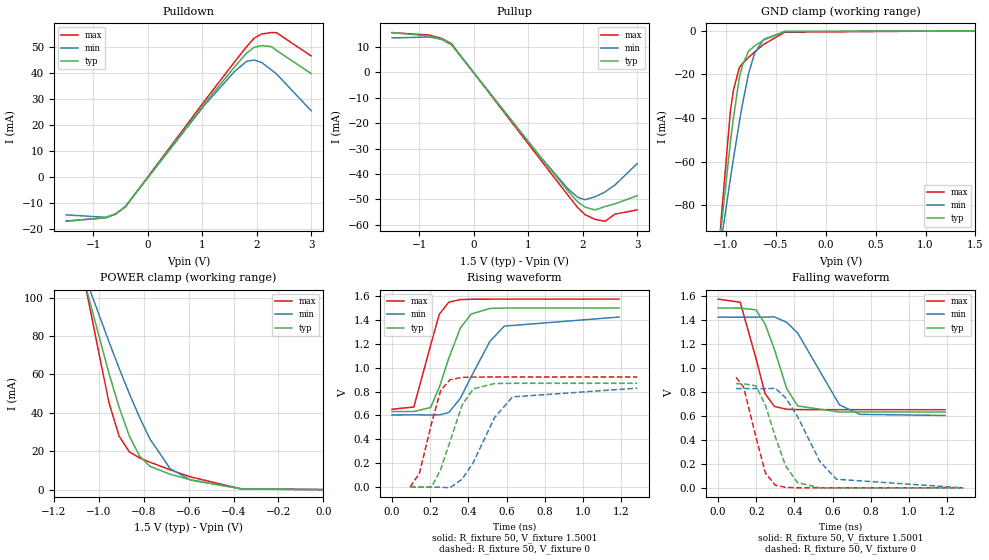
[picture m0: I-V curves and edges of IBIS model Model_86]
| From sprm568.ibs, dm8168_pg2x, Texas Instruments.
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| Model based on original model for BSHTLTCSCDVGPBFZ
|   Sub model SLOWEST_11MA_5PER_1P5
[model]   Model_86
|[Description]  [1.5V-3-STATE-X-SLOWEST:11MA, IND, 5%]
|   Slowest slew rate (SR[1:0] = "11"), 0.73 * RExt = 1.325 * Iout
|   (I[2:0] = "110"), 11mA nominal with Rext = 50R, ,Industrial
|   temperature range (-40C to 125C, 25C nominal),5% power supply
|   tolerance
|[Input Load]
|[Output Drive] SLOWEST:11MA
|Voltage   1.5V
|Mode   3-STATE
Model_type   3-state
Polarity   Non-Inverting
Enable   Active-Low
Cref =  15.0000pF
Rref =  100.0000M
Vref =  0V
Vmeas =  0.75005
C_comp   1.5249p   1.4275p   1.6205p
[Model Spec]
[Temperature Range]   25   125   -40
[Voltage Range]   1.5   1.425   1.575
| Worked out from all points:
|   slope of the pulldown table from 0 to 0.225 V, typ, clamps not added: 36.2 ohm
|   slope of the pullup table from 0 to 0.225 V, typ, clamps not added: 36.1 ohm
|   GND clamp passes 1 mA (typ) near -0.47 V on its own axis
|   POWER clamp passes 1 mA (typ) near -0.42 V on its own axis
|   rising waveform, R_fixture 50, V_fixture 1.5001: 20-80 % time 115ps typ, 165ps min, 87.1ps max; typ from 0.633 V to 1.5 V
|   rising waveform, R_fixture 50, V_fixture 0: 20-80 % time 109ps typ, 161ps min, 85ps max; typ from 0 V to 0.87 V
|   falling waveform, R_fixture 50, V_fixture 1.5001: 20-80 % time 110ps typ, 168ps min, 84.4ps max; typ from 1.5 V to 0.632 V
|   falling waveform, R_fixture 50, V_fixture 0: 20-80 % time 110ps typ, 166ps min, 83.6ps max; typ from 0.869 V to 0 V
[POWER_clamp]
-1.5V     321.7mA    260.6mA    415.9mA
-1.076V   114.2mA    115.8mA    116.9mA
-1.061V   107.2mA    110.9mA    107.1mA
-954.6mV  60.59mA    77.06mA    45.35mA
-909.2mV  42.85mA    63.21mA    27.81mA
-863.7mV  27.9mA     49.99mA    19.69mA
-818.2mV  17.49mA    37.63mA    16.52mA
-772.8mV  12.19mA    26.53mA    14.33mA
-681.9mV  7.985mA    10.89mA    10.33mA
-590.9mV  5.094mA    4.955mA    6.6mA
-363.7mV  298.5uA    465.2uA    297.6uA
0V        1.518nA    24.08nA    367.8pA
[Pulldown]
-1.5V     -16.86mA   -14.4mA    -16.76mA
-772.8mV  -15.51mA   -15.32mA   -15.47mA
-590.9mV  -14.04mA   -14.17mA   -14.06mA
-409.1mV  -11.11mA   -11.14mA   -11.31mA
1.046V    28.3mA     27.74mA    29.33mA
1.591V    42.23mA    40.49mA    44.13mA
1.818V    47.67mA    44.47mA    50.1mA
1.955V    49.8mA     44.93mA    53.33mA
2.091V    50.46mA    43.98mA    54.91mA
2.273V    50.06mA    41.13mA    55.45mA
2.364V    48.6mA     39.6mA     55.4mA
3V        39.74mA    25.5mA     46.51mA
[Pullup]
-1.5V     15.55mA    13.43mA    15.5mA
-818.2mV  14.19mA    13.81mA    14.58mA
-590.9mV  13.04mA    12.91mA    13.28mA
-409.1mV  10.85mA    10.77mA    11.13mA
1.227V    -33.46mA   -33.35mA   -34.46mA
1.727V    -46.61mA   -45.78mA   -48.31mA
1.909V    -51.03mA   -49.2mA    -53.23mA
2.046V    -53.04mA   -50.12mA   -56.04mA
2.227V    -54.15mA   -48.98mA   -57.84mA
2.409V    -52.79mA   -47.07mA   -58.6mA
2.591V    -51.74mA   -44.37mA   -55.8mA
3V        -48.54mA   -35.95mA   -54.13mA
[GND_clamp]
-1.5V     -310.1mA   -250.5mA   -402.5mA
-1.076V   -103.6mA   -106.2mA   -105.2mA
-1.046V   -89.81mA   -96.36mA   -86.02mA
-954.6mV  -51.22mA   -67.87mA   -36.88mA
-924.3mV  -40.08mA   -58.86mA   -27.29mA
-863.7mV  -21.24mA   -41.56mA   -16.73mA
-833.4mV  -15.8mA    -33.75mA   -15.03mA
-772.8mV  -9.345mA   -19.75mA   -12.19mA
-712.2mV  -6.928mA   -10.35mA   -9.704mA
-621.3mV  -4.261mA   -3.896mA   -6.225mA
-409.1mV  -337.1uA   -289.1uA   -618.9uA
1.5V      1.518nA    257.2nA    299pA
[Ramp]
dV/dt_f   0.694672/0.16816054n   0.65828/0.25005793n   0.738624/0.12339165n
dV/dt_r 0.70089704/0.17137771n 0.66949008/0.25047145n 0.74106456/0.12380034n
R_load = 50
[Rising Waveform]
R_fixture = 50
V_fixture = 1.5001
V_fixture_min = 1.425
V_fixture_max = 1.575
0s        633.2mV    604.5mV    652.6mV
113.9ps   633.4mV    605.3mV    671mV
201.8ps   666.5mV    604.3mV    1.188V
247.6ps   835.5mV    605.1mV    1.448V
297ps     1.079V     624.1mV    1.549V
358.2ps   1.334V     744mV      1.571V
414.5ps   1.45V      924.4mV    1.574V
513.5ps   1.497V     1.223V     1.575V
589ps     1.5V       1.349V     1.575V
1.19ns    1.5V       1.425V     1.575V
[Rising Waveform]
R_fixture = 50
V_fixture = 0
V_fixture_min = 0
V_fixture_max = 0
94.23ps   0V         0V         0V
143.3ps   0V         0V         115.2mV
206.7ps   0V         0V         532.8mV
254.4ps   145.8mV    0V         808.5mV
302.9ps   378.1mV    -6.513mV   898.9mV
366.6ps   685.8mV    66.08mV    919.1mV
425.2ps   822.8mV    204.7mV    921.8mV
536.9ps   867.8mV    581.4mV    922.4mV
631.2ps   869.4mV    755.8mV    922.5mV
1.285ns   869.7mV    828.9mV    922.5mV
[Falling Waveform]
R_fixture = 50
V_fixture = 1.5001
V_fixture_min = 1.425
V_fixture_max = 1.575
0s        1.5V       1.424V     1.574V
115.9ps   1.499V     1.423V     1.548V
198.4ps   1.485V     1.424V     1.08V
246.1ps   1.367V     1.424V     786.2mV
295.1ps   1.155V     1.426V     679.2mV
359.3ps   828.5mV    1.38V      655.4mV
416.9ps   683.1mV    1.292V     652.6mV
636.3ps   632.5mV    691.6mV    651.9mV
744.3ps   632.4mV    612.9mV    651.9mV
1.19ns    632.3mV    603.6mV    651.8mV
[Falling Waveform]
R_fixture = 50
V_fixture = 0
V_fixture_min = 0
V_fixture_max = 0
94.23ps   868.9mV    828.2mV    921.7mV
134ps     867.7mV    827.6mV    837.7mV
198.4ps   851.1mV    828.1mV    422.7mV
248.5ps   687mV      827.8mV    122.5mV
300.4ps   422.7mV    829.6mV    21.9mV
353.8ps   183.7mV    751.9mV    4.197mV
416.1ps   44.5mV     595.5mV    0V
532.7ps   0V         222.1mV    0V
620.3ps   0V         71.88mV    0V
1.285ns   0V         0V         0V
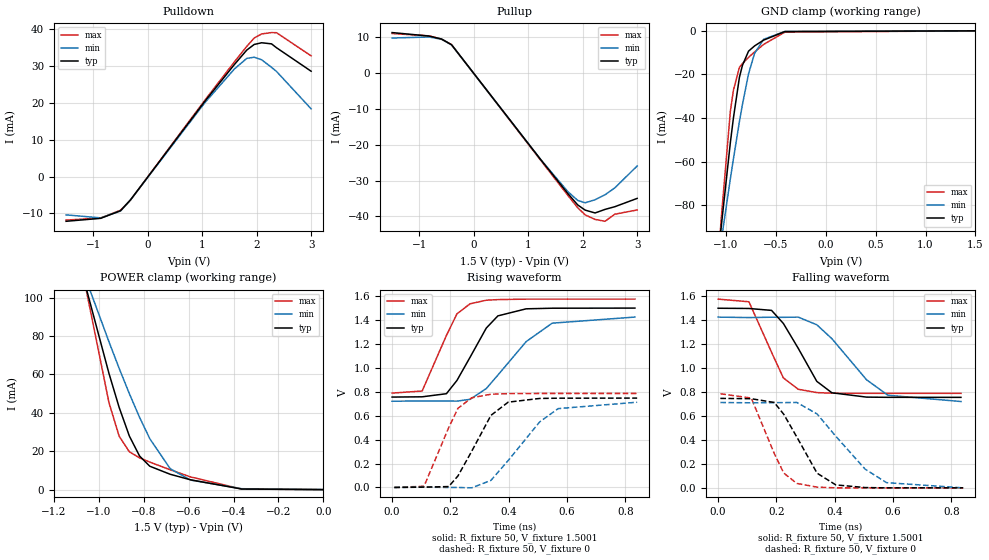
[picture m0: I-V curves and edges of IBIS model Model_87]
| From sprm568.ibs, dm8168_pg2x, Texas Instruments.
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| Model based on original model for BSHTLTCSCDVGPBFZ
|   Sub model FAST_8MA_5PER_1P5
[model]   Model_87
|[Description]  [1.5V-3-STATE-X-FAST:8MA, IND, 5%]
|   Fast slew rate (SR[1:0] = "10"), 1.00 * RExt = 1.000 * Iout
|   (I[2:0] = "011"), 8mA nominal with Rext = 50R, ,Industrial
|   temperature range (-40C to 125C, 25C nominal),5% power supply
|   tolerance
|[Input Load]
|[Output Drive] FAST:8MA
|Voltage   1.5V
|Mode   3-STATE
Model_type   3-state
Polarity   Non-Inverting
Enable   Active-Low
Cref =  15.0000pF
Rref =  100.0000M
Vref =  0V
Vmeas =  0.75005
C_comp   1.5249p   1.4275p   1.6205p
[Model Spec]
[Temperature Range]   25   125   -40
[Voltage Range]   1.5   1.425   1.575
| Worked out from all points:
|   slope of the pulldown table from 0 to 0.225 V, typ, clamps not added: 50.1 ohm
|   slope of the pullup table from 0 to 0.225 V, typ, clamps not added: 50.1 ohm
|   GND clamp passes 1 mA (typ) near -0.47 V on its own axis
|   POWER clamp passes 1 mA (typ) near -0.42 V on its own axis
|   rising waveform, R_fixture 50, V_fixture 1.5001: 20-80 % time 103ps typ, 154ps min, 78.2ps max; typ from 0.756 V to 1.5 V
|   rising waveform, R_fixture 50, V_fixture 0: 20-80 % time 99.2ps typ, 141ps min, 75.2ps max; typ from 0 V to 0.747 V
|   falling waveform, R_fixture 50, V_fixture 1.5001: 20-80 % time 104ps typ, 152ps min, 77.9ps max; typ from 1.5 V to 0.755 V
|   falling waveform, R_fixture 50, V_fixture 0: 20-80 % time 101ps typ, 153ps min, 75.5ps max; typ from 0.747 V to 0 V
[POWER_clamp]
-1.5V     321.7mA    260.6mA    415.9mA
-1.076V   114.2mA    115.8mA    116.9mA
-1.061V   107.2mA    110.9mA    107.1mA
-954.6mV  60.59mA    77.06mA    45.35mA
-909.2mV  42.85mA    63.21mA    27.81mA
-863.7mV  27.9mA     49.99mA    19.69mA
-818.2mV  17.49mA    37.63mA    16.52mA
-772.8mV  12.19mA    26.53mA    14.33mA
-681.9mV  7.985mA    10.89mA    10.33mA
-590.9mV  5.094mA    4.955mA    6.6mA
-363.7mV  298.5uA    465.2uA    297.6uA
0V        1.518nA    24.08nA    367.8pA
[Pulldown]
-1.5V     -12.15mA   -10.4mA    -11.83mA
-863.7mV  -11.34mA   -11.22mA   -11.25mA
-500mV    -9.267mA   -9.352mA   -9.148mA
-318.2mV  -6.354mA   -6.371mA   -6.385mA
1.046V    20.42mA    20.05mA    20.72mA
1.591V    30.47mA    29.26mA    31.18mA
1.818V    34.39mA    32.13mA    35.4mA
1.955V    35.92mA    32.45mA    37.67mA
2.091V    36.38mA    31.76mA    38.77mA
2.273V    36.08mA    29.69mA    39.15mA
2.364V    35.03mA    28.59mA    39.11mA
3V        28.64mA    18.41mA    32.82mA
[Pullup]
-1.5V     11.21mA    9.69mA     10.94mA
-818.2mV  10.23mA    9.978mA    10.29mA
-590.9mV  9.401mA    9.328mA    9.374mA
-409.1mV  7.828mA    7.781mA    7.859mA
1.227V    -24.14mA   -24.11mA   -24.35mA
1.727V    -33.63mA   -33.09mA   -34.13mA
1.909V    -36.81mA   -35.55mA   -37.6mA
2.046V    -38.25mA   -36.2mA    -39.57mA
2.227V    -39.04mA   -35.36mA   -40.83mA
2.409V    -38.05mA   -33.98mA   -41.36mA
2.591V    -37.29mA   -32.03mA   -39.38mA
3V        -34.98mA   -25.95mA   -38.2mA
[GND_clamp]
-1.5V     -310.1mA   -250.5mA   -402.5mA
-1.076V   -103.6mA   -106.2mA   -105.2mA
-1.046V   -89.81mA   -96.36mA   -86.02mA
-954.6mV  -51.22mA   -67.87mA   -36.88mA
-924.3mV  -40.08mA   -58.86mA   -27.29mA
-863.7mV  -21.24mA   -41.56mA   -16.73mA
-833.4mV  -15.8mA    -33.75mA   -15.03mA
-772.8mV  -9.345mA   -19.75mA   -12.19mA
-712.2mV  -6.928mA   -10.35mA   -9.704mA
-621.3mV  -4.261mA   -3.896mA   -6.225mA
-409.1mV  -337.1uA   -289.1uA   -618.9uA
1.5V      1.518nA    257.2nA    299pA
[Ramp]
dV/dt_f   0.596008/0.15568375n   0.563744/0.22543869n   0.629272/0.12060237n
dV/dt_r 0.60140536/0.14772322n 0.57539688/0.2137572n 0.63083936/0.1163411n
R_load = 50
[Rising Waveform]
R_fixture = 50
V_fixture = 1.5001
V_fixture_min = 1.425
V_fixture_max = 1.575
0s        755.9mV    721.1mV    789.3mV
103.1ps   758.1mV    723.6mV    806.4mV
186.4ps   784.1mV    722.6mV    1.271V
222.6ps   895.1mV    722mV      1.452V
267.6ps   1.089V     737mV      1.536V
323.2ps   1.333V     827.2mV    1.566V
363.1ps   1.435V     940mV      1.571V
460.2ps   1.494V     1.22V      1.575V
549.3ps   1.499V     1.374V     1.575V
833.3ps   1.5V       1.425V     1.575V
[Rising Waveform]
R_fixture = 50
V_fixture = 0
V_fixture_min = 0
V_fixture_max = 0
7.64ps    0V         0V         0V
109.6ps   2.689mV    2.536mV    10.35mV
194.2ps   7.541mV    0V         500mV
225.9ps   96.08mV    0V         661.8mV
273ps     302mV      -3.322mV   750mV
339.2ps   603mV      59.17mV    779.6mV
398.3ps   713.3mV    225mV      784.6mV
506.3ps   744.5mV    548.2mV    786.1mV
569.8ps   746.5mV    659.4mV    786.2mV
841ps     747.3mV    712.8mV    786.3mV
[Falling Waveform]
R_fixture = 50
V_fixture = 1.5001
V_fixture_min = 1.425
V_fixture_max = 1.575
0s        1.499V     1.425V     1.575V
105.7ps   1.497V     1.421V     1.553V
183.4ps   1.481V     1.424V     1.131V
223.9ps   1.372V     1.423V     917.5mV
274.8ps   1.165V     1.425V     822.9mV
338.6ps   888.9mV    1.361V     795mV
390.4ps   793.4mV    1.245V     790.1mV
509.3ps   757.3mV    902.2mV    788.7mV
582.7ps   755.6mV    772.8mV    788.6mV
833.3ps   755.2mV    720.6mV    788.5mV
[Falling Waveform]
R_fixture = 50
V_fixture = 0
V_fixture_min = 0
V_fixture_max = 0
7.64ps    746.6mV    712.3mV    785.4mV
113.8ps   744mV      709.8mV    749.3mV
192.7ps   712.4mV    711.4mV    286.1mV
225.3ps   613.8mV    711.4mV    123.2mV
270.1ps   424mV      712.8mV    37.01mV
339.7ps   122.2mV    616.5mV    6.1mV
403.8ps   24.79mV    430.6mV    0V
504.4ps   2.433mV    156.3mV    0V
578.1ps   0V         43.33mV    0V
841ps     0V         0V         0V
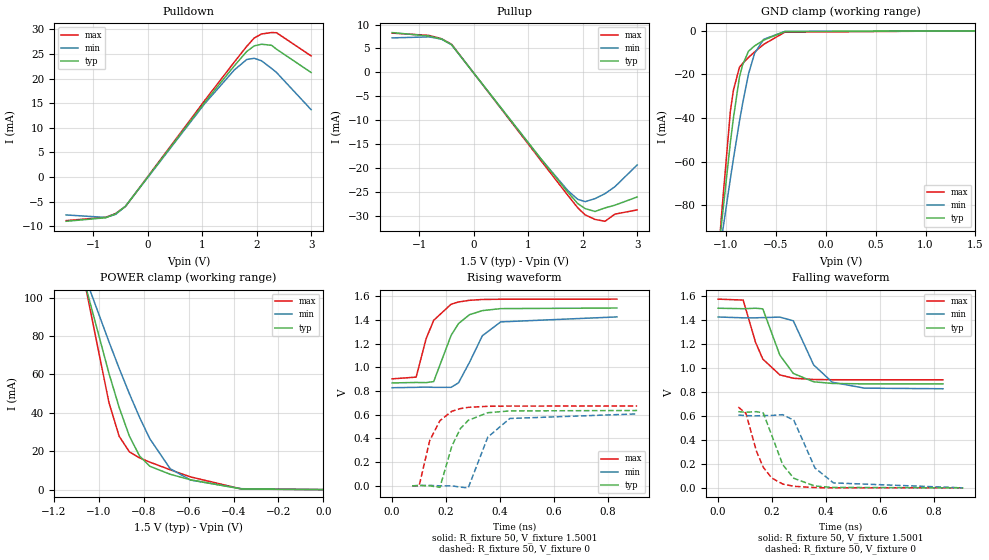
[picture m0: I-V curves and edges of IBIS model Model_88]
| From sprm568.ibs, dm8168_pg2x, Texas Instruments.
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| Model based on original model for BSHTLTCSCDVGPBFZ
|   Sub model FASTEST_6MA_5PER_1P5
[model]   Model_88
|[Description]  [1.5V-3-STATE-X-FASTEST:6MA, IND, 5%]
|   Fastest slew rate (SR[1:0] = "00"), 1.33 * RExt = 0.750 * Iout
|   (I[2:0] = "001"), 6mA nominal with Rext = 50R, ,Industrial
|   temperature range (-40C to 125C, 25C nominal),5% power supply
|   tolerance
|[Input Load]
|[Output Drive] FASTEST:6MA
|Voltage   1.5V
|Mode   3-STATE
Model_type   3-state
Polarity   Non-Inverting
Enable   Active-Low
Cref =  15.0000pF
Rref =  100.0000M
Vref =  0V
Vmeas =  0.75005
C_comp   1.5249p   1.4275p   1.6205p
[Model Spec]
[Temperature Range]   25   125   -40
[Voltage Range]   1.5   1.425   1.575
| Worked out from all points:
|   slope of the pulldown table from 0 to 0.225 V, typ, clamps not added: 67.5 ohm
|   slope of the pullup table from 0 to 0.225 V, typ, clamps not added: 67.5 ohm
|   GND clamp passes 1 mA (typ) near -0.47 V on its own axis
|   POWER clamp passes 1 mA (typ) near -0.42 V on its own axis
|   rising waveform, R_fixture 50, V_fixture 1.5001: 20-80 % time 68.5ps typ, 83.2ps min, 62.3ps max; typ from 0.868 V to 1.5 V
|   rising waveform, R_fixture 50, V_fixture 0: 20-80 % time 65.3ps typ, 70.5ps min, 60.4ps max; typ from 0 V to 0.636 V
|   falling waveform, R_fixture 50, V_fixture 1.5001: 20-80 % time 73.4ps typ, 84.4ps min, 66.4ps max; typ from 1.5 V to 0.867 V
|   falling waveform, R_fixture 50, V_fixture 0: 20-80 % time 69.6ps typ, 77.9ps min, 62.9ps max; typ from 0.636 V to 0 V
[POWER_clamp]
-1.5V     321.7mA    260.6mA    415.9mA
-1.076V   114.2mA    115.8mA    116.9mA
-1.061V   107.2mA    110.9mA    107.1mA
-954.6mV  60.59mA    77.06mA    45.35mA
-909.2mV  42.85mA    63.21mA    27.81mA
-863.7mV  27.9mA     49.99mA    19.69mA
-818.2mV  17.49mA    37.63mA    16.52mA
-772.8mV  12.19mA    26.53mA    14.33mA
-681.9mV  7.985mA    10.89mA    10.33mA
-590.9mV  5.094mA    4.955mA    6.6mA
-363.7mV  298.5uA    465.2uA    297.6uA
0V        1.518nA    24.08nA    367.8pA
[Pulldown]
-1.5V     -9.02mA    -7.73mA    -8.88mA
-772.8mV  -8.3mA     -8.227mA   -8.195mA
-590.9mV  -7.513mA   -7.616mA   -7.446mA
-409.1mV  -5.951mA   -5.987mA   -5.996mA
1.046V    15.16mA    14.91mA    15.55mA
1.591V    22.62mA    21.77mA    23.39mA
1.818V    25.52mA    23.89mA    26.56mA
1.955V    26.65mA    24.13mA    28.26mA
2.091V    26.99mA    23.61mA    29.08mA
2.273V    26.77mA    22.07mA    29.36mA
2.364V    25.98mA    21.25mA    29.33mA
3V        21.24mA    13.68mA    24.61mA
[Pullup]
-1.5V     8.32mA     7.21mA     8.21mA
-818.2mV  7.591mA    7.42mA     7.72mA
-590.9mV  6.976mA    6.937mA    7.031mA
-409.1mV  5.81mA     5.788mA    5.897mA
1.227V    -17.92mA   -17.93mA   -18.27mA
1.727V    -24.96mA   -24.61mA   -25.61mA
1.909V    -27.32mA   -26.44mA   -28.21mA
2.046V    -28.38mA   -26.92mA   -29.69mA
2.227V    -28.97mA   -26.29mA   -30.63mA
2.409V    -28.23mA   -25.26mA   -31.02mA
2.591V    -27.66mA   -23.81mA   -29.53mA
3V        -25.95mA   -19.28mA   -28.64mA
[GND_clamp]
-1.5V     -310.1mA   -250.5mA   -402.5mA
-1.076V   -103.6mA   -106.2mA   -105.2mA
-1.046V   -89.81mA   -96.36mA   -86.02mA
-954.6mV  -51.22mA   -67.87mA   -36.88mA
-924.3mV  -40.08mA   -58.86mA   -27.29mA
-863.7mV  -21.24mA   -41.56mA   -16.73mA
-833.4mV  -15.8mA    -33.75mA   -15.03mA
-772.8mV  -9.345mA   -19.75mA   -12.19mA
-712.2mV  -6.928mA   -10.35mA   -9.704mA
-621.3mV  -4.261mA   -3.896mA   -6.225mA
-409.1mV  -337.1uA   -289.1uA   -618.9uA
1.5V      1.518nA    257.2nA    299pA
[Ramp]
dV/dt_f   0.50888/0.11619544n   0.481864/0.13352865n   0.538608/0.10414123n
dV/dt_r  0.5232664/0.10554759n  0.5041456/0.11496225n  0.5483152/95.546097p
R_load = 50
[Rising Waveform]
R_fixture = 50
V_fixture = 1.5001
V_fixture_min = 1.425
V_fixture_max = 1.575
0s        868mV      827.6mV    902.5mV
89.1ps    872mV      831mV      917.1mV
125.9ps   870.8mV    833mV      1.24V
154ps     879.1mV    831.1mV    1.396V
218.6ps   1.269V     831mV      1.532V
246.2ps   1.369V     869.3mV    1.551V
286.9ps   1.444V     1.042V     1.565V
334.5ps   1.478V     1.266V     1.572V
402.3ps   1.495V     1.383V     1.574V
833.3ps   1.5V       1.425V     1.575V
[Rising Waveform]
R_fixture = 50
V_fixture = 0
V_fixture_min = 0
V_fixture_max = 0
74.84ps   0V         0V         0V
100.1ps   3.207mV    2.893mV    0V
139.6ps   0V         4.059mV    383.1mV
177.2ps   -12.82mV   0V         549.6mV
221.5ps   335.7mV    0V         629.5mV
252.9ps   482.6mV    -10.84mV   651.3mV
282.2ps   552.6mV    -16.96mV   662.1mV
354.5ps   616.8mV    410.7mV    671mV
436.2ps   632mV      568.3mV    673mV
908.2ps   635.6mV    607mV      673.5mV
[Falling Waveform]
R_fixture = 50
V_fixture = 1.5001
V_fixture_min = 1.425
V_fixture_max = 1.575
0s        1.499V     1.426V     1.575V
92.83ps   1.495V     1.419V     1.567V
138.6ps   1.499V     1.419V     1.215V
165.5ps   1.494V     1.421V     1.075V
228.6ps   1.108V     1.425V     942.8mV
278.7ps   954.7mV    1.394V     914.8mV
354ps     885.1mV    1.026V     904.1mV
423.4ps   871.4mV    881.1mV    902.3mV
543ps     867.6mV    832.1mV    901.8mV
833.3ps   867.3mV    827.1mV    901.7mV
[Falling Waveform]
R_fixture = 50
V_fixture = 0
V_fixture_min = 0
V_fixture_max = 0
74.84ps   635.6mV    607.4mV    673.4mV
102.8ps   630.7mV    603.1mV    623mV
141.8ps   636mV      600.8mV    307.8mV
167.1ps   625.6mV    603.4mV    172.3mV
198.3ps   441.5mV    604.2mV    82.69mV
239.3ps   193.7mV    610.6mV    31.83mV
280.6ps   79.73mV    564.1mV    13.01mV
359ps     15.18mV    165.3mV    2.278mV
427.6ps   3.748mV    41.27mV    0V
908.2ps   0V         0V         0V
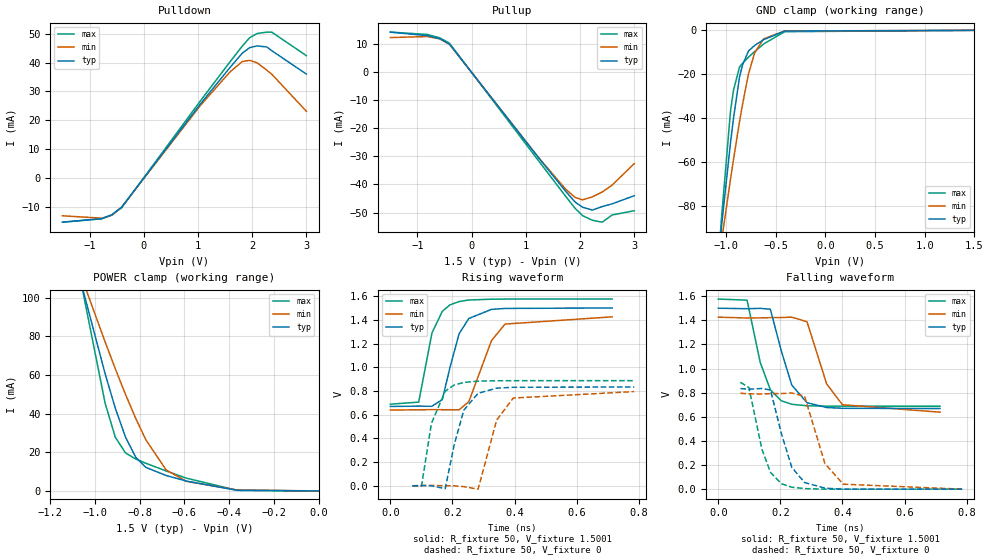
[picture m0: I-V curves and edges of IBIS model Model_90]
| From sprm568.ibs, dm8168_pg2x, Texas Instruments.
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| Model based on original model for BSHTLTCSCDVGPBFZ
|   Sub model FASTEST_10MA_5PER_1P5
[model]   Model_90
|[Description]  [1.5V-3-STATE-X-FASTEST:10MA, IND, 5%]
|   Fastest slew rate (SR[1:0] = "00"), 0.80 * RExt = 1.250 * Iout
|   (I[2:0] = "101"), 10mA nominal with Rext = 50R, ,Industrial
|   temperature range (-40C to 125C, 25C nominal),5% power supply
|   tolerance
|[Input Load]
|[Output Drive] FASTEST:10MA
|Voltage   1.5V
|Mode   3-STATE
Model_type   3-state
Polarity   Non-Inverting
Enable   Active-Low
Cref =  15.0000pF
Rref =  100.0000M
Vref =  0V
Vmeas =  0.75005
C_comp   1.5249p   1.4275p   1.6205p
[Model Spec]
[Temperature Range]   25   125   -40
[Voltage Range]   1.5   1.425   1.575
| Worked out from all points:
|   slope of the pulldown table from 0 to 0.225 V, typ, clamps not added: 39.9 ohm
|   slope of the pullup table from 0 to 0.225 V, typ, clamps not added: 39.8 ohm
|   GND clamp passes 1 mA (typ) near -0.47 V on its own axis
|   POWER clamp passes 1 mA (typ) near -0.42 V on its own axis
|   rising waveform, R_fixture 50, V_fixture 1.5001: 20-80 % time 50.6ps typ, 65.5ps min, 45.5ps max; typ from 0.669 V to 1.5 V
|   rising waveform, R_fixture 50, V_fixture 0: 20-80 % time 48.3ps typ, 51.8ps min, 44ps max; typ from 0 V to 0.834 V
|   falling waveform, R_fixture 50, V_fixture 1.5001: 20-80 % time 54.5ps typ, 59.9ps min, 51ps max; typ from 1.5 V to 0.669 V
|   falling waveform, R_fixture 50, V_fixture 0: 20-80 % time 53ps typ, 56ps min, 49.6ps max; typ from 0.834 V to 0 V
[POWER_clamp]
-1.5V     321.7mA    260.6mA    415.9mA
-1.076V   114.2mA    115.8mA    116.9mA
-1.061V   107.2mA    110.9mA    107.1mA
-954.6mV  60.59mA    77.06mA    45.35mA
-909.2mV  42.85mA    63.21mA    27.81mA
-863.7mV  27.9mA     49.99mA    19.69mA
-818.2mV  17.49mA    37.63mA    16.52mA
-772.8mV  12.19mA    26.53mA    14.33mA
-681.9mV  7.985mA    10.89mA    10.33mA
-590.9mV  5.094mA    4.955mA    6.6mA
-363.7mV  298.5uA    465.2uA    297.6uA
0V        1.518nA    24.08nA    367.8pA
[Pulldown]
-1.5V     -15.29mA   -13.07mA   -15.28mA
-772.8mV  -14.07mA   -13.9mA    -14.11mA
-590.9mV  -12.74mA   -12.86mA   -12.82mA
-409.1mV  -10.08mA   -10.11mA   -10.32mA
1.046V    25.68mA    25.17mA    26.75mA
1.591V    38.31mA    36.75mA    40.25mA
1.818V    43.24mA    40.36mA    45.69mA
1.955V    45.18mA    40.77mA    48.64mA
2.091V    45.77mA    39.91mA    50.06mA
2.273V    45.4mA     37.32mA    50.56mA
2.364V    44.07mA    35.93mA    50.51mA
3V        36.04mA    23.14mA    42.4mA
[Pullup]
-1.5V     14.1mA     12.18mA    14.13mA
-818.2mV  12.87mA    12.54mA    13.29mA
-590.9mV  11.83mA    11.72mA    12.11mA
-409.1mV  9.844mA    9.773mA    10.15mA
1.227V    -30.36mA   -30.27mA   -31.43mA
1.727V    -42.29mA   -41.55mA   -44.05mA
1.909V    -46.29mA   -44.65mA   -48.54mA
2.046V    -48.11mA   -45.48mA   -51.1mA
2.227V    -49.12mA   -44.44mA   -52.74mA
2.409V    -47.87mA   -42.71mA   -53.43mA
2.591V    -46.92mA   -40.26mA   -50.87mA
3V        -44.02mA   -32.61mA   -49.35mA
[GND_clamp]
-1.5V     -310.1mA   -250.5mA   -402.5mA
-1.076V   -103.6mA   -106.2mA   -105.2mA
-1.046V   -89.81mA   -96.36mA   -86.02mA
-954.6mV  -51.22mA   -67.87mA   -36.88mA
-924.3mV  -40.08mA   -58.86mA   -27.29mA
-863.7mV  -21.24mA   -41.56mA   -16.73mA
-833.4mV  -15.8mA    -33.75mA   -15.03mA
-772.8mV  -9.345mA   -19.75mA   -12.19mA
-712.2mV  -6.928mA   -10.35mA   -9.704mA
-621.3mV  -4.261mA   -3.896mA   -6.225mA
-409.1mV  -337.1uA   -289.1uA   -618.9uA
1.5V      1.518nA    257.2nA    299pA
[Ramp]
dV/dt_f   0.669864/87.003099p   0.633872/97.606683p   0.71256/79.867155p
dV/dt_r   0.69126/78.484022p   0.666572/85.514205p  0.7275984/70.847508p
R_load = 50
[Rising Waveform]
R_fixture = 50
V_fixture = 1.5001
V_fixture_min = 1.425
V_fixture_max = 1.575
0s        669.2mV    638.7mV    688.3mV
91.26ps   671.9mV    641.3mV    706mV
133.9ps   670.5mV    642.4mV    1.289V
167.4ps   727.9mV    641.8mV    1.472V
191.9ps   997.3mV    641.7mV    1.526V
221.3ps   1.282V     641.2mV    1.554V
252.6ps   1.411V     709.3mV    1.567V
325.6ps   1.488V     1.224V     1.574V
369.4ps   1.496V     1.364V     1.575V
714.3ps   1.5V       1.425V     1.575V
[Rising Waveform]
R_fixture = 50
V_fixture = 0
V_fixture_min = 0
V_fixture_max = 0
71.27ps   0V         0V         0V
100.4ps   2.056mV    2.481mV    0V
132.3ps   0V         4.122mV    527.6mV
176.6ps   -24.23mV   0V         797.6mV
204.9ps   338.9mV    0V         849.4mV
236.5ps   637.7mV    -7.495mV   871.9mV
282.6ps   780.4mV    -28.43mV   882.9mV
342.2ps   823.4mV    553.5mV    885.9mV
395.8ps   831mV      740.1mV    886.5mV
785.6ps   833.5mV    794.6mV    886.9mV
[Falling Waveform]
R_fixture = 50
V_fixture = 1.5001
V_fixture_min = 1.425
V_fixture_max = 1.575
0s        1.5V       1.426V     1.576V
92.67ps   1.496V     1.419V     1.567V
135.1ps   1.499V     1.42V      1.05V
167.7ps   1.492V     1.422V     823.9mV
202.7ps   1.148V     1.423V     733mV
236.8ps   862.7mV    1.426V     703.5mV
285.8ps   716.7mV    1.388V     691.3mV
349ps     676.8mV    872.8mV    688.3mV
399.9ps   670.4mV    700mV      687.9mV
714.3ps   668.6mV    638.2mV    687.6mV
[Falling Waveform]
R_fixture = 50
V_fixture = 0
V_fixture_min = 0
V_fixture_max = 0
71.27ps   833.8mV    795.3mV    885.9mV
98.58ps   829.1mV    790.1mV    842.4mV
140.5ps   834.5mV    789.1mV    330.9mV
168.1ps   822.2mV    792mV      139.2mV
203.2ps   461mV      792.8mV    45.31mV
236.5ps   182.4mV    797.3mV    16.2mV
278ps     55mV       770.6mV    4.914mV
343.7ps   8.238mV    210.6mV    0V
402.4ps   0V         41.27mV    0V
785.6ps   0V         0V         0V
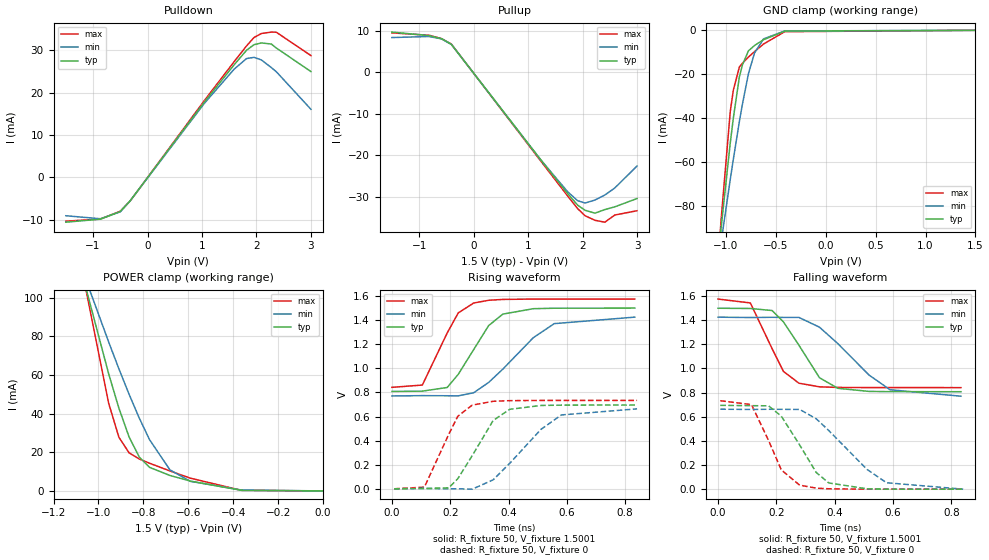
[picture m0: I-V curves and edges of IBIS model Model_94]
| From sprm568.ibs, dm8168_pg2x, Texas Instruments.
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| Model based on original model for BSHTLTCSCDVGPBFZ
|   Sub model FAST_7MA_5PER_1P5
[model]   Model_94
|[Description]  [1.5V-3-STATE-X-FAST:7MA, IND, 5%]
|   Fast slew rate (SR[1:0] = "10"), 1.14 * RExt = 0.875 * Iout
|   (I[2:0] = "010"), 7mA nominal with Rext = 50R, ,Industrial
|   temperature range (-40C to 125C, 25C nominal),5% power supply
|   tolerance
|[Input Load]
|[Output Drive] FAST:7MA
|Voltage   1.5V
|Mode   3-STATE
Model_type   3-state
Polarity   Non-Inverting
Enable   Active-Low
Cref =  15.0000pF
Rref =  100.0000M
Vref =  0V
Vmeas =  0.75005
C_comp   1.5249p   1.4275p   1.6205p
[Model Spec]
[Temperature Range]   25   125   -40
[Voltage Range]   1.5   1.425   1.575
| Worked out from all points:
|   slope of the pulldown table from 0 to 0.225 V, typ, clamps not added: 57.5 ohm
|   slope of the pullup table from 0 to 0.225 V, typ, clamps not added: 57.5 ohm
|   GND clamp passes 1 mA (typ) near -0.47 V on its own axis
|   POWER clamp passes 1 mA (typ) near -0.42 V on its own axis
|   rising waveform, R_fixture 50, V_fixture 1.5001: 20-80 % time 108ps typ, 165ps min, 81.8ps max; typ from 0.808 V to 1.5 V
|   rising waveform, R_fixture 50, V_fixture 0: 20-80 % time 103ps typ, 155ps min, 78.4ps max; typ from 0 V to 0.695 V
|   falling waveform, R_fixture 50, V_fixture 1.5001: 20-80 % time 108ps typ, 170ps min, 81.3ps max; typ from 1.5 V to 0.807 V
|   falling waveform, R_fixture 50, V_fixture 0: 20-80 % time 104ps typ, 165ps min, 78.5ps max; typ from 0.694 V to 0 V
[POWER_clamp]
-1.5V     321.7mA    260.6mA    415.9mA
-1.076V   114.2mA    115.8mA    116.9mA
-1.061V   107.2mA    110.9mA    107.1mA
-954.6mV  60.59mA    77.06mA    45.35mA
-909.2mV  42.85mA    63.21mA    27.81mA
-863.7mV  27.9mA     49.99mA    19.69mA
-818.2mV  17.49mA    37.63mA    16.52mA
-772.8mV  12.19mA    26.53mA    14.33mA
-681.9mV  7.985mA    10.89mA    10.33mA
-590.9mV  5.094mA    4.955mA    6.6mA
-363.7mV  298.5uA    465.2uA    297.6uA
0V        1.518nA    24.08nA    367.8pA
[Pulldown]
-1.5V     -10.59mA   -9.07mA    -10.35mA
-863.7mV  -9.876mA   -9.778mA   -9.846mA
-500mV    -8.072mA   -8.154mA   -8.005mA
-318.2mV  -5.535mA   -5.556mA   -5.589mA
1.046V    17.79mA    17.48mA    18.14mA
1.591V    26.54mA    25.51mA    27.28mA
1.818V    29.96mA    28.01mA    30.98mA
1.955V    31.28mA    28.29mA    32.97mA
2.091V    31.69mA    27.68mA    33.92mA
2.273V    31.43mA    25.88mA    34.25mA
2.364V    30.5mA     24.91mA    34.22mA
3V        24.94mA    16.04mA    28.71mA
[Pullup]
-1.5V     9.77mA     8.45mA     9.58mA
-818.2mV  8.911mA    8.699mA    9.007mA
-590.9mV  8.189mA    8.133mA    8.203mA
-409.1mV  6.819mA    6.785mA    6.878mA
1.227V    -21.03mA   -21.02mA   -21.31mA
1.727V    -29.3mA    -28.85mA   -29.87mA
1.909V    -32.06mA   -30.99mA   -32.91mA
2.046V    -33.31mA   -31.56mA   -34.63mA
2.227V    -34.01mA   -30.83mA   -35.73mA
2.409V    -33.14mA   -29.62mA   -36.19mA
2.591V    -32.48mA   -27.92mA   -34.46mA
3V        -30.47mA   -22.61mA   -33.42mA
[GND_clamp]
-1.5V     -310.1mA   -250.5mA   -402.5mA
-1.076V   -103.6mA   -106.2mA   -105.2mA
-1.046V   -89.81mA   -96.36mA   -86.02mA
-954.6mV  -51.22mA   -67.87mA   -36.88mA
-924.3mV  -40.08mA   -58.86mA   -27.29mA
-863.7mV  -21.24mA   -41.56mA   -16.73mA
-833.4mV  -15.8mA    -33.75mA   -15.03mA
-772.8mV  -9.345mA   -19.75mA   -12.19mA
-712.2mV  -6.928mA   -10.35mA   -9.704mA
-621.3mV  -4.261mA   -3.896mA   -6.225mA
-409.1mV  -337.1uA   -289.1uA   -618.9uA
1.5V      1.518nA    257.2nA    299pA
[Ramp]
dV/dt_f   0.554232/0.16197936n   0.52396/0.24366512n   0.586912/0.12586219n
dV/dt_r 0.55906352/0.15397691n 0.53518248/0.22811101n 0.58793864/0.12101879n
R_load = 50
[Rising Waveform]
R_fixture = 50
V_fixture = 1.5001
V_fixture_min = 1.425
V_fixture_max = 1.575
0s        808.1mV    770.8mV    842.1mV
104.4ps   810.6mV    773.3mV    861.2mV
189.8ps   841.1mV    772.4mV    1.294V
227.6ps   950.4mV    771.6mV    1.46V
280.4ps   1.155V     797.1mV    1.542V
332ps     1.355V     883.1mV    1.565V
380.5ps   1.45V      993.3mV    1.572V
484.9ps   1.495V     1.254V     1.575V
556.9ps   1.499V     1.371V     1.575V
833.3ps   1.5V       1.425V     1.575V
[Rising Waveform]
R_fixture = 50
V_fixture = 0
V_fixture_min = 0
V_fixture_max = 0
7.64ps    0V         0V         0V
111.5ps   2.829mV    2.624mV    13.76mV
194.9ps   7.989mV    0V         452mV
226.4ps   84.66mV    0V         603.1mV
275.5ps   275.1mV    -3.131mV   694.5mV
347.4ps   566.9mV    74.28mV    726.5mV
403.9ps   659.7mV    210.6mV    731.6mV
511.5ps   691.7mV    493.6mV    733.4mV
581.3ps   694.4mV    613mV      733.5mV
841ps     695.3mV    663.5mV    733.6mV
[Falling Waveform]
R_fixture = 50
V_fixture = 1.5001
V_fixture_min = 1.425
V_fixture_max = 1.575
0s        1.499V     1.425V     1.575V
110.8ps   1.497V     1.422V     1.543V
185.3ps   1.48V      1.424V     1.165V
224.4ps   1.386V     1.423V     975.4mV
277.4ps   1.193V     1.423V     878mV
348ps     923.4mV    1.342V     847.9mV
411ps     835.6mV    1.206V     842.8mV
518ps     809.9mV    945.5mV    841.6mV
590.2ps   807.9mV    823.5mV    841.5mV
833.3ps   807.4mV    770.2mV    841.4mV
[Falling Waveform]
R_fixture = 50
V_fixture = 0
V_fixture_min = 0
V_fixture_max = 0
7.64ps    694.3mV    662.5mV    732.8mV
114.7ps   691.8mV    660.4mV    700.7mV
173.2ps   690.7mV    662mV      404.2mV
217.1ps   604.7mV    661.5mV    159.3mV
280.1ps   365.9mV    660.4mV    33.06mV
336.8ps   138.4mV    583.5mV    8.582mV
379.8ps   51.66mV    485.9mV    3.113mV
511ps     2.963mV    163.8mV    0V
577.9ps   0V         53.21mV    0V
841ps     0V         0V         0V
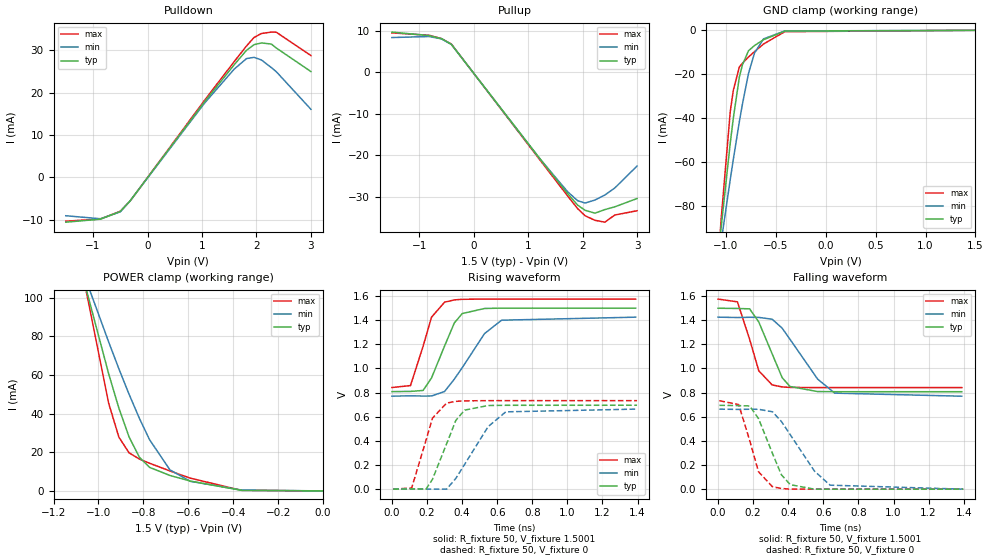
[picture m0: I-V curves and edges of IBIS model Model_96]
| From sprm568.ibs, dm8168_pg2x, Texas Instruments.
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| Model based on original model for BSHTLTCSCDVGPBFZ
|   Sub model SLOW_7MA_5PER_1P5
[model]   Model_96
|[Description]  [1.5V-3-STATE-X-SLOW:7MA, IND, 5%]
|   Slow slew rate (SR[1:0] = "01"), 1.14 * RExt = 0.875 * Iout
|   (I[2:0] = "010"), 7mA nominal with Rext = 50R, ,Industrial
|   temperature range (-40C to 125C, 25C nominal),5% power supply
|   tolerance
|[Input Load]
|[Output Drive] SLOW:7MA
|Voltage   1.5V
|Mode   3-STATE
Model_type   3-state
Polarity   Non-Inverting
Enable   Active-Low
Cref =  15.0000pF
Rref =  100.0000M
Vref =  0V
Vmeas =  0.75005
C_comp   1.5249p   1.4275p   1.6205p
[Model Spec]
[Temperature Range]   25   125   -40
[Voltage Range]   1.5   1.425   1.575
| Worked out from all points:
|   slope of the pulldown table from 0 to 0.225 V, typ, clamps not added: 57.5 ohm
|   slope of the pullup table from 0 to 0.225 V, typ, clamps not added: 57.5 ohm
|   GND clamp passes 1 mA (typ) near -0.47 V on its own axis
|   POWER clamp passes 1 mA (typ) near -0.42 V on its own axis
|   rising waveform, R_fixture 50, V_fixture 1.5001: 20-80 % time 117ps typ, 180ps min, 86.6ps max; typ from 0.808 V to 1.5 V
|   rising waveform, R_fixture 50, V_fixture 0: 20-80 % time 112ps typ, 169ps min, 83.4ps max; typ from 0 V to 0.695 V
|   falling waveform, R_fixture 50, V_fixture 1.5001: 20-80 % time 117ps typ, 189ps min, 85.9ps max; typ from 1.5 V to 0.807 V
|   falling waveform, R_fixture 50, V_fixture 0: 20-80 % time 114ps typ, 183ps min, 83.1ps max; typ from 0.695 V to 0 V
[POWER_clamp]
-1.5V     321.7mA    260.6mA    415.9mA
-1.076V   114.2mA    115.8mA    116.9mA
-1.061V   107.2mA    110.9mA    107.1mA
-954.6mV  60.59mA    77.06mA    45.35mA
-909.2mV  42.85mA    63.21mA    27.81mA
-863.7mV  27.9mA     49.99mA    19.69mA
-818.2mV  17.49mA    37.63mA    16.52mA
-772.8mV  12.19mA    26.53mA    14.33mA
-681.9mV  7.985mA    10.89mA    10.33mA
-590.9mV  5.094mA    4.955mA    6.6mA
-363.7mV  298.5uA    465.2uA    297.6uA
0V        1.518nA    24.08nA    367.8pA
[Pulldown]
-1.5V     -10.59mA   -9.07mA    -10.35mA
-863.7mV  -9.876mA   -9.778mA   -9.846mA
-500mV    -8.072mA   -8.154mA   -8.005mA
-318.2mV  -5.535mA   -5.556mA   -5.589mA
1.046V    17.79mA    17.48mA    18.14mA
1.591V    26.54mA    25.51mA    27.28mA
1.818V    29.96mA    28.01mA    30.98mA
1.955V    31.28mA    28.29mA    32.97mA
2.091V    31.69mA    27.68mA    33.92mA
2.273V    31.43mA    25.88mA    34.25mA
2.364V    30.5mA     24.91mA    34.22mA
3V        24.94mA    16.04mA    28.71mA
[Pullup]
-1.5V     9.77mA     8.45mA     9.58mA
-818.2mV  8.911mA    8.699mA    9.007mA
-590.9mV  8.189mA    8.133mA    8.203mA
-409.1mV  6.819mA    6.785mA    6.878mA
1.227V    -21.03mA   -21.02mA   -21.31mA
1.727V    -29.3mA    -28.85mA   -29.87mA
1.909V    -32.06mA   -30.99mA   -32.91mA
2.046V    -33.31mA   -31.56mA   -34.63mA
2.227V    -34.01mA   -30.83mA   -35.73mA
2.409V    -33.14mA   -29.62mA   -36.19mA
2.591V    -32.48mA   -27.92mA   -34.46mA
3V        -30.47mA   -22.61mA   -33.42mA
[GND_clamp]
-1.5V     -310.1mA   -250.5mA   -402.5mA
-1.076V   -103.6mA   -106.2mA   -105.2mA
-1.046V   -89.81mA   -96.36mA   -86.02mA
-954.6mV  -51.22mA   -67.87mA   -36.88mA
-924.3mV  -40.08mA   -58.86mA   -27.29mA
-863.7mV  -21.24mA   -41.56mA   -16.73mA
-833.4mV  -15.8mA    -33.75mA   -15.03mA
-772.8mV  -9.345mA   -19.75mA   -12.19mA
-712.2mV  -6.928mA   -10.35mA   -9.704mA
-621.3mV  -4.261mA   -3.896mA   -6.225mA
-409.1mV  -337.1uA   -289.1uA   -618.9uA
1.5V      1.518nA    257.2nA    299pA
[Ramp]
dV/dt_f   0.55424/0.17343346n   0.524216/0.27173516n   0.58692/0.131447n
dV/dt_r 0.55917752/0.16500227n 0.53481752/0.25113108n 0.58817192/0.12676555n
R_load = 50
[Rising Waveform]
R_fixture = 50
V_fixture = 1.5001
V_fixture_min = 1.425
V_fixture_max = 1.575
0s        808.1mV    770.8mV    842.1mV
105.9ps   810mV      773.2mV    858.3mV
177.7ps   817.8mV    771.5mV    1.184V
225.8ps   921.6mV    772mV      1.425V
300.1ps   1.186V     809mV      1.549V
355.6ps   1.377V     911.5mV    1.568V
401ps     1.455V     1.007V     1.573V
527.8ps   1.497V     1.289V     1.575V
625.2ps   1.5V       1.4V       1.575V
1.389ns   1.5V       1.425V     1.575V
[Rising Waveform]
R_fixture = 50
V_fixture = 0
V_fixture_min = 0
V_fixture_max = 0
7.64ps    0V         0V         0V
112.6ps   2.605mV    2.445mV    10.2mV
194.2ps   0V         0V         404.5mV
231ps     81.24mV    0V         587.8mV
311.3ps   374.2mV    0V         713.2mV
364ps     569.2mV    88.75mV    727.5mV
414.4ps   655.1mV    205.5mV    731.6mV
548.6ps   693mV      518.7mV    733.5mV
649ps     694.9mV    640.6mV    733.6mV
1.397ns   695.3mV    663.5mV    733.6mV
[Falling Waveform]
R_fixture = 50
V_fixture = 1.5001
V_fixture_min = 1.425
V_fixture_max = 1.575
0s        1.499V     1.425V     1.575V
110.5ps   1.497V     1.422V     1.552V
180.1ps   1.494V     1.424V     1.241V
232.2ps   1.385V     1.423V     980.9mV
308.5ps   1.121V     1.408V     863.6mV
365.5ps   923.7mV    1.334V     847mV
409.9ps   850.8mV    1.242V     843.2mV
567.2ps   808.7mV    912.5mV    841.5mV
664.7ps   807.6mV    795.7mV    841.4mV
1.389ns   807.4mV    770.2mV    841.4mV
[Falling Waveform]
R_fixture = 50
V_fixture = 0
V_fixture_min = 0
V_fixture_max = 0
7.64ps    694.6mV    663mV      732.8mV
117.7ps   692.2mV    660.7mV    700.9mV
180.1ps   689.3mV    662.1mV    405.3mV
230.5ps   584.9mV    661.7mV    144.6mV
309.8ps   297.7mV    641.4mV    20.08mV
360.6ps   120.3mV    561.9mV    6.073mV
411.8ps   37.15mV    450.7mV    0V
549.5ps   0V         149.7mV    0V
638.7ps   0V         33.06mV    0V
1.397ns   0V         0V         0V
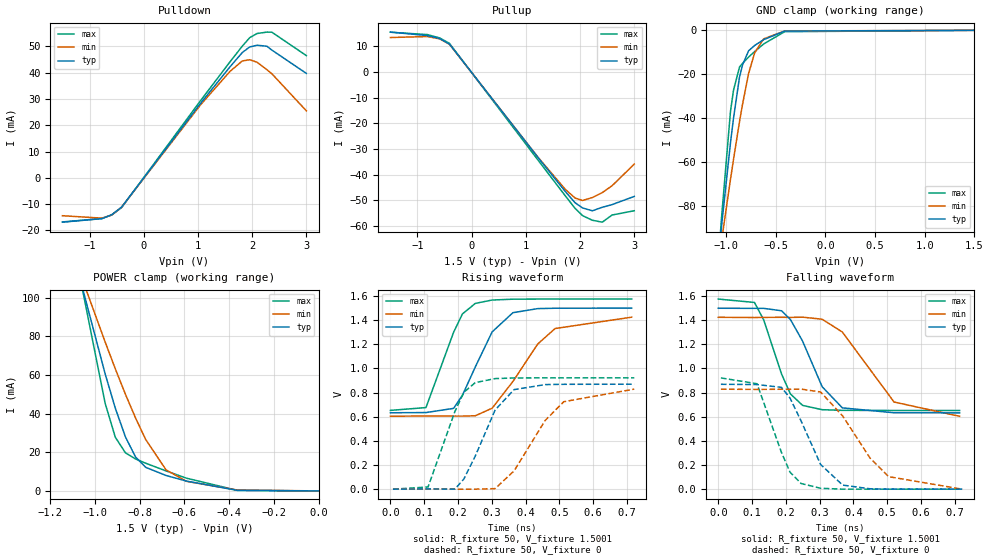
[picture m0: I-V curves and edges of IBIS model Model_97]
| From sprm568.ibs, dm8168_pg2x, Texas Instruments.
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| Model based on original model for BSHTLTCSCDVGPBFZ
|   Sub model FAST_11MA_5PER_1P5
[model]   Model_97
|[Description]  [1.5V-3-STATE-X-FAST:11MA, IND, 5%]
|   Fast slew rate (SR[1:0] = "10"), 0.73 * RExt = 1.325 * Iout
|   (I[2:0] = "110"), 11mA nominal with Rext = 50R, ,Industrial
|   temperature range (-40C to 125C, 25C nominal),5% power supply
|   tolerance
|[Input Load]
|[Output Drive] FAST:11MA
|Voltage   1.5V
|Mode   3-STATE
Model_type   3-state
Polarity   Non-Inverting
Enable   Active-Low
Cref =  15.0000pF
Rref =  100.0000M
Vref =  0V
Vmeas =  0.75005
C_comp   1.5249p   1.4275p   1.6205p
[Model Spec]
[Temperature Range]   25   125   -40
[Voltage Range]   1.5   1.425   1.575
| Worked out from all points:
|   slope of the pulldown table from 0 to 0.225 V, typ, clamps not added: 36.2 ohm
|   slope of the pullup table from 0 to 0.225 V, typ, clamps not added: 36.1 ohm
|   GND clamp passes 1 mA (typ) near -0.47 V on its own axis
|   POWER clamp passes 1 mA (typ) near -0.42 V on its own axis
|   rising waveform, R_fixture 50, V_fixture 1.5001: 20-80 % time 88.6ps typ, 124ps min, 68ps max; typ from 0.633 V to 1.5 V
|   rising waveform, R_fixture 50, V_fixture 0: 20-80 % time 84.2ps typ, 119ps min, 65.8ps max; typ from 0 V to 0.87 V
|   falling waveform, R_fixture 50, V_fixture 1.5001: 20-80 % time 85.7ps typ, 124ps min, 68.2ps max; typ from 1.5 V to 0.632 V
|   falling waveform, R_fixture 50, V_fixture 0: 20-80 % time 86.4ps typ, 123ps min, 66.9ps max; typ from 0.869 V to 0 V
[POWER_clamp]
-1.5V     321.7mA    260.6mA    415.9mA
-1.076V   114.2mA    115.8mA    116.9mA
-1.061V   107.2mA    110.9mA    107.1mA
-954.6mV  60.59mA    77.06mA    45.35mA
-909.2mV  42.85mA    63.21mA    27.81mA
-863.7mV  27.9mA     49.99mA    19.69mA
-818.2mV  17.49mA    37.63mA    16.52mA
-772.8mV  12.19mA    26.53mA    14.33mA
-681.9mV  7.985mA    10.89mA    10.33mA
-590.9mV  5.094mA    4.955mA    6.6mA
-363.7mV  298.5uA    465.2uA    297.6uA
0V        1.518nA    24.08nA    367.8pA
[Pulldown]
-1.5V     -16.86mA   -14.4mA    -16.76mA
-772.8mV  -15.51mA   -15.32mA   -15.47mA
-590.9mV  -14.04mA   -14.17mA   -14.06mA
-409.1mV  -11.11mA   -11.14mA   -11.31mA
1.046V    28.3mA     27.74mA    29.33mA
1.591V    42.23mA    40.49mA    44.13mA
1.818V    47.67mA    44.47mA    50.1mA
1.955V    49.8mA     44.93mA    53.33mA
2.091V    50.46mA    43.98mA    54.91mA
2.273V    50.06mA    41.13mA    55.45mA
2.364V    48.6mA     39.6mA     55.4mA
3V        39.74mA    25.5mA     46.51mA
[Pullup]
-1.5V     15.55mA    13.43mA    15.5mA
-818.2mV  14.19mA    13.81mA    14.58mA
-590.9mV  13.04mA    12.91mA    13.28mA
-409.1mV  10.85mA    10.77mA    11.13mA
1.227V    -33.46mA   -33.35mA   -34.46mA
1.727V    -46.61mA   -45.78mA   -48.31mA
1.909V    -51.03mA   -49.2mA    -53.23mA
2.046V    -53.04mA   -50.12mA   -56.04mA
2.227V    -54.15mA   -48.98mA   -57.84mA
2.409V    -52.79mA   -47.07mA   -58.6mA
2.591V    -51.74mA   -44.37mA   -55.8mA
3V        -48.54mA   -35.95mA   -54.13mA
[GND_clamp]
-1.5V     -310.1mA   -250.5mA   -402.5mA
-1.076V   -103.6mA   -106.2mA   -105.2mA
-1.046V   -89.81mA   -96.36mA   -86.02mA
-954.6mV  -51.22mA   -67.87mA   -36.88mA
-924.3mV  -40.08mA   -58.86mA   -27.29mA
-863.7mV  -21.24mA   -41.56mA   -16.73mA
-833.4mV  -15.8mA    -33.75mA   -15.03mA
-772.8mV  -9.345mA   -19.75mA   -12.19mA
-712.2mV  -6.928mA   -10.35mA   -9.704mA
-621.3mV  -4.261mA   -3.896mA   -6.225mA
-409.1mV  -337.1uA   -289.1uA   -618.9uA
1.5V      1.518nA    257.2nA    299pA
[Ramp]
dV/dt_f   0.694592/0.13104018n   0.657624/0.18794267n   0.738624/0.10377604n
dV/dt_r 0.70111816/0.12737429n 0.67003048/0.18559856n 0.74127568/99.631705p
R_load = 50
[Rising Waveform]
R_fixture = 50
V_fixture = 1.5001
V_fixture_min = 1.425
V_fixture_max = 1.575
0s        632.9mV    604.5mV    652.6mV
105.3ps   634.8mV    606mV      676.1mV
187ps     669.2mV    605.4mV    1.299V
213.3ps   777.9mV    605.2mV    1.452V
251.4ps   1.013V     608.2mV    1.539V
301.2ps   1.303V     670.7mV    1.567V
362.6ps   1.462V     892.1mV    1.574V
436.3ps   1.496V     1.203V     1.575V
487.6ps   1.499V     1.331V     1.575V
714.3ps   1.5V       1.425V     1.575V
[Rising Waveform]
R_fixture = 50
V_fixture = 0
V_fixture_min = 0
V_fixture_max = 0
7.64ps    0V         0V         0V
111.5ps   2.171mV    2.011mV    17.97mV
190.7ps   0V         0V         641.6mV
217.5ps   84.05mV    0V         803mV
251.2ps   274.1mV    0V         882.7mV
310.1ps   656.4mV    4.499mV    916.1mV
366.2ps   824.8mV    151.8mV    921.2mV
458.3ps   866.4mV    569.9mV    922.3mV
513.3ps   868.8mV    724.8mV    922.4mV
721.9ps   869.6mV    828.9mV    922.5mV
[Falling Waveform]
R_fixture = 50
V_fixture = 1.5001
V_fixture_min = 1.425
V_fixture_max = 1.575
0s        1.499V     1.424V     1.575V
107ps     1.498V     1.422V     1.547V
134.3ps   1.498V     1.423V     1.403V
187.1ps   1.478V     1.424V     954.8mV
213.4ps   1.406V     1.423V     789.3mV
249.6ps   1.226V     1.425V     693.9mV
307.4ps   848.9mV    1.408V     658.4mV
367.1ps   673.7mV    1.302V     653mV
520.3ps   632.9mV    721.9mV    652mV
714.3ps   632.3mV    603.6mV    651.8mV
[Falling Waveform]
R_fixture = 50
V_fixture = 0
V_fixture_min = 0
V_fixture_max = 0
7.64ps    868.9mV    828.4mV    921.7mV
114.6ps   866.8mV    826.3mV    873.5mV
186.8ps   843.5mV    827.9mV    305.5mV
212.3ps   754.9mV    827.1mV    140.7mV
245.2ps   564.1mV    828.9mV    46.77mV
302.8ps   204.8mV    804.9mV    7.433mV
368.1ps   33.73mV    606.7mV    0V
449.1ps   3.197mV    258.1mV    0V
504.1ps   0V         103.7mV    0V
721.9ps   0V         0V         0V
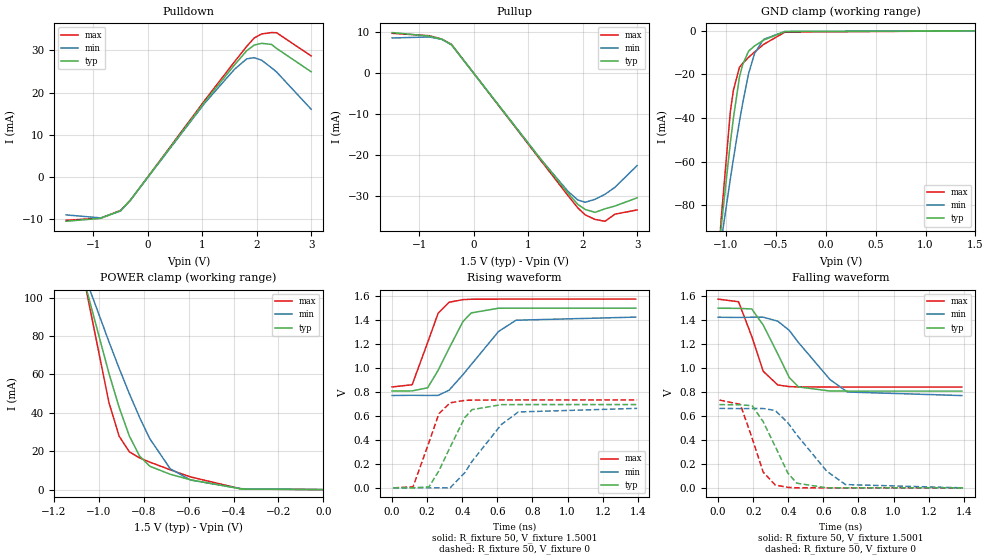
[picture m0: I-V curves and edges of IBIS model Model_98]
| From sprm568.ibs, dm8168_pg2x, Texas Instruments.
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| Model based on original model for BSHTLTCSCDVGPBFZ
|   Sub model SLOWEST_7MA_5PER_1P5
[model]   Model_98
|[Description]  [1.5V-3-STATE-X-SLOWEST:7MA, IND, 5%]
|   Slowest slew rate (SR[1:0] = "11"), 1.14 * RExt = 0.875 * Iout
|   (I[2:0] = "010"), 7mA nominal with Rext = 50R, ,Industrial
|   temperature range (-40C to 125C, 25C nominal),5% power supply
|   tolerance
|[Input Load]
|[Output Drive] SLOWEST:7MA
|Voltage   1.5V
|Mode   3-STATE
Model_type   3-state
Polarity   Non-Inverting
Enable   Active-Low
Cref =  15.0000pF
Rref =  100.0000M
Vref =  0V
Vmeas =  0.75005
C_comp   1.5249p   1.4275p   1.6205p
[Model Spec]
[Temperature Range]   25   125   -40
[Voltage Range]   1.5   1.425   1.575
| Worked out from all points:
|   slope of the pulldown table from 0 to 0.225 V, typ, clamps not added: 57.5 ohm
|   slope of the pullup table from 0 to 0.225 V, typ, clamps not added: 57.5 ohm
|   GND clamp passes 1 mA (typ) near -0.47 V on its own axis
|   POWER clamp passes 1 mA (typ) near -0.42 V on its own axis
|   rising waveform, R_fixture 50, V_fixture 1.5001: 20-80 % time 142ps typ, 220ps min, 101ps max; typ from 0.808 V to 1.5 V
|   rising waveform, R_fixture 50, V_fixture 0: 20-80 % time 137ps typ, 207ps min, 98.3ps max; typ from 0 V to 0.695 V
|   falling waveform, R_fixture 50, V_fixture 1.5001: 20-80 % time 139ps typ, 223ps min, 98ps max; typ from 1.5 V to 0.807 V
|   falling waveform, R_fixture 50, V_fixture 0: 20-80 % time 136ps typ, 219ps min, 95.1ps max; typ from 0.695 V to 0 V
[POWER_clamp]
-1.5V     321.7mA    260.6mA    415.9mA
-1.076V   114.2mA    115.8mA    116.9mA
-1.061V   107.2mA    110.9mA    107.1mA
-954.6mV  60.59mA    77.06mA    45.35mA
-909.2mV  42.85mA    63.21mA    27.81mA
-863.7mV  27.9mA     49.99mA    19.69mA
-818.2mV  17.49mA    37.63mA    16.52mA
-772.8mV  12.19mA    26.53mA    14.33mA
-681.9mV  7.985mA    10.89mA    10.33mA
-590.9mV  5.094mA    4.955mA    6.6mA
-363.7mV  298.5uA    465.2uA    297.6uA
0V        1.518nA    24.08nA    367.8pA
[Pulldown]
-1.5V     -10.59mA   -9.07mA    -10.35mA
-863.7mV  -9.876mA   -9.778mA   -9.846mA
-500mV    -8.072mA   -8.154mA   -8.005mA
-318.2mV  -5.535mA   -5.556mA   -5.589mA
1.046V    17.79mA    17.48mA    18.14mA
1.591V    26.54mA    25.51mA    27.28mA
1.818V    29.96mA    28.01mA    30.98mA
1.955V    31.28mA    28.29mA    32.97mA
2.091V    31.69mA    27.68mA    33.92mA
2.273V    31.43mA    25.88mA    34.25mA
2.364V    30.5mA     24.91mA    34.22mA
3V        24.94mA    16.04mA    28.71mA
[Pullup]
-1.5V     9.77mA     8.45mA     9.58mA
-818.2mV  8.911mA    8.699mA    9.007mA
-590.9mV  8.189mA    8.133mA    8.203mA
-409.1mV  6.819mA    6.785mA    6.878mA
1.227V    -21.03mA   -21.02mA   -21.31mA
1.727V    -29.3mA    -28.85mA   -29.87mA
1.909V    -32.06mA   -30.99mA   -32.91mA
2.046V    -33.31mA   -31.56mA   -34.63mA
2.227V    -34.01mA   -30.83mA   -35.73mA
2.409V    -33.14mA   -29.62mA   -36.19mA
2.591V    -32.48mA   -27.92mA   -34.46mA
3V        -30.47mA   -22.61mA   -33.42mA
[GND_clamp]
-1.5V     -310.1mA   -250.5mA   -402.5mA
-1.076V   -103.6mA   -106.2mA   -105.2mA
-1.046V   -89.81mA   -96.36mA   -86.02mA
-954.6mV  -51.22mA   -67.87mA   -36.88mA
-924.3mV  -40.08mA   -58.86mA   -27.29mA
-863.7mV  -21.24mA   -41.56mA   -16.73mA
-833.4mV  -15.8mA    -33.75mA   -15.03mA
-772.8mV  -9.345mA   -19.75mA   -12.19mA
-712.2mV  -6.928mA   -10.35mA   -9.704mA
-621.3mV  -4.261mA   -3.896mA   -6.225mA
-409.1mV  -337.1uA   -289.1uA   -618.9uA
1.5V      1.518nA    257.2nA    299pA
[Ramp]
dV/dt_f   0.55424/0.20034389n   0.524456/0.33192954n   0.587/0.14539393n
dV/dt_r  0.5590628/0.19793036n 0.53494576/0.31388454n 0.58797184/0.14384484n
R_load = 50
[Rising Waveform]
R_fixture = 50
V_fixture = 1.5001
V_fixture_min = 1.425
V_fixture_max = 1.575
0s        808.1mV    770.8mV    842.1mV
114.3ps   809.2mV    772.6mV    860.6mV
202.4ps   834.9mV    771.3mV    1.212V
262.7ps   981.4mV    772mV      1.458V
325.3ps   1.166V     815.6mV    1.549V
404.2ps   1.389V     945.5mV    1.571V
451.2ps   1.46V      1.029V     1.574V
606.9ps   1.499V     1.305V     1.575V
706.4ps   1.5V       1.399V     1.575V
1.389ns   1.5V       1.425V     1.575V
[Rising Waveform]
R_fixture = 50
V_fixture = 0
V_fixture_min = 0
V_fixture_max = 0
7.64ps    0V         0V         0V
119.4ps   0V         2.013mV    8.736mV
210.1ps   7.926mV    0V         379.1mV
266.7ps   142mV      0V         618.8mV
330.8ps   339.4mV    0V         709.6mV
414.3ps   586.7mV    126.8mV    730.2mV
456.2ps   653mV      221.9mV    732.3mV
622.3ps   694.1mV    528mV      733.5mV
719.6ps   695.1mV    633.5mV    733.6mV
1.397ns   695.3mV    663.5mV    733.6mV
[Falling Waveform]
R_fixture = 50
V_fixture = 1.5001
V_fixture_min = 1.425
V_fixture_max = 1.575
0s        1.499V     1.424V     1.575V
116.6ps   1.498V     1.422V     1.553V
191.7ps   1.493V     1.424V     1.264V
257.2ps   1.358V     1.424V     972.7mV
339.9ps   1.118V     1.391V     858.7mV
405.8ps   919.8mV    1.314V     844.9mV
458.4ps   842.4mV    1.212V     842.4mV
638ps     808mV      903.6mV    841.5mV
736.3ps   807.5mV    800mV      841.4mV
1.389ns   807.4mV    770.2mV    841.4mV
[Falling Waveform]
R_fixture = 50
V_fixture = 0
V_fixture_min = 0
V_fixture_max = 0
7.64ps    694.7mV    663mV      732.8mV
126.5ps   693.1mV    661.3mV    696.6mV
194.1ps   685.1mV    662.2mV    414mV
256.8ps   552.8mV    662.3mV    131.4mV
325.5ps   345.5mV    645.6mV    23.84mV
397.3ps   123.8mV    543.5mV    4.41mV
448.5ps   39.05mV    441.7mV    0V
619.9ps   0V         138.1mV    0V
726ps     0V         27.39mV    0V
1.397ns   0V         0V         0V
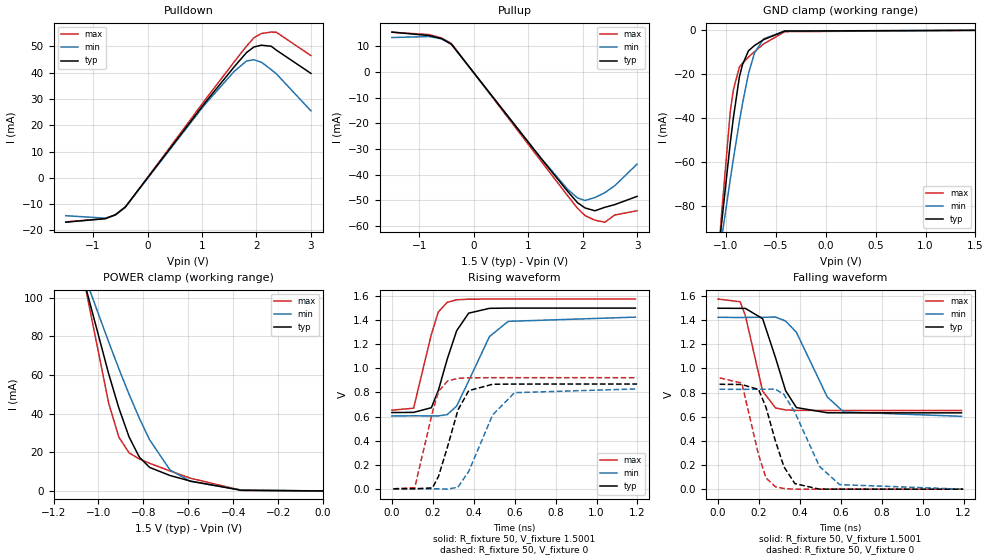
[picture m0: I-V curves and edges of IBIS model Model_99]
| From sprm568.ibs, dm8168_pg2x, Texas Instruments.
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| Model based on original model for BSHTLTCSCDVGPBFZ
|   Sub model SLOW_11MA_5PER_1P5
[model]   Model_99
|[Description]  [1.5V-3-STATE-X-SLOW:11MA, IND, 5%]
|   Slow slew rate (SR[1:0] = "01"), 0.73 * RExt = 1.325 * Iout
|   (I[2:0] = "110"), 11mA nominal with Rext = 50R, ,Industrial
|   temperature range (-40C to 125C, 25C nominal),5% power supply
|   tolerance
|[Input Load]
|[Output Drive] SLOW:11MA
|Voltage   1.5V
|Mode   3-STATE
Model_type   3-state
Polarity   Non-Inverting
Enable   Active-Low
Cref =  15.0000pF
Rref =  100.0000M
Vref =  0V
Vmeas =  0.75005
C_comp   1.5249p   1.4275p   1.6205p
[Model Spec]
[Temperature Range]   25   125   -40
[Voltage Range]   1.5   1.425   1.575
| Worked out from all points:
|   slope of the pulldown table from 0 to 0.225 V, typ, clamps not added: 36.2 ohm
|   slope of the pullup table from 0 to 0.225 V, typ, clamps not added: 36.1 ohm
|   GND clamp passes 1 mA (typ) near -0.47 V on its own axis
|   POWER clamp passes 1 mA (typ) near -0.42 V on its own axis
|   rising waveform, R_fixture 50, V_fixture 1.5001: 20-80 % time 95.7ps typ, 135ps min, 73.1ps max; typ from 0.633 V to 1.5 V
|   rising waveform, R_fixture 50, V_fixture 0: 20-80 % time 91ps typ, 130ps min, 70.8ps max; typ from 0 V to 0.87 V
|   falling waveform, R_fixture 50, V_fixture 1.5001: 20-80 % time 93.6ps typ, 138ps min, 72.8ps max; typ from 1.5 V to 0.632 V
|   falling waveform, R_fixture 50, V_fixture 0: 20-80 % time 94.2ps typ, 137ps min, 71.7ps max; typ from 0.869 V to 0 V
[POWER_clamp]
-1.5V     321.7mA    260.6mA    415.9mA
-1.076V   114.2mA    115.8mA    116.9mA
-1.061V   107.2mA    110.9mA    107.1mA
-954.6mV  60.59mA    77.06mA    45.35mA
-909.2mV  42.85mA    63.21mA    27.81mA
-863.7mV  27.9mA     49.99mA    19.69mA
-818.2mV  17.49mA    37.63mA    16.52mA
-772.8mV  12.19mA    26.53mA    14.33mA
-681.9mV  7.985mA    10.89mA    10.33mA
-590.9mV  5.094mA    4.955mA    6.6mA
-363.7mV  298.5uA    465.2uA    297.6uA
0V        1.518nA    24.08nA    367.8pA
[Pulldown]
-1.5V     -16.86mA   -14.4mA    -16.76mA
-772.8mV  -15.51mA   -15.32mA   -15.47mA
-590.9mV  -14.04mA   -14.17mA   -14.06mA
-409.1mV  -11.11mA   -11.14mA   -11.31mA
1.046V    28.3mA     27.74mA    29.33mA
1.591V    42.23mA    40.49mA    44.13mA
1.818V    47.67mA    44.47mA    50.1mA
1.955V    49.8mA     44.93mA    53.33mA
2.091V    50.46mA    43.98mA    54.91mA
2.273V    50.06mA    41.13mA    55.45mA
2.364V    48.6mA     39.6mA     55.4mA
3V        39.74mA    25.5mA     46.51mA
[Pullup]
-1.5V     15.55mA    13.43mA    15.5mA
-818.2mV  14.19mA    13.81mA    14.58mA
-590.9mV  13.04mA    12.91mA    13.28mA
-409.1mV  10.85mA    10.77mA    11.13mA
1.227V    -33.46mA   -33.35mA   -34.46mA
1.727V    -46.61mA   -45.78mA   -48.31mA
1.909V    -51.03mA   -49.2mA    -53.23mA
2.046V    -53.04mA   -50.12mA   -56.04mA
2.227V    -54.15mA   -48.98mA   -57.84mA
2.409V    -52.79mA   -47.07mA   -58.6mA
2.591V    -51.74mA   -44.37mA   -55.8mA
3V        -48.54mA   -35.95mA   -54.13mA
[GND_clamp]
-1.5V     -310.1mA   -250.5mA   -402.5mA
-1.076V   -103.6mA   -106.2mA   -105.2mA
-1.046V   -89.81mA   -96.36mA   -86.02mA
-954.6mV  -51.22mA   -67.87mA   -36.88mA
-924.3mV  -40.08mA   -58.86mA   -27.29mA
-863.7mV  -21.24mA   -41.56mA   -16.73mA
-833.4mV  -15.8mA    -33.75mA   -15.03mA
-772.8mV  -9.345mA   -19.75mA   -12.19mA
-712.2mV  -6.928mA   -10.35mA   -9.704mA
-621.3mV  -4.261mA   -3.896mA   -6.225mA
-409.1mV  -337.1uA   -289.1uA   -618.9uA
1.5V      1.518nA    257.2nA    299pA
[Ramp]
dV/dt_f   0.694432/0.14222577n   0.65796/0.20883086n   0.738624/0.1094479n
dV/dt_r 0.70114632/0.13867222n 0.66946112/0.20372721n  0.7415028/0.10556792n
R_load = 50
[Rising Waveform]
R_fixture = 50
V_fixture = 1.5001
V_fixture_min = 1.425
V_fixture_max = 1.575
0s        632.9mV    604.5mV    652.6mV
105.9ps   634.2mV    605.9mV    669.1mV
192.8ps   673.1mV    605mV      1.282V
226.9ps   816.5mV    605mV      1.468V
270.3ps   1.076V     616mV      1.548V
316.4ps   1.312V     686.7mV    1.569V
375.1ps   1.458V     895.2mV    1.574V
476.8ps   1.498V     1.264V     1.575V
568.5ps   1.5V       1.39V      1.575V
1.19ns    1.5V       1.425V     1.575V
[Rising Waveform]
R_fixture = 50
V_fixture = 0
V_fixture_min = 0
V_fixture_max = 0
7.64ps    0V         0V         0V
111.6ps   0V         0V         9.38mV
198.2ps   7.566mV    0V         636.6mV
227.9ps   104mV      0V         807.7mV
271.9ps   348.7mV    -3.206mV   894.9mV
322.9ps   654.8mV    13.45mV    916.8mV
375.6ps   814.9mV    144.8mV    921.2mV
492ps     867.7mV    612.6mV    922.3mV
599.2ps   869.4mV    798mV      922.4mV
1.198ns   869.7mV    828.9mV    922.5mV
[Falling Waveform]
R_fixture = 50
V_fixture = 1.5001
V_fixture_min = 1.425
V_fixture_max = 1.575
0s        1.499V     1.424V     1.575V
107.7ps   1.498V     1.422V     1.553V
133.4ps   1.498V     1.423V     1.439V
218ps     1.412V     1.424V     812.5mV
280.9ps   1.089V     1.426V     672.8mV
330.2ps   815.8mV    1.393V     656.3mV
382.9ps   676.1mV    1.3V       652.8mV
533.7ps   632.9mV    764.4mV    652mV
613.6ps   632.4mV    639.8mV    651.9mV
1.19ns    632.3mV    603.6mV    651.8mV
[Falling Waveform]
R_fixture = 50
V_fixture = 0
V_fixture_min = 0
V_fixture_max = 0
7.64ps    869mV      827.9mV    921.7mV
116.3ps   867.2mV    826.5mV    878.7mV
198.4ps   825.2mV    828mV      282.2mV
234.3ps   678.6mV    827.4mV    92.8mV
279.8ps   402.5mV    829.4mV    20.43mV
322.2ps   185mV      784.5mV    5.324mV
375.7ps   45.97mV    635.7mV    0V
495.8ps   0V         188.4mV    0V
594.3ps   0V         37.46mV    0V
1.198ns   0V         0V         0V
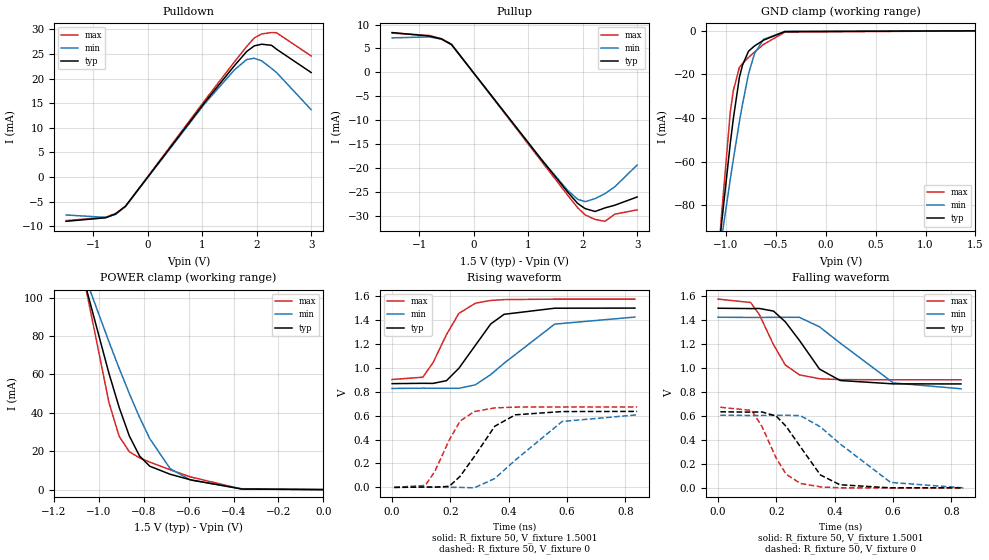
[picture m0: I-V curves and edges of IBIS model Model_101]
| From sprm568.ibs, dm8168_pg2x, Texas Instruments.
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| Model based on original model for BSHTLTCSCDVGPBFZ
|   Sub model FAST_6MA_5PER_1P5
[model]   Model_101
|[Description]  [1.5V-3-STATE-X-FAST:6MA, IND, 5%]
|   Fast slew rate (SR[1:0] = "10"), 1.33 * RExt = 0.750 * Iout
|   (I[2:0] = "001"), 6mA nominal with Rext = 50R, ,Industrial
|   temperature range (-40C to 125C, 25C nominal),5% power supply
|   tolerance
|[Input Load]
|[Output Drive] FAST:6MA
|Voltage   1.5V
|Mode   3-STATE
Model_type   3-state
Polarity   Non-Inverting
Enable   Active-Low
Cref =  15.0000pF
Rref =  100.0000M
Vref =  0V
Vmeas =  0.75005
C_comp   1.5249p   1.4275p   1.6205p
[Model Spec]
[Temperature Range]   25   125   -40
[Voltage Range]   1.5   1.425   1.575
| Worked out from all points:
|   slope of the pulldown table from 0 to 0.225 V, typ, clamps not added: 67.5 ohm
|   slope of the pullup table from 0 to 0.225 V, typ, clamps not added: 67.5 ohm
|   GND clamp passes 1 mA (typ) near -0.47 V on its own axis
|   POWER clamp passes 1 mA (typ) near -0.42 V on its own axis
|   rising waveform, R_fixture 50, V_fixture 1.5001: 20-80 % time 112ps typ, 175ps min, 84.6ps max; typ from 0.868 V to 1.5 V
|   rising waveform, R_fixture 50, V_fixture 0: 20-80 % time 107ps typ, 165ps min, 80.9ps max; typ from 0 V to 0.636 V
|   falling waveform, R_fixture 50, V_fixture 1.5001: 20-80 % time 112ps typ, 181ps min, 84ps max; typ from 1.5 V to 0.867 V
|   falling waveform, R_fixture 50, V_fixture 0: 20-80 % time 108ps typ, 174ps min, 81.2ps max; typ from 0.635 V to 0 V
[POWER_clamp]
-1.5V     321.7mA    260.6mA    415.9mA
-1.076V   114.2mA    115.8mA    116.9mA
-1.061V   107.2mA    110.9mA    107.1mA
-954.6mV  60.59mA    77.06mA    45.35mA
-909.2mV  42.85mA    63.21mA    27.81mA
-863.7mV  27.9mA     49.99mA    19.69mA
-818.2mV  17.49mA    37.63mA    16.52mA
-772.8mV  12.19mA    26.53mA    14.33mA
-681.9mV  7.985mA    10.89mA    10.33mA
-590.9mV  5.094mA    4.955mA    6.6mA
-363.7mV  298.5uA    465.2uA    297.6uA
0V        1.518nA    24.08nA    367.8pA
[Pulldown]
-1.5V     -9.02mA    -7.73mA    -8.88mA
-772.8mV  -8.3mA     -8.227mA   -8.195mA
-590.9mV  -7.513mA   -7.616mA   -7.446mA
-409.1mV  -5.951mA   -5.987mA   -5.996mA
1.046V    15.16mA    14.91mA    15.55mA
1.591V    22.62mA    21.77mA    23.39mA
1.818V    25.52mA    23.89mA    26.56mA
1.955V    26.65mA    24.13mA    28.26mA
2.091V    26.99mA    23.61mA    29.08mA
2.273V    26.77mA    22.07mA    29.36mA
2.364V    25.98mA    21.25mA    29.33mA
3V        21.24mA    13.68mA    24.61mA
[Pullup]
-1.5V     8.32mA     7.21mA     8.21mA
-818.2mV  7.591mA    7.42mA     7.72mA
-590.9mV  6.976mA    6.937mA    7.031mA
-409.1mV  5.81mA     5.788mA    5.897mA
1.227V    -17.92mA   -17.93mA   -18.27mA
1.727V    -24.96mA   -24.61mA   -25.61mA
1.909V    -27.32mA   -26.44mA   -28.21mA
2.046V    -28.38mA   -26.92mA   -29.69mA
2.227V    -28.97mA   -26.29mA   -30.63mA
2.409V    -28.23mA   -25.26mA   -31.02mA
2.591V    -27.66mA   -23.81mA   -29.53mA
3V        -25.95mA   -19.28mA   -28.64mA
[GND_clamp]
-1.5V     -310.1mA   -250.5mA   -402.5mA
-1.076V   -103.6mA   -106.2mA   -105.2mA
-1.046V   -89.81mA   -96.36mA   -86.02mA
-954.6mV  -51.22mA   -67.87mA   -36.88mA
-924.3mV  -40.08mA   -58.86mA   -27.29mA
-863.7mV  -21.24mA   -41.56mA   -16.73mA
-833.4mV  -15.8mA    -33.75mA   -15.03mA
-772.8mV  -9.345mA   -19.75mA   -12.19mA
-712.2mV  -6.928mA   -10.35mA   -9.704mA
-621.3mV  -4.261mA   -3.896mA   -6.225mA
-409.1mV  -337.1uA   -289.1uA   -618.9uA
1.5V      1.518nA    257.2nA    299pA
[Ramp]
dV/dt_f   0.50632/0.16964923n   0.478424/0.25753774n   0.538608/0.13202918n
dV/dt_r 0.51057504/0.16159097n   0.489424/0.23832936n 0.53907178/0.12743702n
R_load = 50
[Rising Waveform]
R_fixture = 50
V_fixture = 1.5001
V_fixture_min = 1.425
V_fixture_max = 1.575
0s        868mV      827.6mV    902.5mV
105.4ps   870.7mV    830.2mV    921.9mV
140.6ps   870mV      829.6mV    1.044V
186.5ps   892.8mV    829.3mV    1.278V
229.3ps   996.8mV    828.7mV    1.456V
285.9ps   1.189V     858.1mV    1.541V
338.4ps   1.367V     943.6mV    1.564V
384.4ps   1.448V     1.039V     1.571V
558ps     1.499V     1.366V     1.575V
833.3ps   1.5V       1.425V     1.575V
[Rising Waveform]
R_fixture = 50
V_fixture = 0
V_fixture_min = 0
V_fixture_max = 0
7.64ps    0V         0V         0V
113.6ps   2.934mV    2.74mV     16.2mV
146.7ps   2.088mV    2.219mV    133.6mV
196.2ps   8.972mV    0V         397.3mV
233.5ps   92.96mV    0V         555.3mV
281.8ps   257mV      -3.907mV   634.2mV
352.4ps   511.7mV    74.52mV    665.2mV
423ps     607.4mV    228.6mV    671.5mV
583.6ps   634.4mV    551.5mV    673.4mV
841ps     635.6mV    607mV      673.5mV
[Falling Waveform]
R_fixture = 50
V_fixture = 1.5001
V_fixture_min = 1.425
V_fixture_max = 1.575
0s        1.499V     1.424V     1.575V
111.6ps   1.496V     1.422V     1.547V
141.5ps   1.497V     1.422V     1.446V
190.2ps   1.475V     1.423V     1.194V
230.4ps   1.386V     1.423V     1.026V
278.9ps   1.231V     1.423V     943.2mV
347.9ps   991.1mV    1.344V     910.6mV
418.9ps   895.8mV    1.208V     903.4mV
601.2ps   867.9mV    875.7mV    901.8mV
833.3ps   867.3mV    827.1mV    901.7mV
[Falling Waveform]
R_fixture = 50
V_fixture = 0
V_fixture_min = 0
V_fixture_max = 0
7.64ps    634.7mV    606.3mV    672.6mV
115ps     632mV      603.7mV    646.3mV
150ps     633.7mV    604.3mV    514.6mV
199.3ps   599.2mV    605mV      247.4mV
233.4ps   513mV      605.8mV    113.9mV
282.3ps   342.8mV    602.6mV    36.92mV
350.9ps   107.9mV    509.2mV    8.136mV
417.7ps   26.11mV    368.4mV    0V
591.9ps   0V         45.49mV    0V
841ps     0V         0V         0V
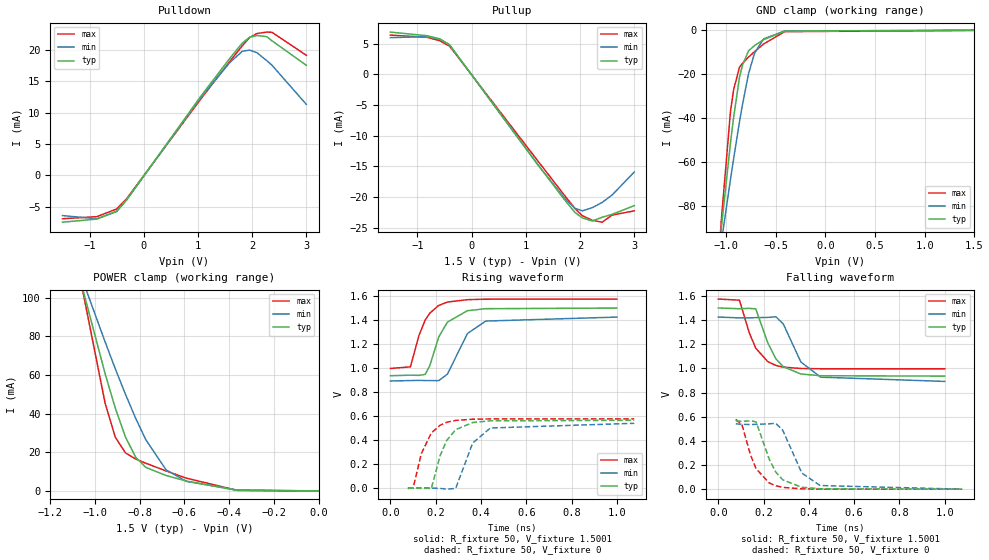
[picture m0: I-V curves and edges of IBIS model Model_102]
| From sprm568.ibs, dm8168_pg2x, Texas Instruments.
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| Model based on original model for BSHTLTCSCDVGPBFZ
|   Sub model FASTEST_5MA_5PER_1P5
[model]   Model_102
|[Description]  [1.5V-3-STATE-X-FASTEST:5MA, IND, 5%]
|   Fastest slew rate (SR[1:0] = "00"), 1.60 * RExt = 0.625 * Iout
|   (I[2:0] = "000"), 5mA nominal with Rext = 50R, ,Industrial
|   temperature range (-40C to 125C, 25C nominal),5% power supply
|   tolerance
|[Input Load]
|[Output Drive] FASTEST:5MA
|Voltage   1.5V
|Mode   3-STATE
Model_type   3-state
Polarity   Non-Inverting
Enable   Active-Low
Cref =  15.0000pF
Rref =  100.0000M
Vref =  0V
Vmeas =  0.75005
C_comp   1.5249p   1.4275p   1.6205p
[Model Spec]
[Temperature Range]   25   125   -40
[Voltage Range]   1.5   1.425   1.575
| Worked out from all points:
|   slope of the pulldown table from 0 to 0.225 V, typ, clamps not added: 81.7 ohm
|   slope of the pullup table from 0 to 0.225 V, typ, clamps not added: 81.7 ohm
|   GND clamp passes 1 mA (typ) near -0.47 V on its own axis
|   POWER clamp passes 1 mA (typ) near -0.42 V on its own axis
|   rising waveform, R_fixture 50, V_fixture 1.5001: 20-80 % time 74.9ps typ, 89.3ps min, 69.9ps max; typ from 0.937 V to 1.5 V
|   rising waveform, R_fixture 50, V_fixture 0: 20-80 % time 71.5ps typ, 77.4ps min, 67.6ps max; typ from 0 V to 0.566 V
|   falling waveform, R_fixture 50, V_fixture 1.5001: 20-80 % time 79.4ps typ, 90.4ps min, 73.7ps max; typ from 1.5 V to 0.937 V
|   falling waveform, R_fixture 50, V_fixture 0: 20-80 % time 74.7ps typ, 82.7ps min, 69.1ps max; typ from 0.567 V to 0 V
[POWER_clamp]
-1.5V     321.7mA    260.6mA    415.9mA
-1.076V   114.2mA    115.8mA    116.9mA
-1.061V   107.2mA    110.9mA    107.1mA
-954.6mV  60.59mA    77.06mA    45.35mA
-909.2mV  42.85mA    63.21mA    27.81mA
-863.7mV  27.9mA     49.99mA    19.69mA
-818.2mV  17.49mA    37.63mA    16.52mA
-772.8mV  12.19mA    26.53mA    14.33mA
-681.9mV  7.985mA    10.89mA    10.33mA
-590.9mV  5.094mA    4.955mA    6.6mA
-363.7mV  298.5uA    465.2uA    297.6uA
0V        1.518nA    24.08nA    367.8pA
[Pulldown]
-1.5V     -7.45mA    -6.4mA     -6.9mA
-863.7mV  -6.95mA    -6.903mA   -6.565mA
-500mV    -5.682mA   -5.758mA   -5.339mA
-318.2mV  -3.897mA   -3.924mA   -3.728mA
1.046V    12.53mA    12.35mA    12.1mA
1.591V    18.69mA    18.02mA    18.2mA
1.818V    21.09mA    19.78mA    20.66mA
1.955V    22.02mA    19.97mA    21.99mA
2.091V    22.3mA     19.54mA    22.62mA
2.273V    22.11mA    18.26mA    22.84mA
2.364V    21.46mA    17.58mA    22.81mA
3V        17.55mA    11.32mA    19.14mA
[Pullup]
-1.5V     6.87mA     5.96mA     6.38mA
-818.2mV  6.271mA    6.141mA    6.005mA
-590.9mV  5.763mA    5.741mA    5.469mA
-409.1mV  4.8mA      4.791mA    4.587mA
1.227V    -14.81mA   -14.84mA   -14.21mA
1.727V    -20.63mA   -20.37mA   -19.92mA
1.909V    -22.57mA   -21.88mA   -21.95mA
2.046V    -23.45mA   -22.28mA   -23.09mA
2.227V    -23.93mA   -21.76mA   -23.82mA
2.409V    -23.32mA   -20.9mA    -24.13mA
2.591V    -22.85mA   -19.7mA    -22.97mA
3V        -21.43mA   -15.95mA   -22.28mA
[GND_clamp]
-1.5V     -310.1mA   -250.5mA   -402.5mA
-1.076V   -103.6mA   -106.2mA   -105.2mA
-1.046V   -89.81mA   -96.36mA   -86.02mA
-954.6mV  -51.22mA   -67.87mA   -36.88mA
-924.3mV  -40.08mA   -58.86mA   -27.29mA
-863.7mV  -21.24mA   -41.56mA   -16.73mA
-833.4mV  -15.8mA    -33.75mA   -15.03mA
-772.8mV  -9.345mA   -19.75mA   -12.19mA
-712.2mV  -6.928mA   -10.35mA   -9.704mA
-621.3mV  -4.261mA   -3.896mA   -6.225mA
-409.1mV  -337.1uA   -289.1uA   -618.9uA
1.5V      1.518nA    257.2nA    299pA
[Ramp]
dV/dt_f   0.452608/0.12547729n   0.428536/0.14310966n   0.4624/0.11659787n
dV/dt_r  0.4651824/0.11495247n  0.4484168/0.12518962n 0.46942704/0.1074352n
R_load = 50
[Rising Waveform]
R_fixture = 50
V_fixture = 1.5001
V_fixture_min = 1.425
V_fixture_max = 1.575
0s        937.3mV    893.2mV    997.8mV
88.24ps   941.8mV    896.9mV    1.011V
126.8ps   940.2mV    898.8mV    1.276V
153.9ps   948.6mV    897.2mV    1.401V
173.8ps   1.019V     897.2mV    1.457V
213.3ps   1.259V     896.1mV    1.522V
251.8ps   1.383V     950.7mV    1.55V
340.3ps   1.478V     1.288V     1.57V
421ps     1.495V     1.392V     1.574V
1ns       1.5V       1.425V     1.575V
[Rising Waveform]
R_fixture = 50
V_fixture = 0
V_fixture_min = 0
V_fixture_max = 0
77.14ps   0V         0V         0V
100.7ps   3.561mV    3.071mV    4.638mV
136.3ps   0V         4.891mV    287.8mV
180.8ps   0V         2.115mV    461.2mV
219.3ps   270.6mV    0V         524.9mV
248.2ps   397.9mV    -6.472mV   549.4mV
288.4ps   488.9mV    0V         565.5mV
363.1ps   547.8mV    376.8mV    575.3mV
441.8ps   562.2mV    502.5mV    577.8mV
1.077ns   566.5mV    541.4mV    578.6mV
[Falling Waveform]
R_fixture = 50
V_fixture = 1.5001
V_fixture_min = 1.425
V_fixture_max = 1.575
0s        1.501V     1.426V     1.575V
93.23ps   1.495V     1.419V     1.566V
136.5ps   1.498V     1.419V     1.297V
165.3ps   1.494V     1.421V     1.168V
218.3ps   1.213V     1.423V     1.057V
254.3ps   1.08V      1.428V     1.025V
286.9ps   1.015V     1.369V     1.011V
364.5ps   954.1mV    1.054V     1V
451.8ps   939.9mV    928mV      997.5mV
1ns       936.6mV    892.7mV    997mV
[Falling Waveform]
R_fixture = 50
V_fixture = 0
V_fixture_min = 0
V_fixture_max = 0
77.14ps   567.2mV    541.1mV    578.3mV
104.6ps   561.4mV    537.8mV    532.8mV
142.5ps   566.5mV    535.1mV    281.5mV
166.9ps   557.4mV    537.6mV    169.7mV
224.5ps   250.4mV    541.4mV    51.87mV
253.2ps   143.4mV    545.6mV    28.14mV
284.6ps   77.22mV    488.5mV    14.91mV
368.7ps   15.52mV    134mV      2.958mV
449.4ps   3.428mV    30.02mV    0V
1.077ns   0V         0V         0V
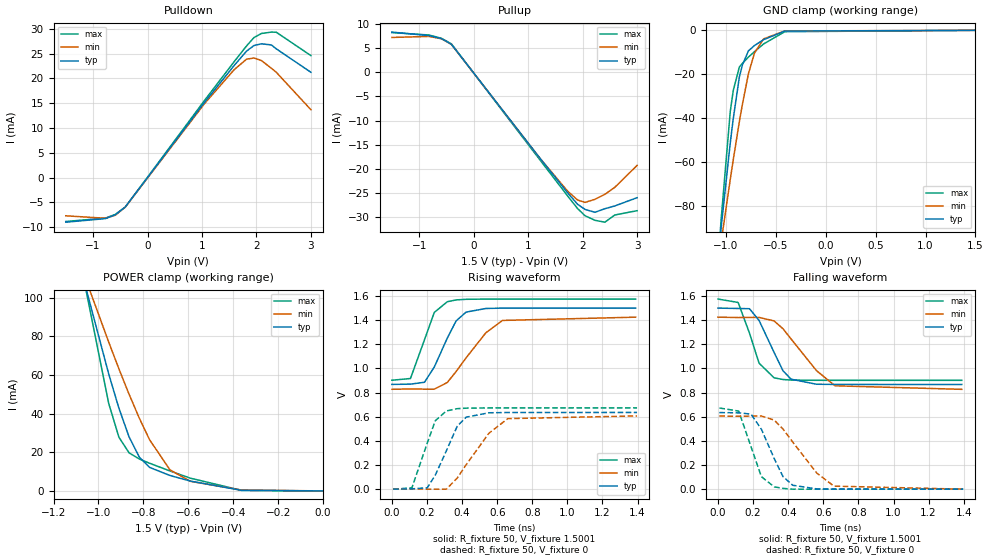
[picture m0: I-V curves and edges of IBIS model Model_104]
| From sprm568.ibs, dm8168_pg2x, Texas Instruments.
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| Model based on original model for BSHTLTCSCDVGPBFZ
|   Sub model SLOW_6MA_5PER_1P5
[model]   Model_104
|[Description]  [1.5V-3-STATE-X-SLOW:6MA, IND, 5%]
|   Slow slew rate (SR[1:0] = "01"), 1.33 * RExt = 0.750 * Iout
|   (I[2:0] = "001"), 6mA nominal with Rext = 50R, ,Industrial
|   temperature range (-40C to 125C, 25C nominal),5% power supply
|   tolerance
|[Input Load]
|[Output Drive] SLOW:6MA
|Voltage   1.5V
|Mode   3-STATE
Model_type   3-state
Polarity   Non-Inverting
Enable   Active-Low
Cref =  15.0000pF
Rref =  100.0000M
Vref =  0V
Vmeas =  0.75005
C_comp   1.5249p   1.4275p   1.6205p
[Model Spec]
[Temperature Range]   25   125   -40
[Voltage Range]   1.5   1.425   1.575
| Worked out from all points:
|   slope of the pulldown table from 0 to 0.225 V, typ, clamps not added: 67.5 ohm
|   slope of the pullup table from 0 to 0.225 V, typ, clamps not added: 67.5 ohm
|   GND clamp passes 1 mA (typ) near -0.47 V on its own axis
|   POWER clamp passes 1 mA (typ) near -0.42 V on its own axis
|   rising waveform, R_fixture 50, V_fixture 1.5001: 20-80 % time 122ps typ, 192ps min, 89.6ps max; typ from 0.868 V to 1.5 V
|   rising waveform, R_fixture 50, V_fixture 0: 20-80 % time 116ps typ, 180ps min, 85.7ps max; typ from 0 V to 0.636 V
|   falling waveform, R_fixture 50, V_fixture 1.5001: 20-80 % time 121ps typ, 201ps min, 88.4ps max; typ from 1.5 V to 0.867 V
|   falling waveform, R_fixture 50, V_fixture 0: 20-80 % time 118ps typ, 194ps min, 85.6ps max; typ from 0.635 V to 0 V
[POWER_clamp]
-1.5V     321.7mA    260.6mA    415.9mA
-1.076V   114.2mA    115.8mA    116.9mA
-1.061V   107.2mA    110.9mA    107.1mA
-954.6mV  60.59mA    77.06mA    45.35mA
-909.2mV  42.85mA    63.21mA    27.81mA
-863.7mV  27.9mA     49.99mA    19.69mA
-818.2mV  17.49mA    37.63mA    16.52mA
-772.8mV  12.19mA    26.53mA    14.33mA
-681.9mV  7.985mA    10.89mA    10.33mA
-590.9mV  5.094mA    4.955mA    6.6mA
-363.7mV  298.5uA    465.2uA    297.6uA
0V        1.518nA    24.08nA    367.8pA
[Pulldown]
-1.5V     -9.02mA    -7.73mA    -8.88mA
-772.8mV  -8.3mA     -8.227mA   -8.195mA
-590.9mV  -7.513mA   -7.616mA   -7.446mA
-409.1mV  -5.951mA   -5.987mA   -5.996mA
1.046V    15.16mA    14.91mA    15.55mA
1.591V    22.62mA    21.77mA    23.39mA
1.818V    25.52mA    23.89mA    26.56mA
1.955V    26.65mA    24.13mA    28.26mA
2.091V    26.99mA    23.61mA    29.08mA
2.273V    26.77mA    22.07mA    29.36mA
2.364V    25.98mA    21.25mA    29.33mA
3V        21.24mA    13.68mA    24.61mA
[Pullup]
-1.5V     8.32mA     7.21mA     8.21mA
-818.2mV  7.591mA    7.42mA     7.72mA
-590.9mV  6.976mA    6.937mA    7.031mA
-409.1mV  5.81mA     5.788mA    5.897mA
1.227V    -17.92mA   -17.93mA   -18.27mA
1.727V    -24.96mA   -24.61mA   -25.61mA
1.909V    -27.32mA   -26.44mA   -28.21mA
2.046V    -28.38mA   -26.92mA   -29.69mA
2.227V    -28.97mA   -26.29mA   -30.63mA
2.409V    -28.23mA   -25.26mA   -31.02mA
2.591V    -27.66mA   -23.81mA   -29.53mA
3V        -25.95mA   -19.28mA   -28.64mA
[GND_clamp]
-1.5V     -310.1mA   -250.5mA   -402.5mA
-1.076V   -103.6mA   -106.2mA   -105.2mA
-1.046V   -89.81mA   -96.36mA   -86.02mA
-954.6mV  -51.22mA   -67.87mA   -36.88mA
-924.3mV  -40.08mA   -58.86mA   -27.29mA
-863.7mV  -21.24mA   -41.56mA   -16.73mA
-833.4mV  -15.8mA    -33.75mA   -15.03mA
-772.8mV  -9.345mA   -19.75mA   -12.19mA
-712.2mV  -6.928mA   -10.35mA   -9.704mA
-621.3mV  -4.261mA   -3.896mA   -6.225mA
-409.1mV  -337.1uA   -289.1uA   -618.9uA
1.5V      1.518nA    257.2nA    299pA
[Ramp]
dV/dt_f   0.506328/0.18100267n   0.478592/0.2864611n   0.538616/0.13758213n
dV/dt_r 0.51069768/0.17221237n  0.4890956/0.26203585n 0.53931933/0.13266518n
R_load = 50
[Rising Waveform]
R_fixture = 50
V_fixture = 1.5001
V_fixture_min = 1.425
V_fixture_max = 1.575
0s        868mV      827.6mV    902.5mV
105.7ps   870.1mV    830.2mV    916.8mV
185.7ps   885.8mV    828.7mV    1.238V
241.4ps   1.012V     828.7mV    1.464V
315.6ps   1.251V     883.7mV    1.553V
365.8ps   1.394V     974.6mV    1.568V
422.8ps   1.467V     1.088V     1.573V
535.5ps   1.497V     1.296V     1.575V
630.4ps   1.5V       1.398V     1.575V
1.389ns   1.5V       1.425V     1.575V
[Rising Waveform]
R_fixture = 50
V_fixture = 0
V_fixture_min = 0
V_fixture_max = 0
7.64ps    0V         0V         0V
113.9ps   2.861mV    2.58mV     11.12mV
201.4ps   11.23mV    0V         381.6mV
247.1ps   115.9mV    0V         566.9mV
310.4ps   318.3mV    0V         648.1mV
372.1ps   521.2mV    91.87mV    666.9mV
423.2ps   596.5mV    202.5mV    671.2mV
552.8ps   632.8mV    463.4mV    673.3mV
660.1ps   635.2mV    584.4mV    673.4mV
1.397ns   635.6mV    607mV      673.5mV
[Falling Waveform]
R_fixture = 50
V_fixture = 1.5001
V_fixture_min = 1.425
V_fixture_max = 1.575
0s        1.5V       1.425V     1.575V
114.5ps   1.497V     1.422V     1.547V
179.2ps   1.495V     1.423V     1.293V
233.8ps   1.398V     1.423V     1.044V
319.2ps   1.134V     1.394V     922.7mV
370.2ps   980.6mV    1.329V     908.5mV
416.4ps   911mV      1.244V     904mV
560.8ps   869.5mV    982.4mV    901.9mV
666.7ps   867.5mV    856.4mV    901.8mV
1.389ns   867.3mV    827.1mV    901.7mV
[Falling Waveform]
R_fixture = 50
V_fixture = 0
V_fixture_min = 0
V_fixture_max = 0
7.64ps    634.7mV    606.3mV    672.6mV
117.9ps   632.4mV    603.9mV    646.7mV
188.1ps   622.1mV    605.6mV    351.1mV
246.9ps   497mV      606mV      103.9mV
320.1ps   254.1mV    572.5mV    19.25mV
369.7ps   105.5mV    499.1mV    6.62mV
425.5ps   32.29mV    390.7mV    0V
563.1ps   2.055mV    132.6mV    0V
660.5ps   0V         25.07mV    0V
1.397ns   0V         0V         0V
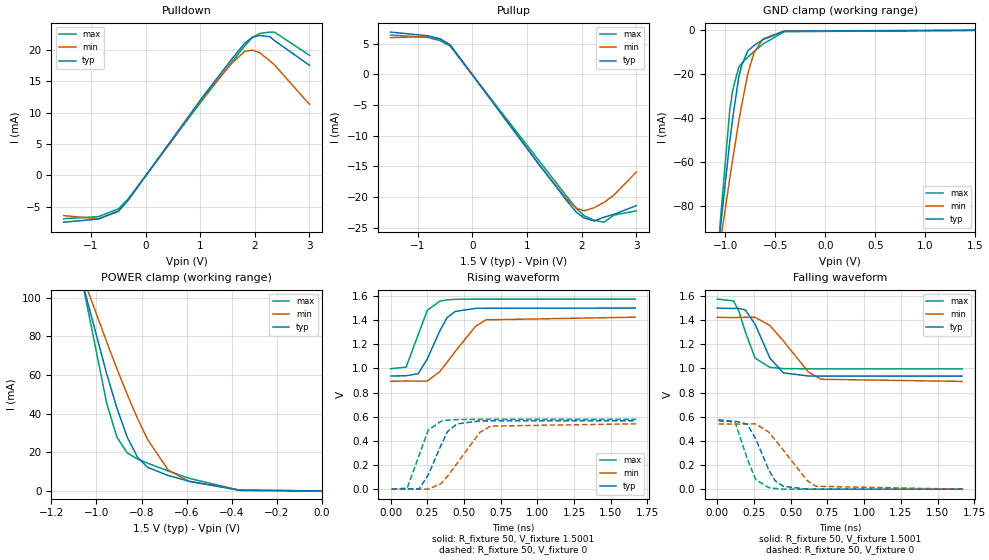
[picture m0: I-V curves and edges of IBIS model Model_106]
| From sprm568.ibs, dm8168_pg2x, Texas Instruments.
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| Model based on original model for BSHTLTCSCDVGPBFZ
|   Sub model SLOW_5MA_5PER_1P5
[model]   Model_106
|[Description]  [1.5V-3-STATE-X-SLOW:5MA, IND, 5%]
|   Slow slew rate (SR[1:0] = "01"), 1.60 * RExt = 0.625 * Iout
|   (I[2:0] = "000"), 5mA nominal with Rext = 50R, ,Industrial
|   temperature range (-40C to 125C, 25C nominal),5% power supply
|   tolerance
|[Input Load]
|[Output Drive] SLOW:5MA
|Voltage   1.5V
|Mode   3-STATE
Model_type   3-state
Polarity   Non-Inverting
Enable   Active-Low
Cref =  15.0000pF
Rref =  100.0000M
Vref =  0V
Vmeas =  0.75005
C_comp   1.5249p   1.4275p   1.6205p
[Model Spec]
[Temperature Range]   25   125   -40
[Voltage Range]   1.5   1.425   1.575
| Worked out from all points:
|   slope of the pulldown table from 0 to 0.225 V, typ, clamps not added: 81.7 ohm
|   slope of the pullup table from 0 to 0.225 V, typ, clamps not added: 81.7 ohm
|   GND clamp passes 1 mA (typ) near -0.47 V on its own axis
|   POWER clamp passes 1 mA (typ) near -0.42 V on its own axis
|   rising waveform, R_fixture 50, V_fixture 1.5001: 20-80 % time 128ps typ, 205ps min, 93.2ps max; typ from 0.937 V to 1.5 V
|   rising waveform, R_fixture 50, V_fixture 0: 20-80 % time 121ps typ, 193ps min, 89.2ps max; typ from 0 V to 0.566 V
|   falling waveform, R_fixture 50, V_fixture 1.5001: 20-80 % time 126ps typ, 213ps min, 92.6ps max; typ from 1.5 V to 0.937 V
|   falling waveform, R_fixture 50, V_fixture 0: 20-80 % time 122ps typ, 206ps min, 89.1ps max; typ from 0.566 V to 0 V
[POWER_clamp]
-1.5V     321.7mA    260.6mA    415.9mA
-1.076V   114.2mA    115.8mA    116.9mA
-1.061V   107.2mA    110.9mA    107.1mA
-954.6mV  60.59mA    77.06mA    45.35mA
-909.2mV  42.85mA    63.21mA    27.81mA
-863.7mV  27.9mA     49.99mA    19.69mA
-818.2mV  17.49mA    37.63mA    16.52mA
-772.8mV  12.19mA    26.53mA    14.33mA
-681.9mV  7.985mA    10.89mA    10.33mA
-590.9mV  5.094mA    4.955mA    6.6mA
-363.7mV  298.5uA    465.2uA    297.6uA
0V        1.518nA    24.08nA    367.8pA
[Pulldown]
-1.5V     -7.45mA    -6.4mA     -6.9mA
-863.7mV  -6.95mA    -6.903mA   -6.565mA
-500mV    -5.682mA   -5.758mA   -5.339mA
-318.2mV  -3.897mA   -3.924mA   -3.728mA
1.046V    12.53mA    12.35mA    12.1mA
1.591V    18.69mA    18.02mA    18.2mA
1.818V    21.09mA    19.78mA    20.66mA
1.955V    22.02mA    19.97mA    21.99mA
2.091V    22.3mA     19.54mA    22.62mA
2.273V    22.11mA    18.26mA    22.84mA
2.364V    21.46mA    17.58mA    22.81mA
3V        17.55mA    11.32mA    19.14mA
[Pullup]
-1.5V     6.87mA     5.96mA     6.38mA
-818.2mV  6.271mA    6.141mA    6.005mA
-590.9mV  5.763mA    5.741mA    5.469mA
-409.1mV  4.8mA      4.791mA    4.587mA
1.227V    -14.81mA   -14.84mA   -14.21mA
1.727V    -20.63mA   -20.37mA   -19.92mA
1.909V    -22.57mA   -21.88mA   -21.95mA
2.046V    -23.45mA   -22.28mA   -23.09mA
2.227V    -23.93mA   -21.76mA   -23.82mA
2.409V    -23.32mA   -20.9mA    -24.13mA
2.591V    -22.85mA   -19.7mA    -22.97mA
3V        -21.43mA   -15.95mA   -22.28mA
[GND_clamp]
-1.5V     -310.1mA   -250.5mA   -402.5mA
-1.076V   -103.6mA   -106.2mA   -105.2mA
-1.046V   -89.81mA   -96.36mA   -86.02mA
-954.6mV  -51.22mA   -67.87mA   -36.88mA
-924.3mV  -40.08mA   -58.86mA   -27.29mA
-863.7mV  -21.24mA   -41.56mA   -16.73mA
-833.4mV  -15.8mA    -33.75mA   -15.03mA
-772.8mV  -9.345mA   -19.75mA   -12.19mA
-712.2mV  -6.928mA   -10.35mA   -9.704mA
-621.3mV  -4.261mA   -3.896mA   -6.225mA
-409.1mV  -337.1uA   -289.1uA   -618.9uA
1.5V      1.518nA    257.2nA    299pA
[Ramp]
dV/dt_f   0.450848/0.19017444n   0.425896/0.29967918n   0.462408/0.14623408n
dV/dt_r 0.45462936/0.18116667n 0.43605976/0.27543752n 0.46290288/0.14136747n
R_load = 50
[Rising Waveform]
R_fixture = 50
V_fixture = 1.5001
V_fixture_min = 1.425
V_fixture_max = 1.575
0s        937.3mV    893.3mV    997.8mV
106.1ps   939.7mV    896mV      1.011V
188.4ps   956.6mV    894.6mV    1.279V
250.1ps   1.078V     895.3mV    1.481V
334.8ps   1.309V     973.3mV    1.557V
384.6ps   1.421V     1.05V      1.568V
440.3ps   1.472V     1.14V      1.573V
578.1ps   1.498V     1.348V     1.575V
650.5ps   1.499V     1.403V     1.575V
1.667ns   1.5V       1.425V     1.575V
[Rising Waveform]
R_fixture = 50
V_fixture = 0
V_fixture_min = 0
V_fixture_max = 0
7.64ps    0V         0V         0V
113.3ps   3.085mV    2.778mV    8.395mV
193.6ps   0V         0V         276.5mV
256.8ps   117.6mV    0V         489.6mV
344.7ps   366.7mV    46.35mV    563.4mV
389.5ps   479.4mV    108mV      572.2mV
453.4ps   541mV      214mV      576.7mV
608.2ps   564.9mV    470.2mV    578.4mV
682ps     566mV      522.5mV    578.5mV
1.674ns   566.5mV    541.4mV    578.6mV
[Falling Waveform]
R_fixture = 50
V_fixture = 1.5001
V_fixture_min = 1.425
V_fixture_max = 1.575
0s        1.5V       1.424V     1.575V
109.7ps   1.497V     1.421V     1.56V
146.2ps   1.498V     1.423V     1.476V
190.6ps   1.485V     1.424V     1.303V
256.8ps   1.366V     1.424V     1.086V
358.1ps   1.086V     1.356V     1.009V
449.7ps   963.4mV    1.228V     998.8mV
620.5ps   937.6mV    969.8mV    997.1mV
705.7ps   936.8mV    910.5mV    997mV
1.667ns   936.6mV    892.7mV    997mV
[Falling Waveform]
R_fixture = 50
V_fixture = 0
V_fixture_min = 0
V_fixture_max = 0
7.64ps    565.9mV    540.6mV    577.7mV
121.8ps   562.9mV    538.5mV    551.7mV
203.4ps   538.2mV    539.9mV    252.5mV
260.7ps   418mV      541.4mV    79.53mV
350.4ps   159.2mV    472.7mV    12.64mV
393.9ps   69.5mV     407.6mV    5.459mV
449.1ps   23.77mV    323.2mV    0V
611.8ps   0V         71.46mV    0V
672.7ps   0V         23.9mV     0V
1.674ns   0V         0V         0V
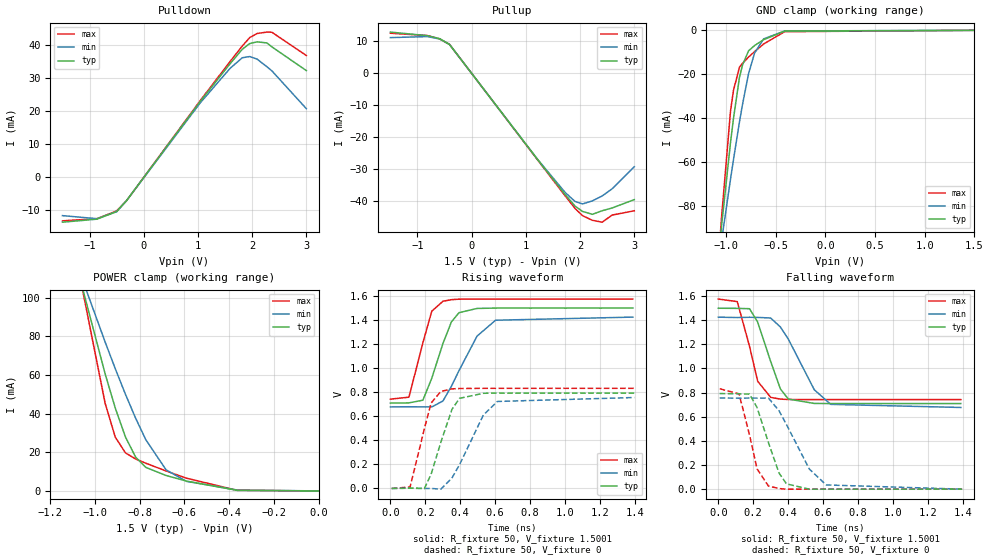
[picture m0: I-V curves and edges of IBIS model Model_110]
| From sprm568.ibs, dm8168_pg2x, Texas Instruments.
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| Model based on original model for BSHTLTCSCDVGPBFZ
|   Sub model SLOW_9MA_5PER_1P5
[model]   Model_110
|[Description]  [1.5V-3-STATE-X-SLOW:9MA, IND, 5%]
|   Slow slew rate (SR[1:0] = "01"), 0.88 * RExt = 1.125 * Iout
|   (I[2:0] = "100"), 9mA nominal with Rext = 50R, ,Industrial
|   temperature range (-40C to 125C, 25C nominal),5% power supply
|   tolerance
|[Input Load]
|[Output Drive] SLOW:9MA
|Voltage   1.5V
|Mode   3-STATE
Model_type   3-state
Polarity   Non-Inverting
Enable   Active-Low
Cref =  15.0000pF
Rref =  100.0000M
Vref =  0V
Vmeas =  0.75005
C_comp   1.5249p   1.4275p   1.6205p
[Model Spec]
[Temperature Range]   25   125   -40
[Voltage Range]   1.5   1.425   1.575
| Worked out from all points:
|   slope of the pulldown table from 0 to 0.225 V, typ, clamps not added: 44.4 ohm
|   slope of the pullup table from 0 to 0.225 V, typ, clamps not added: 44.4 ohm
|   GND clamp passes 1 mA (typ) near -0.47 V on its own axis
|   POWER clamp passes 1 mA (typ) near -0.42 V on its own axis
|   rising waveform, R_fixture 50, V_fixture 1.5001: 20-80 % time 109ps typ, 159ps min, 78.7ps max; typ from 0.71 V to 1.5 V
|   rising waveform, R_fixture 50, V_fixture 0: 20-80 % time 104ps typ, 148ps min, 75.9ps max; typ from 0 V to 0.793 V
|   falling waveform, R_fixture 50, V_fixture 1.5001: 20-80 % time 109ps typ, 159ps min, 78.7ps max; typ from 1.5 V to 0.709 V
|   falling waveform, R_fixture 50, V_fixture 0: 20-80 % time 108ps typ, 161ps min, 76.4ps max; typ from 0.792 V to 0 V
[POWER_clamp]
-1.5V     321.7mA    260.6mA    415.9mA
-1.076V   114.2mA    115.8mA    116.9mA
-1.061V   107.2mA    110.9mA    107.1mA
-954.6mV  60.59mA    77.06mA    45.35mA
-909.2mV  42.85mA    63.21mA    27.81mA
-863.7mV  27.9mA     49.99mA    19.69mA
-818.2mV  17.49mA    37.63mA    16.52mA
-772.8mV  12.19mA    26.53mA    14.33mA
-681.9mV  7.985mA    10.89mA    10.33mA
-590.9mV  5.094mA    4.955mA    6.6mA
-363.7mV  298.5uA    465.2uA    297.6uA
0V        1.518nA    24.08nA    367.8pA
[Pulldown]
-1.5V     -13.72mA   -11.73mA   -13.31mA
-863.7mV  -12.8mA    -12.65mA   -12.66mA
-500mV    -10.46mA   -10.55mA   -10.29mA
-318.2mV  -7.172mA   -7.186mA   -7.182mA
1.046V    23.05mA    22.61mA    23.31mA
1.591V    34.39mA    33mA       35.06mA
1.818V    38.82mA    36.24mA    39.81mA
1.955V    40.55mA    36.61mA    42.37mA
2.091V    41.08mA    35.83mA    43.61mA
2.273V    40.74mA    33.5mA     44.04mA
2.364V    39.55mA    32.26mA    43.99mA
3V        32.34mA    20.77mA    36.92mA
[Pullup]
-1.5V     12.66mA    10.94mA    12.31mA
-818.2mV  11.55mA    11.26mA    11.58mA
-590.9mV  10.61mA    10.52mA    10.54mA
-409.1mV  8.836mA    8.777mA    8.84mA
1.227V    -27.25mA   -27.19mA   -27.38mA
1.727V    -37.96mA   -37.32mA   -38.38mA
1.909V    -41.55mA   -40.1mA    -42.29mA
2.046V    -43.18mA   -40.84mA   -44.51mA
2.227V    -44.08mA   -39.9mA    -45.94mA
2.409V    -42.96mA   -38.35mA   -46.53mA
2.591V    -42.11mA   -36.14mA   -44.31mA
3V        -39.5mA    -29.28mA   -42.98mA
[GND_clamp]
-1.5V     -310.1mA   -250.5mA   -402.5mA
-1.076V   -103.6mA   -106.2mA   -105.2mA
-1.046V   -89.81mA   -96.36mA   -86.02mA
-954.6mV  -51.22mA   -67.87mA   -36.88mA
-924.3mV  -40.08mA   -58.86mA   -27.29mA
-863.7mV  -21.24mA   -41.56mA   -16.73mA
-833.4mV  -15.8mA    -33.75mA   -15.03mA
-772.8mV  -9.345mA   -19.75mA   -12.19mA
-712.2mV  -6.928mA   -10.35mA   -9.704mA
-621.3mV  -4.261mA   -3.896mA   -6.225mA
-409.1mV  -337.1uA   -289.1uA   -618.9uA
1.5V      1.518nA    257.2nA    299pA
[Ramp]
dV/dt_f   0.632752/0.15851914n   0.5992/0.24547647n   0.666584/0.12022051n
dV/dt_r  0.6390308/0.15258712n 0.61063504/0.23050864n 0.66840112/0.11552235n
R_load = 50
[Rising Waveform]
R_fixture = 50
V_fixture = 1.5001
V_fixture_min = 1.425
V_fixture_max = 1.575
0s        709.9mV    677.9mV    742.7mV
106.3ps   711.5mV    679.5mV    759.1mV
186.1ps   733.7mV    678.2mV    1.211V
237.1ps   917mV      678mV      1.474V
301.3ps   1.206V     727.4mV    1.557V
349.5ps   1.385V     849.8mV    1.57V
393.2ps   1.462V     980.4mV    1.574V
496.5ps   1.497V     1.267V     1.575V
602.5ps   1.5V       1.399V     1.575V
1.389ns   1.5V       1.425V     1.575V
[Rising Waveform]
R_fixture = 50
V_fixture = 0
V_fixture_min = 0
V_fixture_max = 0
7.64ps    0V         0V         0V
112.7ps   2.23mV     2.121mV    11.74mV
195.1ps   0V         0V         498.5mV
233.4ps   118.9mV    0V         710.5mV
288.9ps   383.8mV    -6mV       806.7mV
352.8ps   658.1mV    87.05mV    828mV
396ps     749.4mV    197.2mV    831.1mV
532.6ps   791.5mV    610.6mV    832.6mV
613.1ps   792.7mV    723.4mV    832.7mV
1.397ns   793mV      756.2mV    832.8mV
[Falling Waveform]
R_fixture = 50
V_fixture = 1.5001
V_fixture_min = 1.425
V_fixture_max = 1.575
0s        1.499V     1.425V     1.575V
108.5ps   1.498V     1.422V     1.554V
179.1ps   1.495V     1.424V     1.182V
225.5ps   1.384V     1.423V     894.3mV
299.8ps   1.059V     1.418V     760.6mV
355.6ps   830.6mV    1.344V     746mV
401.2ps   746.6mV    1.243V     743.1mV
549.7ps   710.1mV    823.9mV    742mV
644.4ps   709.4mV    702.5mV    742mV
1.389ns   709.3mV    676.9mV    741.9mV
[Falling Waveform]
R_fixture = 50
V_fixture = 0
V_fixture_min = 0
V_fixture_max = 0
7.64ps    792.2mV    755.8mV    831.9mV
118.8ps   790.2mV    753.7mV    790mV
179.1ps   787.4mV    755mV      446.9mV
222ps     676.2mV    754.6mV    168.2mV
287.4ps   384.9mV    754.5mV    25.75mV
347.5ps   134.4mV    650.3mV    5.138mV
390.8ps   43.61mV    534.6mV    0V
521.3ps   0V         166.9mV    0V
618.1ps   0V         34.96mV    0V
1.397ns   0V         0V         0V
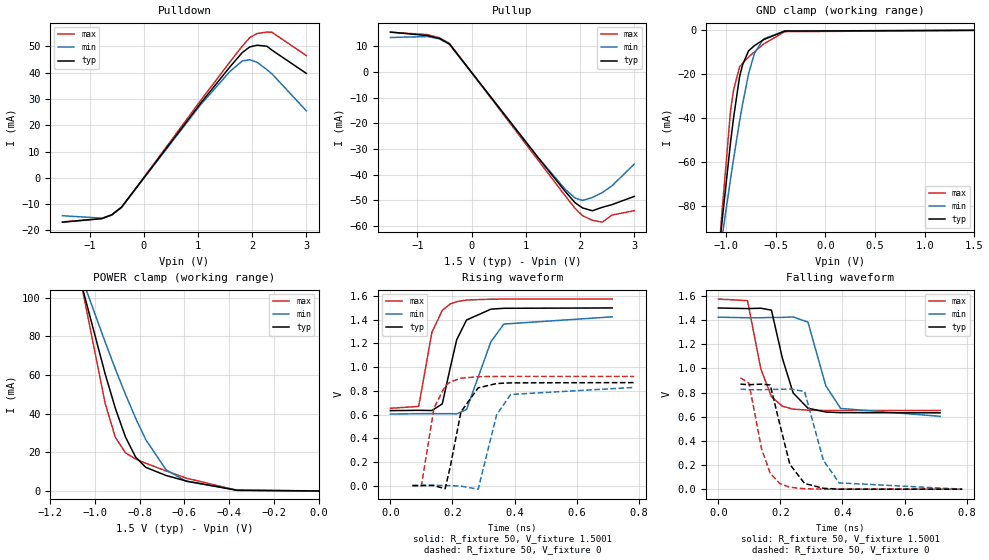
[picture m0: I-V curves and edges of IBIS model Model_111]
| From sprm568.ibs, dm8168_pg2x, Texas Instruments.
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| Model based on original model for BSHTLTCSCDVGPBFZ
|   Sub model FASTEST_11MA_5PER_1P5
[model]   Model_111
|[Description]  [1.5V-3-STATE-X-FASTEST:11MA, IND, 5%]
|   Fastest slew rate (SR[1:0] = "00"), 0.73 * RExt = 1.325 * Iout
|   (I[2:0] = "110"), 11mA nominal with Rext = 50R, ,Industrial
|   temperature range (-40C to 125C, 25C nominal),5% power supply
|   tolerance
|[Input Load]
|[Output Drive] FASTEST:11MA
|Voltage   1.5V
|Mode   3-STATE
Model_type   3-state
Polarity   Non-Inverting
Enable   Active-Low
Cref =  15.0000pF
Rref =  100.0000M
Vref =  0V
Vmeas =  0.75005
C_comp   1.5249p   1.4275p   1.6205p
[Model Spec]
[Temperature Range]   25   125   -40
[Voltage Range]   1.5   1.425   1.575
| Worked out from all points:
|   slope of the pulldown table from 0 to 0.225 V, typ, clamps not added: 36.2 ohm
|   slope of the pullup table from 0 to 0.225 V, typ, clamps not added: 36.1 ohm
|   GND clamp passes 1 mA (typ) near -0.47 V on its own axis
|   POWER clamp passes 1 mA (typ) near -0.42 V on its own axis
|   rising waveform, R_fixture 50, V_fixture 1.5001: 20-80 % time 47.4ps typ, 62.2ps min, 42.6ps max; typ from 0.633 V to 1.5 V
|   rising waveform, R_fixture 50, V_fixture 0: 20-80 % time 45ps typ, 48.5ps min, 41.3ps max; typ from 0 V to 0.87 V
|   falling waveform, R_fixture 50, V_fixture 1.5001: 20-80 % time 50.4ps typ, 55.3ps min, 47.9ps max; typ from 1.5 V to 0.632 V
|   falling waveform, R_fixture 50, V_fixture 0: 20-80 % time 48.9ps typ, 51.9ps min, 46.6ps max; typ from 0.87 V to 0 V
[POWER_clamp]
-1.5V     321.7mA    260.6mA    415.9mA
-1.076V   114.2mA    115.8mA    116.9mA
-1.061V   107.2mA    110.9mA    107.1mA
-954.6mV  60.59mA    77.06mA    45.35mA
-909.2mV  42.85mA    63.21mA    27.81mA
-863.7mV  27.9mA     49.99mA    19.69mA
-818.2mV  17.49mA    37.63mA    16.52mA
-772.8mV  12.19mA    26.53mA    14.33mA
-681.9mV  7.985mA    10.89mA    10.33mA
-590.9mV  5.094mA    4.955mA    6.6mA
-363.7mV  298.5uA    465.2uA    297.6uA
0V        1.518nA    24.08nA    367.8pA
[Pulldown]
-1.5V     -16.86mA   -14.4mA    -16.76mA
-772.8mV  -15.51mA   -15.32mA   -15.47mA
-590.9mV  -14.04mA   -14.17mA   -14.06mA
-409.1mV  -11.11mA   -11.14mA   -11.31mA
1.046V    28.3mA     27.74mA    29.33mA
1.591V    42.23mA    40.49mA    44.13mA
1.818V    47.67mA    44.47mA    50.1mA
1.955V    49.8mA     44.93mA    53.33mA
2.091V    50.46mA    43.98mA    54.91mA
2.273V    50.06mA    41.13mA    55.45mA
2.364V    48.6mA     39.6mA     55.4mA
3V        39.74mA    25.5mA     46.51mA
[Pullup]
-1.5V     15.55mA    13.43mA    15.5mA
-818.2mV  14.19mA    13.81mA    14.58mA
-590.9mV  13.04mA    12.91mA    13.28mA
-409.1mV  10.85mA    10.77mA    11.13mA
1.227V    -33.46mA   -33.35mA   -34.46mA
1.727V    -46.61mA   -45.78mA   -48.31mA
1.909V    -51.03mA   -49.2mA    -53.23mA
2.046V    -53.04mA   -50.12mA   -56.04mA
2.227V    -54.15mA   -48.98mA   -57.84mA
2.409V    -52.79mA   -47.07mA   -58.6mA
2.591V    -51.74mA   -44.37mA   -55.8mA
3V        -48.54mA   -35.95mA   -54.13mA
[GND_clamp]
-1.5V     -310.1mA   -250.5mA   -402.5mA
-1.076V   -103.6mA   -106.2mA   -105.2mA
-1.046V   -89.81mA   -96.36mA   -86.02mA
-954.6mV  -51.22mA   -67.87mA   -36.88mA
-924.3mV  -40.08mA   -58.86mA   -27.29mA
-863.7mV  -21.24mA   -41.56mA   -16.73mA
-833.4mV  -15.8mA    -33.75mA   -15.03mA
-772.8mV  -9.345mA   -19.75mA   -12.19mA
-712.2mV  -6.928mA   -10.35mA   -9.704mA
-621.3mV  -4.261mA   -3.896mA   -6.225mA
-409.1mV  -337.1uA   -289.1uA   -618.9uA
1.5V      1.518nA    257.2nA    299pA
[Ramp]
dV/dt_f   0.699072/80.970667p   0.661384/90.385575p   0.741344/75.25332p
dV/dt_r  0.7219976/73.487494p  0.6969584/80.120301p   0.757716/66.906506p
R_load = 50
[Rising Waveform]
R_fixture = 50
V_fixture = 1.5001
V_fixture_min = 1.425
V_fixture_max = 1.575
0s        632.9mV    604.1mV    652.5mV
91.25ps   635.4mV    606.7mV    668.9mV
133.6ps   633.9mV    607.6mV    1.293V
167.1ps   689.4mV    607.1mV    1.48V
192.9ps   995.9mV    607mV      1.534V
213.5ps   1.231V     605.2mV    1.553V
245.2ps   1.398V     642.4mV    1.567V
324.1ps   1.49V      1.217V     1.574V
365.6ps   1.497V     1.364V     1.575V
714.3ps   1.5V       1.425V     1.575V
[Rising Waveform]
R_fixture = 50
V_fixture = 0
V_fixture_min = 0
V_fixture_max = 0
71.21ps   0V         0V         0V
99.79ps   0V         2.325mV    -3.356mV
140.4ps   0V         2.323mV    654.3mV
176.4ps   -27.05mV   0V         840.8mV
193.1ps   162.7mV    0V         875.7mV
227.4ps   623.7mV    -4.977mV   906.9mV
282.8ps   825.3mV    -30.37mV   919.4mV
342.1ps   861.8mV    597.1mV    921.8mV
387.3ps   867.3mV    769.4mV    922.2mV
785.5ps   869.6mV    828.9mV    922.5mV
[Falling Waveform]
R_fixture = 50
V_fixture = 1.5001
V_fixture_min = 1.425
V_fixture_max = 1.575
0s        1.501V     1.425V     1.575V
94.02ps   1.496V     1.42V      1.562V
137.1ps   1.499V     1.42V      994.6mV
171.2ps   1.483V     1.423V     766.1mV
206.3ps   1.086V     1.423V     687mV
241ps     797.2mV    1.427V     663.3mV
288.8ps   670.7mV    1.384V     654.5mV
346.3ps   639.1mV    856.1mV    652.4mV
394ps     633.9mV    668.8mV    652.1mV
714.3ps   632.3mV    603.6mV    651.8mV
[Falling Waveform]
R_fixture = 50
V_fixture = 0
V_fixture_min = 0
V_fixture_max = 0
71.21ps   869.9mV    829.2mV    922.3mV
98.61ps   865.4mV    824.4mV    878.8mV
139.3ps   870.2mV    823.5mV    334.9mV
167.3ps   862.7mV    826.4mV    131.7mV
197.5ps   543.4mV    826.9mV    46.99mV
230.5ps   205.4mV    830.2mV    15.59mV
277.8ps   47.3mV     809.4mV    3.682mV
338.4ps   7.301mV    238.9mV    0V
389.2ps   0V         52.21mV    0V
785.5ps   0V         0V         0V
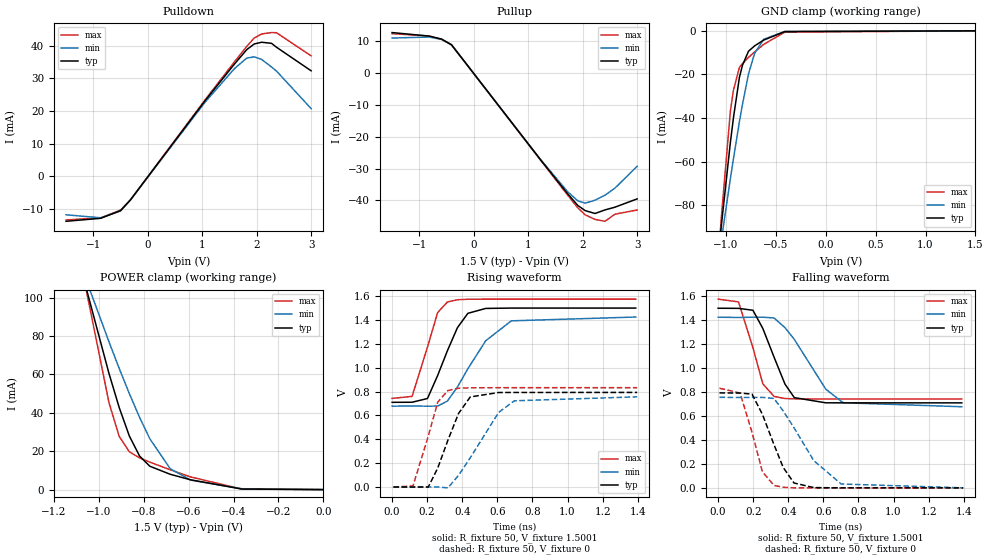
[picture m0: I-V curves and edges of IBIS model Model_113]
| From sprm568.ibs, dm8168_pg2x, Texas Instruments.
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| Model based on original model for BSHTLTCSCDVGPBFZ
|   Sub model SLOWEST_9MA_5PER_1P5
[model]   Model_113
|[Description]  [1.5V-3-STATE-X-SLOWEST:9MA, IND, 5%]
|   Slowest slew rate (SR[1:0] = "11"), 0.88 * RExt = 1.125 * Iout
|   (I[2:0] = "100"), 9mA nominal with Rext = 50R, ,Industrial
|   temperature range (-40C to 125C, 25C nominal),5% power supply
|   tolerance
|[Input Load]
|[Output Drive] SLOWEST:9MA
|Voltage   1.5V
|Mode   3-STATE
Model_type   3-state
Polarity   Non-Inverting
Enable   Active-Low
Cref =  15.0000pF
Rref =  100.0000M
Vref =  0V
Vmeas =  0.75005
C_comp   1.5249p   1.4275p   1.6205p
[Model Spec]
[Temperature Range]   25   125   -40
[Voltage Range]   1.5   1.425   1.575
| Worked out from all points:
|   slope of the pulldown table from 0 to 0.225 V, typ, clamps not added: 44.4 ohm
|   slope of the pullup table from 0 to 0.225 V, typ, clamps not added: 44.4 ohm
|   GND clamp passes 1 mA (typ) near -0.47 V on its own axis
|   POWER clamp passes 1 mA (typ) near -0.42 V on its own axis
|   rising waveform, R_fixture 50, V_fixture 1.5001: 20-80 % time 133ps typ, 197ps min, 93.4ps max; typ from 0.71 V to 1.5 V
|   rising waveform, R_fixture 50, V_fixture 0: 20-80 % time 126ps typ, 186ps min, 90.8ps max; typ from 0 V to 0.793 V
|   falling waveform, R_fixture 50, V_fixture 1.5001: 20-80 % time 128ps typ, 192ps min, 90.2ps max; typ from 1.5 V to 0.709 V
|   falling waveform, R_fixture 50, V_fixture 0: 20-80 % time 128ps typ, 197ps min, 88.3ps max; typ from 0.793 V to 0 V
[POWER_clamp]
-1.5V     321.7mA    260.6mA    415.9mA
-1.076V   114.2mA    115.8mA    116.9mA
-1.061V   107.2mA    110.9mA    107.1mA
-954.6mV  60.59mA    77.06mA    45.35mA
-909.2mV  42.85mA    63.21mA    27.81mA
-863.7mV  27.9mA     49.99mA    19.69mA
-818.2mV  17.49mA    37.63mA    16.52mA
-772.8mV  12.19mA    26.53mA    14.33mA
-681.9mV  7.985mA    10.89mA    10.33mA
-590.9mV  5.094mA    4.955mA    6.6mA
-363.7mV  298.5uA    465.2uA    297.6uA
0V        1.518nA    24.08nA    367.8pA
[Pulldown]
-1.5V     -13.72mA   -11.73mA   -13.31mA
-863.7mV  -12.8mA    -12.65mA   -12.66mA
-500mV    -10.46mA   -10.55mA   -10.29mA
-318.2mV  -7.172mA   -7.186mA   -7.182mA
1.046V    23.05mA    22.61mA    23.31mA
1.591V    34.39mA    33mA       35.06mA
1.818V    38.82mA    36.24mA    39.81mA
1.955V    40.55mA    36.61mA    42.37mA
2.091V    41.08mA    35.83mA    43.61mA
2.273V    40.74mA    33.5mA     44.04mA
2.364V    39.55mA    32.26mA    43.99mA
3V        32.34mA    20.77mA    36.92mA
[Pullup]
-1.5V     12.66mA    10.94mA    12.31mA
-818.2mV  11.55mA    11.26mA    11.58mA
-590.9mV  10.61mA    10.52mA    10.54mA
-409.1mV  8.836mA    8.777mA    8.84mA
1.227V    -27.25mA   -27.19mA   -27.38mA
1.727V    -37.96mA   -37.32mA   -38.38mA
1.909V    -41.55mA   -40.1mA    -42.29mA
2.046V    -43.18mA   -40.84mA   -44.51mA
2.227V    -44.08mA   -39.9mA    -45.94mA
2.409V    -42.96mA   -38.35mA   -46.53mA
2.591V    -42.11mA   -36.14mA   -44.31mA
3V        -39.5mA    -29.28mA   -42.98mA
[GND_clamp]
-1.5V     -310.1mA   -250.5mA   -402.5mA
-1.076V   -103.6mA   -106.2mA   -105.2mA
-1.046V   -89.81mA   -96.36mA   -86.02mA
-954.6mV  -51.22mA   -67.87mA   -36.88mA
-924.3mV  -40.08mA   -58.86mA   -27.29mA
-863.7mV  -21.24mA   -41.56mA   -16.73mA
-833.4mV  -15.8mA    -33.75mA   -15.03mA
-772.8mV  -9.345mA   -19.75mA   -12.19mA
-712.2mV  -6.928mA   -10.35mA   -9.704mA
-621.3mV  -4.261mA   -3.896mA   -6.225mA
-409.1mV  -337.1uA   -289.1uA   -618.9uA
1.5V      1.518nA    257.2nA    299pA
[Ramp]
dV/dt_f   0.632912/0.18543928n   0.59944/0.30124073n   0.666584/0.13417172n
dV/dt_r 0.63885392/0.18548444n 0.61071216/0.28637454n 0.66808936/0.13313997n
R_load = 50
[Rising Waveform]
R_fixture = 50
V_fixture = 1.5001
V_fixture_min = 1.425
V_fixture_max = 1.575
0s        709.9mV    677.9mV    742.7mV
113.9ps   710.7mV    678.9mV    759.8mV
201.7ps   742mV      677.8mV    1.173V
259.4ps   934mV      678.4mV    1.462V
315.4ps   1.143V     720.6mV    1.551V
372.5ps   1.336V     838.9mV    1.57V
432ps     1.456V     991.7mV    1.574V
533.7ps   1.497V     1.226V     1.575V
679.4ps   1.5V       1.393V     1.575V
1.389ns   1.5V       1.425V     1.575V
[Rising Waveform]
R_fixture = 50
V_fixture = 0
V_fixture_min = 0
V_fixture_max = 0
7.64ps    0V         0V         0V
118.9ps   0V         0V         8.624mV
206.2ps   0V         0V         426.2mV
259.9ps   158.4mV    0V         711.4mV
318ps     391.9mV    -6.945mV   808.8mV
378.6ps   616.4mV    97.22mV    828mV
445.6ps   755.2mV    245.1mV    831.8mV
607ps     792.2mV    625.1mV    832.7mV
696.9ps   792.8mV    722.7mV    832.7mV
1.397ns   793mV      756.2mV    832.8mV
[Falling Waveform]
R_fixture = 50
V_fixture = 1.5001
V_fixture_min = 1.425
V_fixture_max = 1.575
0s        1.499V     1.424V     1.575V
116ps     1.498V     1.422V     1.552V
198.4ps   1.482V     1.424V     1.17V
254.9ps   1.33V      1.424V     867.8mV
318.8ps   1.091V     1.418V     763.2mV
381.1ps   865.7mV    1.337V     745.6mV
434.3ps   753mV      1.239V     742.8mV
613.9ps   709.7mV    823.1mV    742mV
712.7ps   709.4mV    710.3mV    741.9mV
1.389ns   709.3mV    676.9mV    741.9mV
[Falling Waveform]
R_fixture = 50
V_fixture = 0
V_fixture_min = 0
V_fixture_max = 0
7.64ps    792.6mV    755.6mV    831.9mV
125.3ps   791.1mV    754.2mV    791.3mV
193.1ps   782.5mV    755mV      463.3mV
252.5ps   613.4mV    755mV      134.3mV
318.4ps   360.9mV    746mV      20.31mV
370.9ps   170.4mV    641.9mV    5.004mV
432.6ps   40.5mV     501.6mV    0V
545.2ps   2.261mV    227.1mV    0V
701.6ps   0V         32.13mV    0V
1.397ns   0V         0V         0V
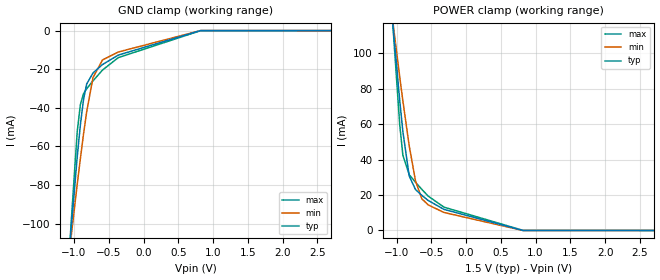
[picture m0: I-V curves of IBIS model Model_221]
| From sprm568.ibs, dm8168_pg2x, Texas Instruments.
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| Model based on original model for BSHTLTCSCDVGPBFZ
|   Sub model REC_HALFTERM_TH_1P5_9MA_10PER_1P5
[model]   Model_221
|[Description]  [1.5V-INPUT-HALFTERM:9MA-X, IND, 10%]
|   Half Thevenin termination (Rth = 100R whith RExt = 50R)
|   (ODT[1:0] = "11") VRef mode, 0.88 * RExt = 1.125 * Iout (I[2:0]
|   = "100"), 9mA nominal with Rext = 50R,Industrial temperature
|   range (-40C to 125C, 25C nominal),10% power supply tolerance
|[Input Load]   HALFTERM:9MA
|[Output Drive]
|Voltage   1.5V
|Mode   INPUT
Model_type   Input
Polarity   Non-Inverting
Vinl =  0.65
Vinh =  1
C_comp   1.5249p   1.4275p   1.6205p
[Model Spec]
Vinl   0.65   0.65   0.65
Vinh   1   1   1
D_overshoot_high 1.95 1.95 1.95
D_overshoot_low -0.3 -0.3 -0.3
D_overshoot_time 1E-9 1E-9 1E-9
S_overshoot_high 1.65 1.65 1.65
S_overshoot_low 0 0 0
[Temperature Range]   25   125   -40
[Voltage Range]   1.5   1.35   1.65
[POWER_clamp]
-1.5V     333.2mA    267.7mA    429.2mA
-1.091V   133.8mA    130mA      140.8mA
-1.045V   112.9mA    115.3mA    111.4mA
-954.5mV  73.5mA     86.87mA    59.79mA
-909.1mV  55.85mA    73.19mA    42.54mA
-818.2mV  30.78mA    47.91mA    31.54mA
-727.3mV  23.13mA    27.98mA    27.24mA
-636.4mV  19.86mA    17.9mA     23.22mA
-545.5mV  16.97mA    14.46mA    19.45mA
-318.2mV  11.92mA    10.17mA    13.18mA
818.2mV   0A         0A         78.03uA
3V        0A         0A         0A
[GND_clamp]
-1.5V     -323.7mA   -259.7mA   -417.7mA
-1.091V   -124.6mA   -122.4mA   -130.2mA
-1.045V   -104mA     -107.8mA   -101.3mA
-954.5mV  -65.48mA   -79.65mA   -52.41mA
-909.1mV  -48.83mA   -66.27mA   -38.32mA
-863.6mV  -35.67mA   -53.6mA    -32.7mA
-818.2mV  -27.64mA   -42mA      -30.12mA
-727.3mV  -21.94mA   -24.33mA   -26.04mA
-590.9mV  -17.59mA   -15.2mA    -20.45mA
-363.6mV  -12.69mA   -11.1mA    -14mA
818.2mV   0A         0A         -79.95uA
3V        0A         0A         0A
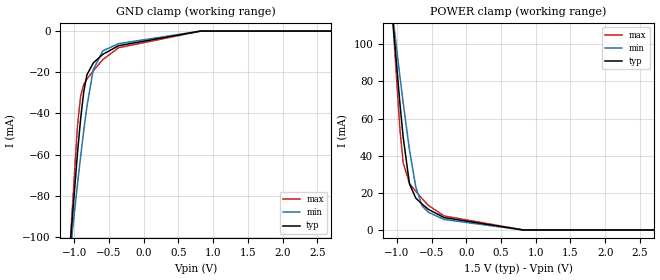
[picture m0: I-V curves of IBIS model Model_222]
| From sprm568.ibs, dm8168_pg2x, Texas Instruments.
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| Model based on original model for BSHTLTCSCDVGPBFZ
|   Sub model REC_HALFTERM_TH_1P5_5MA_10PER_1P5
[model]   Model_222
|[Description]  [1.5V-INPUT-HALFTERM:5MA-X, IND, 10%]
|   Half Thevenin termination (Rth = 100R whith RExt = 50R)
|   (ODT[1:0] = "11") VRef mode, 1.60 * RExt = 0.625 * Iout (I[2:0]
|   = "000"), 5mA nominal with Rext = 50R,Industrial temperature
|   range (-40C to 125C, 25C nominal),10% power supply tolerance
|[Input Load]   HALFTERM:5MA
|[Output Drive]
|Voltage   1.5V
|Mode   INPUT
Model_type   Input
Polarity   Non-Inverting
Vinl =  0.65
Vinh =  1
C_comp   1.5249p   1.4275p   1.6205p
[Model Spec]
Vinl   0.65   0.65   0.65
Vinh   1   1   1
D_overshoot_high 1.95 1.95 1.95
D_overshoot_low -0.3 -0.3 -0.3
D_overshoot_time 1E-9 1E-9 1E-9
S_overshoot_high 1.65 1.65 1.65
S_overshoot_low 0 0 0
[Temperature Range]   25   125   -40
[Voltage Range]   1.5   1.35   1.65
[POWER_clamp]
-1.5V     328.1mA    264.5mA    423.5mA
-1.091V   128.2mA    125.8mA    134.7mA
-1.045V   107.2mA    111mA      105.3mA
-954.5mV  67.76mA    82.41mA    53.6mA
-909.1mV  50.07mA    68.65mA    36.23mA
-818.2mV  24.86mA    43.22mA    25.1mA
-727.3mV  17.16mA    23.16mA    20.83mA
-636.4mV  13.92mA    12.98mA    16.88mA
-545.5mV  11.11mA    9.515mA    13.2mA
-318.2mV  6.661mA    5.634mA    7.561mA
818.2mV   0A         0A         44.94uA
3V        0A         0A         0A
[GND_clamp]
-1.5V     -317.6mA   -255.5mA   -411.2mA
-1.091V   -118.3mA   -117.2mA   -123.6mA
-1.045V   -97.65mA   -102.6mA   -94.7mA
-954.5mV  -59.13mA   -74.29mA   -45.74mA
-909.1mV  -42.46mA   -60.84mA   -31.53mA
-863.6mV  -29.25mA   -48.12mA   -25.85mA
-818.2mV  -21.17mA   -36.47mA   -23.29mA
-727.3mV  -15.48mA   -18.72mA   -19.3mA
-590.9mV  -11.32mA   -9.61mA    -13.89mA
-363.6mV  -7.102mA   -6.11mA    -8.092mA
818.2mV   0A         0A         -45.38uA
3V        0A         0A         0A
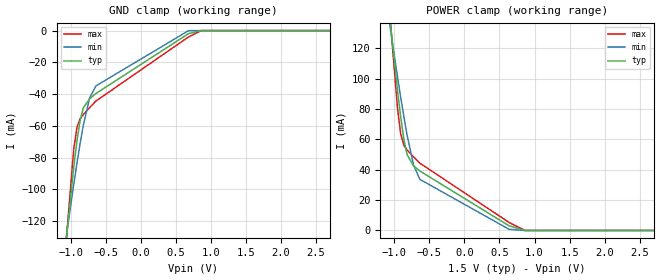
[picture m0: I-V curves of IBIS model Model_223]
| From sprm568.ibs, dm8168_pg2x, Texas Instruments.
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| Model based on original model for BSHTLTCSCDVGPBFZ
|   Sub model REC_FULLTERM_TH_1P5_11MA_10PER_1P5
[model]   Model_223
|[Description]  [1.5V-INPUT-FULLTERM:11MA-X, IND, 10%]
|   FULLTERM, 0.73 * RExt = 1.325 * Iout (I[2:0] = "110"), 11mA
|   nominal with Rext = 50R,Industrial temperature range (-40C to
|   125C, 25C nominal),10% power supply tolerance
|[Input Load]   FULLTERM:11MA
|[Output Drive]
|Voltage   1.5V
|Mode   INPUT
Model_type   Input
Polarity   Non-Inverting
Vinl =  0.65
Vinh =  1
C_comp   1.5249p   1.4275p   1.6205p
[Model Spec]
Vinl   0.65   0.65   0.65
Vinh   1   1   1
D_overshoot_high 1.95 1.95 1.95
D_overshoot_low -0.3 -0.3 -0.3
D_overshoot_time 1E-9 1E-9 1E-9
S_overshoot_high 1.65 1.65 1.65
S_overshoot_low 0 0 0
[Temperature Range]   25   125   -40
[Voltage Range]   1.5   1.35   1.65
[POWER_clamp]
-1.5V     349.9mA    278.1mA    448.4mA
-1.227V   216.5mA    187.5mA    254mA
-1.045V   131.3mA    129.1mA    131.7mA
-954.5mV  92.15mA    101.2mA    80.45mA
-909.1mV  74.65mA    87.74mA    63.62mA
-863.6mV  60.02mA    74.91mA    56.09mA
-818.2mV  50mA       62.9mA     53mA
-727.3mV  42.55mA    43.4mA     48.57mA
-636.4mV  39.16mA    33.67mA    44.34mA
636.4mV   3.066mA    767.5uA    5.292mA
863.6mV   0A         0A         0A
3V        0A         0A         0A
[GND_clamp]
-1.5V     -343.5mA   -273.2mA   -439.6mA
-1.227V   -209.6mA   -182.7mA   -244.6mA
-1.045V   -124.6mA   -124.5mA   -123.2mA
-954.5mV  -86.12mA   -96.84mA   -74.65mA
-909.1mV  -69.56mA   -83.65mA   -60.97mA
-863.6mV  -56.54mA   -71.15mA   -55.52mA
-818.2mV  -48.68mA   -59.7mA    -52.87mA
-727.3mV  -42.91mA   -42.29mA   -48.5mA
-636.4mV  -39.57mA   -34.78mA   -44.32mA
681.8mV   -1.947mA   -60.69uA   -4.03mA
863.6mV   0A         0A         0A
3V        0A         0A         0A
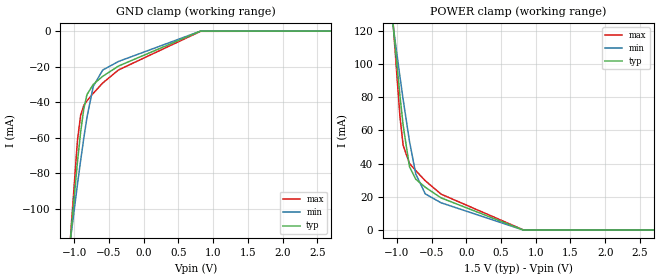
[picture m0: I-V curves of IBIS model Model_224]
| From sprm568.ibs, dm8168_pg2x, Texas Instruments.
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| Model based on original model for BSHTLTCSCDVGPBFZ
|   Sub model REC_FULLTERM_TH_1P5_7MA_10PER_1P5
[model]   Model_224
|[Description]  [1.5V-INPUT-FULLTERM:7MA-X, IND, 10%]
|   FULLTERM, 1.14 * RExt = 0.875 * Iout (I[2:0] = "010"), 7mA
|   nominal with Rext = 50R,Industrial temperature range (-40C to
|   125C, 25C nominal),10% power supply tolerance
|[Input Load]   FULLTERM:7MA
|[Output Drive]
|Voltage   1.5V
|Mode   INPUT
Model_type   Input
Polarity   Non-Inverting
Vinl =  0.65
Vinh =  1
C_comp   1.5249p   1.4275p   1.6205p
[Model Spec]
Vinl   0.65   0.65   0.65
Vinh   1   1   1
D_overshoot_high 1.95 1.95 1.95
D_overshoot_low -0.3 -0.3 -0.3
D_overshoot_time 1E-9 1E-9 1E-9
S_overshoot_high 1.65 1.65 1.65
S_overshoot_low 0 0 0
[Temperature Range]   25   125   -40
[Voltage Range]   1.5   1.35   1.65
[POWER_clamp]
-1.5V     339.6mA    271.6mA    436.9mA
-1.136V   162.1mA    149.8mA    179.3mA
-1.091V   140.8mA    135.1mA    148.9mA
-1.045V   120mA      120.5mA    119.5mA
-954.5mV  80.67mA    92.23mA    68.05mA
-909.1mV  63.08mA    78.65mA    50.97mA
-818.2mV  38.17mA    53.53mA    40.12mA
-727.3mV  30.6mA     33.76mA    35.77mA
-590.9mV  25.77mA    21.77mA    29.69mA
-363.6mV  19.36mA    16.39mA    21.61mA
818.2mV   0A         0A         122.1uA
3V        0A         0A         0A
[GND_clamp]
-1.5V     -331.3mA   -264.8mA   -426.5mA
-1.091V   -132.5mA   -128.5mA   -138.9mA
-1.045V   -111.9mA   -114.1mA   -110mA
-954.5mV  -73.42mA   -86.1mA    -61.31mA
-909.1mV  -56.8mA    -72.79mA   -47.38mA
-863.6mV  -43.7mA    -60.18mA   -41.83mA
-818.2mV  -35.73mA   -48.63mA   -39.22mA
-727.3mV  -30mA      -31.07mA   -35.03mA
-590.9mV  -25.44mA   -21.91mA   -29.19mA
-363.6mV  -19.67mA   -17.09mA   -21.87mA
818.2mV   0A         0A         -126uA
3V        0A         0A         0A
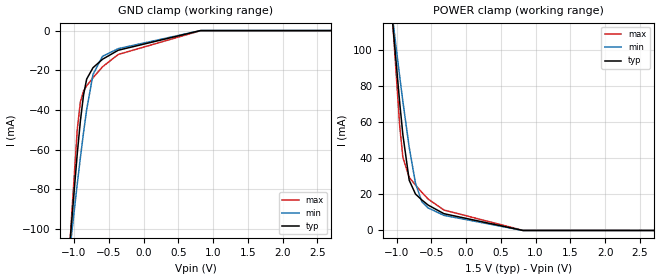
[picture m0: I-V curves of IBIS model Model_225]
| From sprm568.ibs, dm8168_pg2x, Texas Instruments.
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| Model based on original model for BSHTLTCSCDVGPBFZ
|   Sub model REC_HALFTERM_TH_1P5_7MA_10PER_1P5
[model]   Model_225
|[Description]  [1.5V-INPUT-HALFTERM:7MA-X, IND, 10%]
|   Half Thevenin termination (Rth = 100R whith RExt = 50R)
|   (ODT[1:0] = "11") VRef mode, 1.14 * RExt = 0.875 * Iout (I[2:0]
|   = "010"), 7mA nominal with Rext = 50R,Industrial temperature
|   range (-40C to 125C, 25C nominal),10% power supply tolerance
|[Input Load]   HALFTERM:7MA
|[Output Drive]
|Voltage   1.5V
|Mode   INPUT
Model_type   Input
Polarity   Non-Inverting
Vinl =  0.65
Vinh =  1
C_comp   1.5249p   1.4275p   1.6205p
[Model Spec]
Vinl   0.65   0.65   0.65
Vinh   1   1   1
D_overshoot_high 1.95 1.95 1.95
D_overshoot_low -0.3 -0.3 -0.3
D_overshoot_time 1E-9 1E-9 1E-9
S_overshoot_high 1.65 1.65 1.65
S_overshoot_low 0 0 0
[Temperature Range]   25   125   -40
[Voltage Range]   1.5   1.35   1.65
[POWER_clamp]
-1.5V     330.6mA    266.4mA    427.3mA
-1.091V   131mA      128.3mA    138.8mA
-1.045V   110.1mA    113.6mA    109.4mA
-954.5mV  70.63mA    85.08mA    57.73mA
-909.1mV  52.96mA    71.38mA    40.44mA
-818.2mV  27.82mA    46.03mA    29.39mA
-727.3mV  20.14mA    26.05mA    25.1mA
-636.4mV  16.89mA    15.93mA    21.1mA
-545.5mV  14.04mA    12.48mA    17.37mA
-318.2mV  9.289mA    8.355mA    11.31mA
818.2mV   0A         0A         67.01uA
3V        0A         0A         0A
[GND_clamp]
-1.5V     -320.7mA   -258mA     -415.5mA
-1.091V   -121.5mA   -120.3mA   -128mA
-1.045V   -100.8mA   -105.7mA   -99.08mA
-954.5mV  -62.3mA    -77.51mA   -50.19mA
-909.1mV  -45.65mA   -64.1mA    -36.05mA
-863.6mV  -32.46mA   -51.41mA   -30.42mA
-818.2mV  -24.4mA    -39.78mA   -27.84mA
-727.3mV  -18.71mA   -22.09mA   -23.79mA
-590.9mV  -14.46mA   -12.97mA   -18.26mA
-363.6mV  -9.897mA   -9.106mA   -12.03mA
818.2mV   0A         0A         -68.43uA
3V        0A         0A         0A
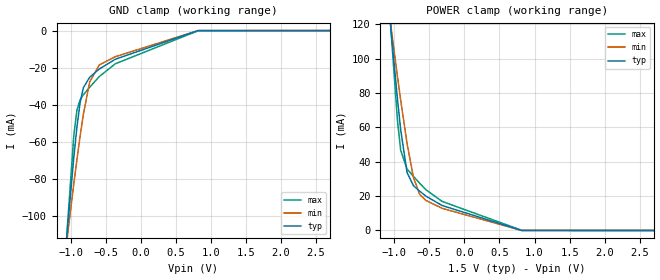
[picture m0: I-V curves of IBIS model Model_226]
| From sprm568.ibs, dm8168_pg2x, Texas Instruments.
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| Model based on original model for BSHTLTCSCDVGPBFZ
|   Sub model REC_HALFTERM_TH_1P5_11MA_10PER_1P5
[model]   Model_226
|[Description]  [1.5V-INPUT-HALFTERM:11MA-X, IND, 10%]
|   Half Thevenin termination (Rth = 100R whith RExt = 50R)
|   (ODT[1:0] = "11") VRef mode, 0.73 * RExt = 1.325 * Iout (I[2:0]
|   = "110"), 11mA nominal with Rext = 50R,Industrial temperature
|   range (-40C to 125C, 25C nominal),10% power supply tolerance
|[Input Load]   HALFTERM:11MA
|[Output Drive]
|Voltage   1.5V
|Mode   INPUT
Model_type   Input
Polarity   Non-Inverting
Vinl =  0.65
Vinh =  1
C_comp   1.5249p   1.4275p   1.6205p
[Model Spec]
Vinl   0.65   0.65   0.65
Vinh   1   1   1
D_overshoot_high 1.95 1.95 1.95
D_overshoot_low -0.3 -0.3 -0.3
D_overshoot_time 1E-9 1E-9 1E-9
S_overshoot_high 1.65 1.65 1.65
S_overshoot_low 0 0 0
[Temperature Range]   25   125   -40
[Voltage Range]   1.5   1.35   1.65
[POWER_clamp]
-1.5V     335.8mA    269.7mA    433.1mA
-1.091V   136.6mA    132.5mA    144.8mA
-1.045V   115.7mA    117.9mA    115.4mA
-954.5mV  76.37mA    89.55mA    63.92mA
-909.1mV  58.74mA    75.92mA    46.76mA
-818.2mV  33.73mA    50.72mA    35.83mA
-727.3mV  26.12mA    30.87mA    31.51mA
-636.4mV  22.83mA    20.86mA    27.44mA
-545.5mV  19.9mA     17.42mA    23.61mA
-318.2mV  14.54mA    12.89mA    16.92mA
818.2mV   0A         0A         100.1uA
3V        0A         0A         0A
[GND_clamp]
-1.5V     -326.8mA   -262.2mA   -422.1mA
-1.091V   -127.8mA   -125.5mA   -134.5mA
-1.045V   -107.2mA   -110.9mA   -105.7mA
-954.5mV  -68.66mA   -82.87mA   -56.86mA
-909.1mV  -52.02mA   -69.53mA   -42.85mA
-863.6mV  -38.88mA   -56.89mA   -37.27mA
-818.2mV  -30.88mA   -45.31mA   -34.67mA
-727.3mV  -25.16mA   -27.7mA    -30.53mA
-590.9mV  -20.73mA   -18.56mA   -24.82mA
-363.6mV  -15.48mA   -14.1mA    -17.93mA
818.2mV   0A         0A         -103uA
3V        0A         0A         0A
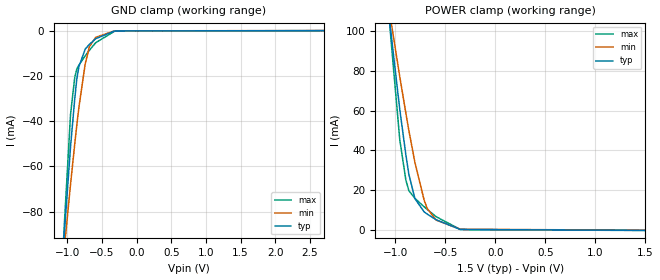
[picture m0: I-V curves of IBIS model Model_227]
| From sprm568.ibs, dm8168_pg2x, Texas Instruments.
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| Model based on original model for BSHTLTCSCDVGPBFZ
|   Sub model REC_NOTERM_PU_ON_1P5_10PER_1P5
[model]   Model_227
|[Description]  [1.5V-INPUT-NOTERM-X, IND, 10%]
|   ODT off (ODT[1:0] = "00") CMOS mode,Industrial temperature range
|   (-40C to 125C, 25C nominal),10% power supply tolerance
|[Input Load]   NOTERM
|[Output Drive]
|Voltage   1.5V
|Mode   INPUT
Model_type   Input
Polarity   Non-Inverting
Vinl =  0.65
Vinh =  1
C_comp   1.5249p   1.4275p   1.6205p
[Model Spec]
Vinl   0.65   0.65   0.65
Vinh   1   1   1
D_overshoot_high 1.95 1.95 1.95
D_overshoot_low -0.3 -0.3 -0.3
D_overshoot_time 1E-9 1E-9 1E-9
S_overshoot_high 1.65 1.65 1.65
S_overshoot_low 0 0 0
[Temperature Range]   25   125   -40
[Voltage Range]   1.5   1.35   1.65
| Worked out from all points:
|   GND clamp passes 1 mA (typ) near -0.46 V on its own axis
|   POWER clamp passes 1 mA (typ) near -0.42 V on its own axis
[POWER_clamp]
-1.5V     321.7mA    260.6mA    415.9mA
-1.076V   114.2mA    115.8mA    116.9mA
-1.045V   100.2mA    105.9mA    97.3mA
-954.5mV  60.67mA    77.09mA    45.46mA
-893.9mV  37.95mA    58.84mA    25.22mA
-863.6mV  27.99mA    50.03mA    19.81mA
-803mV    15.8mA     33.96mA    15.9mA
-712.1mV  9.203mA    15.27mA    11.75mA
-681.8mV  8.071mA    10.94mA    10.44mA
-590.9mV  5.171mA    5.008mA    6.701mA
-348.5mV  279uA      411.2uA    289.4uA
1.5V      -129.9uA   -75.43uA   -210.3uA
[GND_clamp]
-1.5V     -310.1mA   -250.5mA   -402.5mA
-1.076V   -103.6mA   -106.2mA   -105.3mA
-1.045V   -89.82mA   -96.33mA   -86.06mA
-954.5mV  -51.27mA   -67.88mA   -36.99mA
-893.9mV  -30.15mA   -50.1mA    -20.71mA
-863.6mV  -21.31mA   -41.58mA   -16.88mA
-833.3mV  -15.88mA   -33.78mA   -15.19mA
-742.4mV  -8.156mA   -14.62mA   -11.11mA
-681.8mV  -6.063mA   -7.112mA   -8.68mA
-590.9mV  -3.583mA   -2.962mA   -5.341mA
-318.2mV  -161.1uA   -115.5uA   -270.1uA
3V        0A         0A         0A
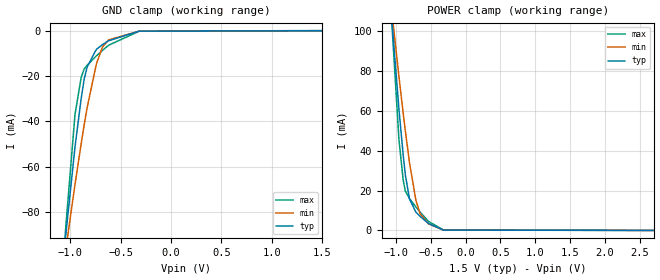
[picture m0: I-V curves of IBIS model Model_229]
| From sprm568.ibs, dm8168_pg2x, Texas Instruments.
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| Model based on original model for BSHTLTCSCDVGPBFZ
|   Sub model REC_NOTERM_PD_ON_1P5_10PER_1P5
[model]   Model_229
|[Description]  [1.5V-INPUT-NOTERM-X, IND, 10%]
|   ODT off (ODT[1:0] = "00") CMOS mode,Industrial temperature range
|   (-40C to 125C, 25C nominal),10% power supply tolerance
|[Input Load]   NOTERM
|[Output Drive]
|Voltage   1.5V
|Mode   INPUT
Model_type   Input
Polarity   Non-Inverting
Vinl =  0.65
Vinh =  1
C_comp   1.5249p   1.4275p   1.6205p
[Model Spec]
Vinl   0.65   0.65   0.65
Vinh   1   1   1
D_overshoot_high 1.95 1.95 1.95
D_overshoot_low -0.3 -0.3 -0.3
D_overshoot_time 1E-9 1E-9 1E-9
S_overshoot_high 1.65 1.65 1.65
S_overshoot_low 0 0 0
[Temperature Range]   25   125   -40
[Voltage Range]   1.5   1.35   1.65
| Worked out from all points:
|   GND clamp passes 1 mA (typ) near -0.46 V on its own axis
|   POWER clamp passes 1 mA (typ) near -0.41 V on its own axis
[POWER_clamp]
-1.5V     321.7mA    260.6mA    415.9mA
-1.076V   114.2mA    115.8mA    116.9mA
-1.045V   100.2mA    105.9mA    97.3mA
-954.5mV  60.65mA    77.06mA    45.48mA
-893.9mV  37.93mA    58.81mA    25.25mA
-863.6mV  27.97mA    50mA       19.84mA
-803mV    15.79mA    33.93mA    15.95mA
-712.1mV  9.21mA     15.25mA    11.82mA
-651.5mV  7.088mA    8.376mA    9.242mA
-530.3mV  3.495mA    3.276mA    4.548mA
-318.2mV  199uA      243.2uA    268.6uA
3V        0A         0A         0A
[GND_clamp]
-1.5V     -310.1mA   -250.5mA   -402.5mA
-1.076V   -103.6mA   -106.2mA   -105.3mA
-1.045V   -89.8mA    -96.33mA   -86.01mA
-954.5mV  -51.25mA   -67.87mA   -36.93mA
-893.9mV  -30.13mA   -50.1mA    -20.64mA
-863.6mV  -21.29mA   -41.58mA   -16.81mA
-833.3mV  -15.86mA   -33.77mA   -15.12mA
-742.4mV  -8.118mA   -14.61mA   -11.02mA
-681.8mV  -6.018mA   -7.097mA   -8.576mA
-621.2mV  -4.321mA   -3.935mA   -6.305mA
-318.2mV  -69.58uA   -68.38uA   -105.2uA
1.5V      113.8uA    57.47uA    197.5uA
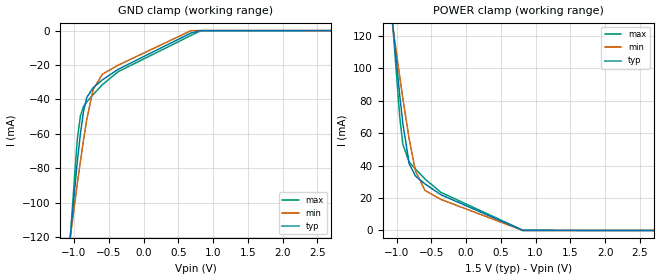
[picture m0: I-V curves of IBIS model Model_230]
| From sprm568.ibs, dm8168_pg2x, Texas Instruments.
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| Model based on original model for BSHTLTCSCDVGPBFZ
|   Sub model REC_FULLTERM_TH_1P5_8MA_10PER_1P5
[model]   Model_230
|[Description]  [1.5V-INPUT-FULLTERM:8MA-X, IND, 10%]
|   FULLTERM, 1.00 * RExt = 1.000 * Iout (I[2:0] = "011"), 8mA
|   nominal with Rext = 50R,Industrial temperature range (-40C to
|   125C, 25C nominal),10% power supply tolerance
|[Input Load]   FULLTERM:8MA
|[Output Drive]
|Voltage   1.5V
|Mode   INPUT
Model_type   Input
Polarity   Non-Inverting
Vinl =  0.65
Vinh =  1
C_comp   1.5249p   1.4275p   1.6205p
[Model Spec]
Vinl   0.65   0.65   0.65
Vinh   1   1   1
D_overshoot_high 1.95 1.95 1.95
D_overshoot_low -0.3 -0.3 -0.3
D_overshoot_time 1E-9 1E-9 1E-9
S_overshoot_high 1.65 1.65 1.65
S_overshoot_low 0 0 0
[Temperature Range]   25   125   -40
[Voltage Range]   1.5   1.35   1.65
[POWER_clamp]
-1.5V     342.2mA    273.6mA    438.8mA
-1.136V   164.9mA    152.2mA    181.3mA
-1.091V   143.6mA    137.6mA    150.9mA
-1.045V   122.8mA    123.1mA    121.5mA
-954.5mV  83.54mA    94.91mA    70.12mA
-909.1mV  65.97mA    81.37mA    53.08mA
-818.2mV  41.13mA    56.34mA    42.27mA
-727.3mV  33.59mA    36.65mA    37.91mA
-590.9mV  28.72mA    24.74mA    31.78mA
-363.6mV  22.07mA    19.19mA    23.54mA
818.2mV   0A         0A         133.1uA
3V        0A         0A         0A
[GND_clamp]
-1.5V     -334.4mA   -267.3mA   -428.7mA
-1.091V   -135.7mA   -131.6mA   -141.1mA
-954.5mV  -76.6mA    -89.32mA   -63.53mA
-909.1mV  -59.99mA   -76.04mA   -49.64mA
-863.6mV  -46.91mA   -63.47mA   -44.11mA
-818.2mV  -38.97mA   -51.95mA   -41.49mA
-727.3mV  -33.23mA   -34.43mA   -37.27mA
-590.9mV  -28.58mA   -25.27mA   -31.37mA
-363.6mV  -22.46mA   -20.08mA   -23.83mA
681.8mV   -1.417mA   -44.8uA    -2.847mA
818.2mV   0A         0A         -137.5uA
3V        0A         0A         0A
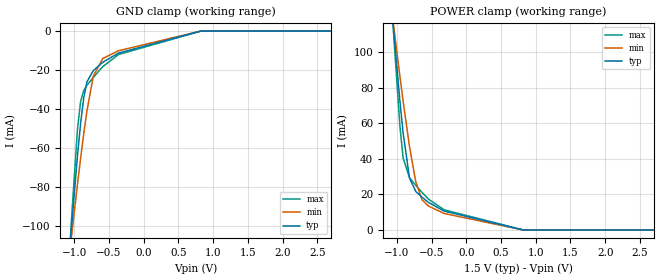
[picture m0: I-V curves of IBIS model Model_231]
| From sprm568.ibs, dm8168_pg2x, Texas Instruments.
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| Model based on original model for BSHTLTCSCDVGPBFZ
|   Sub model REC_HALFTERM_TH_1P5_8MA_10PER_1P5
[model]   Model_231
|[Description]  [1.5V-INPUT-HALFTERM:8MA-X, IND, 10%]
|   Half Thevenin termination (Rth = 100R whith RExt = 50R)
|   (ODT[1:0] = "11") VRef mode, 1.00 * RExt = 1.000 * Iout (I[2:0]
|   = "011"), 8mA nominal with Rext = 50R,Industrial temperature
|   range (-40C to 125C, 25C nominal),10% power supply tolerance
|[Input Load]   HALFTERM:8MA
|[Output Drive]
|Voltage   1.5V
|Mode   INPUT
Model_type   Input
Polarity   Non-Inverting
Vinl =  0.65
Vinh =  1
C_comp   1.5249p   1.4275p   1.6205p
[Model Spec]
Vinl   0.65   0.65   0.65
Vinh   1   1   1
D_overshoot_high 1.95 1.95 1.95
D_overshoot_low -0.3 -0.3 -0.3
D_overshoot_time 1E-9 1E-9 1E-9
S_overshoot_high 1.65 1.65 1.65
S_overshoot_low 0 0 0
[Temperature Range]   25   125   -40
[Voltage Range]   1.5   1.35   1.65
[POWER_clamp]
-1.5V     331.9mA    267.1mA    427.3mA
-1.091V   132.4mA    129.2mA    138.8mA
-1.045V   111.5mA    114.5mA    109.4mA
-954.5mV  72.06mA    85.98mA    57.73mA
-909.1mV  54.41mA    72.29mA    40.44mA
-818.2mV  29.3mA     46.97mA    29.39mA
-727.3mV  21.64mA    27.01mA    25.1mA
-636.4mV  18.37mA    16.92mA    21.1mA
-545.5mV  15.51mA    13.47mA    17.37mA
-318.2mV  10.6mA     9.261mA    11.31mA
818.2mV   0A         0A         67.01uA
3V        0A         0A         0A
[GND_clamp]
-1.5V     -322.2mA   -258.9mA   -415.5mA
-1.091V   -123.1mA   -121.3mA   -128mA
-1.045V   -102.4mA   -106.8mA   -99.08mA
-954.5mV  -63.89mA   -78.58mA   -50.19mA
-909.1mV  -47.24mA   -65.18mA   -36.05mA
-863.6mV  -34.07mA   -52.51mA   -30.42mA
-818.2mV  -26.02mA   -40.89mA   -27.84mA
-727.3mV  -20.32mA   -23.21mA   -23.79mA
-590.9mV  -16.03mA   -14.08mA   -18.26mA
-363.6mV  -11.29mA   -10.1mA    -12.03mA
818.2mV   0A         0A         -68.43uA
3V        0A         0A         0A
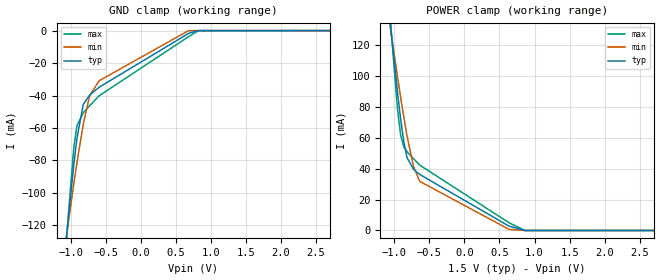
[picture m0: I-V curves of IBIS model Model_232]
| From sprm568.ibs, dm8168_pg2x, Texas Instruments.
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| Model based on original model for BSHTLTCSCDVGPBFZ
|   Sub model REC_FULLTERM_TH_1P5_10MA_10PER_1P5
[model]   Model_232
|[Description]  [1.5V-INPUT-FULLTERM:10MA-X, IND, 10%]
|   FULLTERM, 0.80 * RExt = 1.250 * Iout (I[2:0] = "101"), 10mA
|   nominal with Rext = 50R,Industrial temperature range (-40C to
|   125C, 25C nominal),10% power supply tolerance
|[Input Load]   FULLTERM:10MA
|[Output Drive]
|Voltage   1.5V
|Mode   INPUT
Model_type   Input
Polarity   Non-Inverting
Vinl =  0.65
Vinh =  1
C_comp   1.5249p   1.4275p   1.6205p
[Model Spec]
Vinl   0.65   0.65   0.65
Vinh   1   1   1
D_overshoot_high 1.95 1.95 1.95
D_overshoot_low -0.3 -0.3 -0.3
D_overshoot_time 1E-9 1E-9 1E-9
S_overshoot_high 1.65 1.65 1.65
S_overshoot_low 0 0 0
[Temperature Range]   25   125   -40
[Voltage Range]   1.5   1.35   1.65
[POWER_clamp]
-1.5V     347.3mA    276.8mA    446.5mA
-1.227V   213.8mA    186mA      252mA
-1.045V   128.5mA    127.4mA    129.6mA
-954.5mV  89.28mA    99.38mA    78.38mA
-909.1mV  71.76mA    85.92mA    61.51mA
-863.6mV  57.1mA     73.07mA    53.95mA
-818.2mV  47.04mA    61.03mA    50.85mA
-727.3mV  39.57mA    41.47mA    46.44mA
-636.4mV  36.19mA    31.7mA     42.23mA
636.4mV   2.788mA    710.8uA    4.982mA
863.6mV   0A         0A         0A
3V        0A         0A         0A
[GND_clamp]
-1.5V     -340.4mA   -271.5mA   -437.4mA
-1.136V   -163.1mA   -151.3mA   -180mA
-1.091V   -142mA     -136.8mA   -149.9mA
-1.045V   -121.4mA   -122.4mA   -121mA
-954.5mV  -82.95mA   -94.69mA   -72.43mA
-909.1mV  -66.37mA   -81.48mA   -58.7mA
-818.2mV  -45.44mA   -57.48mA   -50.59mA
-727.3mV  -39.68mA   -40.05mA   -46.26mA
-590.9mV  -34.85mA   -30.86mA   -40.11mA
681.8mV   -1.77mA    -56.15uA   -3.793mA
818.2mV   0A         0A         -183.5uA
3V        0A         0A         0A
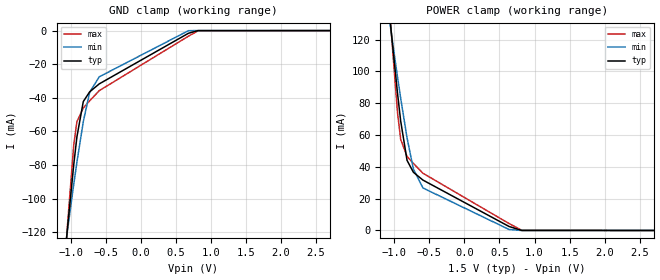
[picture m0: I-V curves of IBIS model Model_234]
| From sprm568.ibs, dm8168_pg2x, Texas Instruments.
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| Model based on original model for BSHTLTCSCDVGPBFZ
|   Sub model REC_FULLTERM_TH_1P5_9MA_10PER_1P5
[model]   Model_234
|[Description]  [1.5V-INPUT-FULLTERM:9MA-X, IND, 10%]
|   FULLTERM, 0.88 * RExt = 1.125 * Iout (I[2:0] = "100"), 9mA
|   nominal with Rext = 50R,Industrial temperature range (-40C to
|   125C, 25C nominal),10% power supply tolerance
|[Input Load]   FULLTERM:9MA
|[Output Drive]
|Voltage   1.5V
|Mode   INPUT
Model_type   Input
Polarity   Non-Inverting
Vinl =  0.65
Vinh =  1
C_comp   1.5249p   1.4275p   1.6205p
[Model Spec]
Vinl   0.65   0.65   0.65
Vinh   1   1   1
D_overshoot_high 1.95 1.95 1.95
D_overshoot_low -0.3 -0.3 -0.3
D_overshoot_time 1E-9 1E-9 1E-9
S_overshoot_high 1.65 1.65 1.65
S_overshoot_low 0 0 0
[Temperature Range]   25   125   -40
[Voltage Range]   1.5   1.35   1.65
[POWER_clamp]
-1.5V     344.8mA    274.9mA    442.6mA
-1.136V   167.7mA    153.9mA    185.3mA
-1.091V   146.5mA    139.3mA    154.9mA
-1.045V   125.6mA    124.8mA    125.6mA
-954.5mV  86.41mA    96.7mA     74.25mA
-909.1mV  68.86mA    83.19mA    57.29mA
-818.2mV  44.09mA    58.21mA    46.56mA
-727.3mV  36.58mA    38.58mA    42.17mA
-590.9mV  31.67mA    26.72mA    35.98mA
636.4mV   2.51mA     625.8uA    4.361mA
818.2mV   0A         0A         155.1uA
3V        0A         0A         0A
[GND_clamp]
-1.5V     -337.4mA   -269mA     -433.1mA
-1.136V   -160mA     -148.2mA   -175.6mA
-1.091V   -138.9mA   -133.7mA   -145.5mA
-1.045V   -118.2mA   -119.3mA   -116.6mA
-954.5mV  -79.77mA   -91.47mA   -67.98mA
-909.1mV  -63.18mA   -78.22mA   -54.17mA
-818.2mV  -42.21mA   -54.16mA   -46.04mA
-727.3mV  -36.45mA   -36.68mA   -41.77mA
-590.9mV  -31.71mA   -27.5mA    -35.74mA
681.8mV   -1.594mA   -49.34uA   -3.32mA
818.2mV   0A         0A         -160.5uA
3V        0A         0A         0A
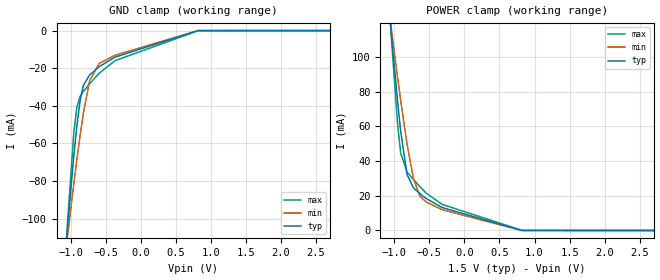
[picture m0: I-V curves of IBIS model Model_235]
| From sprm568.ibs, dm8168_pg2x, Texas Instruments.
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| Model based on original model for BSHTLTCSCDVGPBFZ
|   Sub model REC_HALFTERM_TH_1P5_10MA_10PER_1P5
[model]   Model_235
|[Description]  [1.5V-INPUT-HALFTERM:10MA-X, IND, 10%]
|   Half Thevenin termination (Rth = 100R whith RExt = 50R)
|   (ODT[1:0] = "11") VRef mode, 0.80 * RExt = 1.250 * Iout (I[2:0]
|   = "101"), 10mA nominal with Rext = 50R,Industrial temperature
|   range (-40C to 125C, 25C nominal),10% power supply tolerance
|[Input Load]   HALFTERM:10MA
|[Output Drive]
|Voltage   1.5V
|Mode   INPUT
Model_type   Input
Polarity   Non-Inverting
Vinl =  0.65
Vinh =  1
C_comp   1.5249p   1.4275p   1.6205p
[Model Spec]
Vinl   0.65   0.65   0.65
Vinh   1   1   1
D_overshoot_high 1.95 1.95 1.95
D_overshoot_low -0.3 -0.3 -0.3
D_overshoot_time 1E-9 1E-9 1E-9
S_overshoot_high 1.65 1.65 1.65
S_overshoot_low 0 0 0
[Temperature Range]   25   125   -40
[Voltage Range]   1.5   1.35   1.65
[POWER_clamp]
-1.5V     334.5mA    269mA      431.1mA
-1.091V   135.2mA    131.7mA    142.8mA
-1.045V   114.3mA    117.1mA    113.4mA
-954.5mV  74.93mA    88.66mA    61.86mA
-909.1mV  57.3mA     75.01mA    44.65mA
-818.2mV  32.26mA    49.78mA    33.68mA
-727.3mV  24.63mA    29.9mA     29.37mA
-636.4mV  21.34mA    19.87mA    25.33mA
-545.5mV  18.43mA    16.43mA    21.53mA
-318.2mV  13.23mA    11.98mA    15.05mA
818.2mV   0A         0A         89.06uA
3V        0A         0A         0A
[GND_clamp]
-1.5V     -325.2mA   -261.4mA   -419.9mA
-1.091V   -126.2mA   -124.4mA   -132.3mA
-1.045V   -105.6mA   -109.9mA   -103.5mA
-954.5mV  -67.07mA   -81.8mA    -54.64mA
-909.1mV  -50.43mA   -68.44mA   -40.58mA
-863.6mV  -37.28mA   -55.8mA    -34.98mA
-818.2mV  -29.26mA   -44.21mA   -32.39mA
-727.3mV  -23.55mA   -26.58mA   -28.29mA
-590.9mV  -19.16mA   -17.44mA   -22.63mA
-363.6mV  -14.09mA   -13.1mA    -15.97mA
818.2mV   0A         0A         -91.46uA
3V        0A         0A         0A
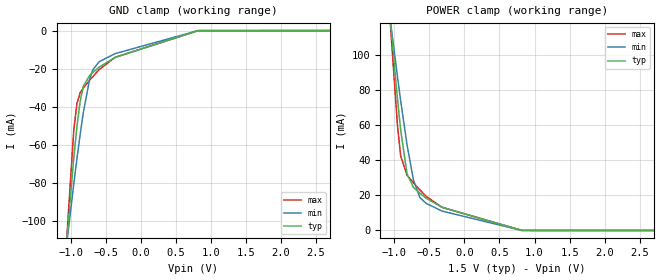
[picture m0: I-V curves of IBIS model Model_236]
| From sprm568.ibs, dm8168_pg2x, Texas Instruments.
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| Model based on original model for BSHTLTCSCDVGPBFZ
|   Sub model REC_FULLTERM_TH_1P5_5MA_10PER_1P5
[model]   Model_236
|[Description]  [1.5V-INPUT-FULLTERM:5MA-X, IND, 10%]
|   FULLTERM, 1.60 * RExt = 0.625 * Iout (I[2:0] = "000"), 5mA
|   nominal with Rext = 50R,Industrial temperature range (-40C to
|   125C, 25C nominal),10% power supply tolerance
|[Input Load]   FULLTERM:5MA
|[Output Drive]
|Voltage   1.5V
|Mode   INPUT
Model_type   Input
Polarity   Non-Inverting
Vinl =  0.65
Vinh =  1
C_comp   1.5249p   1.4275p   1.6205p
[Model Spec]
Vinl   0.65   0.65   0.65
Vinh   1   1   1
D_overshoot_high 1.95 1.95 1.95
D_overshoot_low -0.3 -0.3 -0.3
D_overshoot_time 1E-9 1E-9 1E-9
S_overshoot_high 1.65 1.65 1.65
S_overshoot_low 0 0 0
[Temperature Range]   25   125   -40
[Voltage Range]   1.5   1.35   1.65
[POWER_clamp]
-1.5V     334.5mA    268.4mA    429.2mA
-1.091V   135.2mA    130.9mA    140.8mA
-1.045V   114.3mA    116.2mA    111.4mA
-954.5mV  74.93mA    87.76mA    59.79mA
-909.1mV  57.3mA     74.1mA     42.54mA
-818.2mV  32.26mA    48.84mA    31.54mA
-727.3mV  24.63mA    28.94mA    27.24mA
-636.4mV  21.34mA    18.89mA    23.22mA
-545.5mV  18.43mA    15.45mA    19.45mA
-318.2mV  13.23mA    11.07mA    13.18mA
818.2mV   0A         0A         78.03uA
3V        0A         0A         0A
[GND_clamp]
-1.5V     -325.2mA   -260.6mA   -417.7mA
-1.091V   -126.2mA   -123.4mA   -130.2mA
-954.5mV  -67.07mA   -80.73mA   -52.41mA
-909.1mV  -50.43mA   -67.36mA   -38.32mA
-863.6mV  -37.28mA   -54.7mA    -32.7mA
-818.2mV  -29.26mA   -43.1mA    -30.12mA
-727.3mV  -23.55mA   -25.45mA   -26.04mA
-681.8mV  -21.98mA   -20.58mA   -24.1mA
-590.9mV  -19.16mA   -16.32mA   -20.45mA
-363.6mV  -14.09mA   -12.1mA    -14mA
818.2mV   0A         0A         -79.95uA
3V        0A         0A         0A
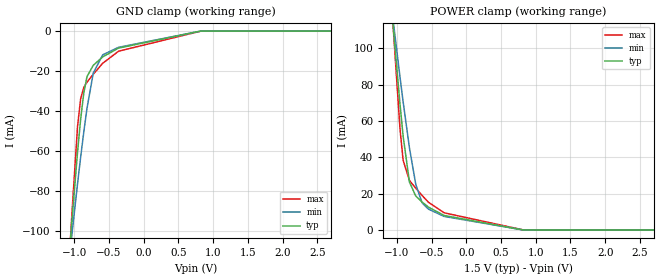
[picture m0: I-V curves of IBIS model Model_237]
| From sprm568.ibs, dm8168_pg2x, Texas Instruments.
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| Model based on original model for BSHTLTCSCDVGPBFZ
|   Sub model REC_HALFTERM_TH_1P5_6MA_10PER_1P5
[model]   Model_237
|[Description]  [1.5V-INPUT-HALFTERM:6MA-X, IND, 10%]
|   Half Thevenin termination (Rth = 100R whith RExt = 50R)
|   (ODT[1:0] = "11") VRef mode, 1.33 * RExt = 0.750 * Iout (I[2:0]
|   = "001"), 6mA nominal with Rext = 50R,Industrial temperature
|   range (-40C to 125C, 25C nominal),10% power supply tolerance
|[Input Load]   HALFTERM:6MA
|[Output Drive]
|Voltage   1.5V
|Mode   INPUT
Model_type   Input
Polarity   Non-Inverting
Vinl =  0.65
Vinh =  1
C_comp   1.5249p   1.4275p   1.6205p
[Model Spec]
Vinl   0.65   0.65   0.65
Vinh   1   1   1
D_overshoot_high 1.95 1.95 1.95
D_overshoot_low -0.3 -0.3 -0.3
D_overshoot_time 1E-9 1E-9 1E-9
S_overshoot_high 1.65 1.65 1.65
S_overshoot_low 0 0 0
[Temperature Range]   25   125   -40
[Voltage Range]   1.5   1.35   1.65
[POWER_clamp]
-1.5V     329.4mA    265.8mA    425.4mA
-1.091V   129.6mA    127.5mA    136.7mA
-1.045V   108.7mA    112.8mA    107.3mA
-954.5mV  69.19mA    84.19mA    55.66mA
-909.1mV  51.52mA    70.47mA    38.33mA
-818.2mV  26.34mA    45.1mA     27.25mA
-727.3mV  18.65mA    25.09mA    22.97mA
-636.4mV  15.4mA     14.95mA    18.99mA
-545.5mV  12.58mA    11.49mA    15.28mA
-318.2mV  7.975mA    7.448mA    9.434mA
818.2mV   0A         0A         55.98uA
3V        0A         0A         0A
[GND_clamp]
-1.5V     -319.2mA   -257.2mA   -413.4mA
-1.091V   -119.9mA   -119.3mA   -125.8mA
-1.045V   -99.24mA   -104.7mA   -96.89mA
-954.5mV  -60.72mA   -76.43mA   -47.96mA
-909.1mV  -44.05mA   -63.01mA   -33.79mA
-863.6mV  -30.86mA   -50.31mA   -28.14mA
-818.2mV  -22.79mA   -38.68mA   -25.56mA
-727.3mV  -17.09mA   -20.97mA   -21.54mA
-590.9mV  -12.89mA   -11.85mA   -16.07mA
-363.6mV  -8.499mA   -8.107mA   -10.06mA
818.2mV   0A         0A         -56.9uA
3V        0A         0A         0A
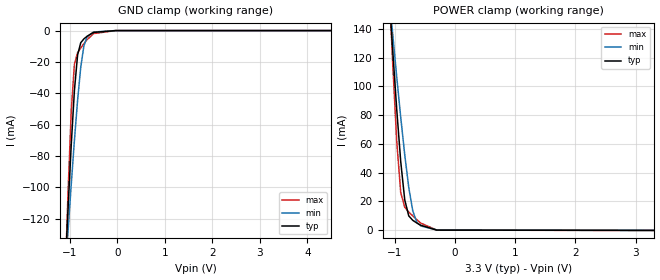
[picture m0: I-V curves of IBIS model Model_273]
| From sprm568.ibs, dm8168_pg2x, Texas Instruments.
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| Model based on original model for BC3340CGHYPBFBP18
|   Sub model WK_PU_ON_3P3
[model]   Model_273
|[Description]  [3.3V-INPUT-PU-X]
|   Weak internal pull-up, ,
|[Input Load]   PU
|[Output Drive]
|Voltage   3.3V
|Mode   INPUT
Model_type   Input
Polarity   Non-Inverting
Vinl =  0.8
Vinh =  2
C_comp   2.89503p   2.83043p   2.94619p
[Model Spec]
Vinl   0.8   0.8   0.8
Vinh   2   2   2
[Temperature Range]   25   125   -40
[Voltage Range]   3.3   2.97   3.63
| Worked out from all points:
|   GND clamp passes 1 mA (typ) near -0.48 V on its own axis
|   POWER clamp passes 1 mA (typ) near -0.44 V on its own axis
[POWER_clamp]
-3.3V     1.74A      1.237A     2.448A
-1.1V     168.3mA    166.6mA    176.4mA
-1.033V   125.1mA    136.3mA    115.9mA
-966.7mV  84.21mA    106.8mA    62.15mA
-900mV    47.72mA    78.6mA     26.19mA
-833.3mV  21.08mA    52.39mA    15.99mA
-766.7mV  9.964mA    29.73mA    12.73mA
-700mV    6.863mA    13.44mA    9.966mA
-633.3mV  5.022mA    5.645mA    7.346mA
-566.7mV  3.41mA     2.975mA    4.918mA
-300mV    68.36uA    111uA      71.06uA
3.3V      -116.2uA   -115.2uA   -190uA
[GND_clamp]
-3.3V     -1.738A    -1.232A    -2.455A
-1.1V     -156.3mA   -158mA     -162.3mA
-1.033V   -113.1mA   -127.6mA   -102.6mA
-966.7mV  -72.84mA   -98.14mA   -51.34mA
-900mV    -38.17mA   -70.09mA   -21.4mA
-833.3mV  -15.54mA   -44.49mA   -14.14mA
-766.7mV  -7.729mA   -23.3mA    -11.05mA
-700mV    -5.282mA   -9.631mA   -8.324mA
-633.3mV  -3.625mA   -3.944mA   -5.831mA
-500mV    -1.177mA   -903.5uA   -1.931mA
-33.33mV  0A         0A         0A
6.6V      0A         0A         0A
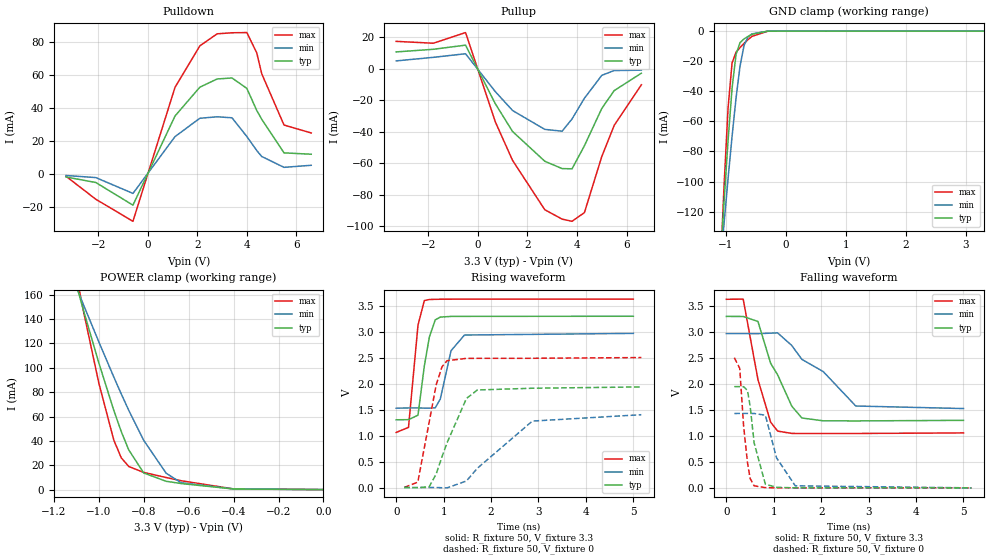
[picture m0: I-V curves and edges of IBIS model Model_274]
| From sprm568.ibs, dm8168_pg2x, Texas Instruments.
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| Model based on original model for BC3340CGHYPBFBP18
|   Sub model DRIVER_MODE_3P3
[model]   Model_274
|[Description]  [3.3V-I/O-PI-X]
|   Weak pull up/down disabled, ,
|[Input Load]   PI
|[Output Drive]
|Voltage   3.3V
|Mode   I/O
Model_type   I/O
Polarity   Non-Inverting
Enable   Active-Low
Vinl =  0.8
Vinh =  2
Cref =  15.0000pF
Rref =  100.0000M
Vref =  0V
Vmeas =  1.65
C_comp   2.89503p   2.83043p   2.94619p
[Model Spec]
Vinl   0.8   0.8   0.8
Vinh   2   2   2
[Temperature Range]   25   125   -40
[Voltage Range]   3.3   2.97   3.63
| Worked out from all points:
|   slope of the pulldown table from 0 to 0.495 V, typ, clamps not added: 28.2 ohm
|   slope of the pullup table from 0 to 0.495 V, typ, clamps not added: 30.7 ohm
|   GND clamp passes 1 mA (typ) near -0.49 V on its own axis
|   POWER clamp passes 1 mA (typ) near -0.44 V on its own axis
|   rising waveform, R_fixture 50, V_fixture 3.3: 20-80 % time 181ps typ, 224ps min, 149ps max; typ from 1.3 V to 3.3 V
|   rising waveform, R_fixture 50, V_fixture 0: 20-80 % time 511ps typ, 976ps min, 298ps max; typ from 0 V to 1.94 V
|   falling waveform, R_fixture 50, V_fixture 3.3: 20-80 % time 547ps typ, 974ps min, 367ps max; typ from 3.3 V to 1.3 V
|   falling waveform, R_fixture 50, V_fixture 0: 20-80 % time 189ps typ, 283ps min, 135ps max; typ from 1.95 V to 0 V
[POWER_clamp]
-3.3V     1.74A      1.237A     2.448A
-1.1V     168.3mA    166.5mA    176.4mA
-1.067V   146.5mA    151.3mA    145.6mA
-1V       104.2mA    121.4mA    87.66mA
-933.3mV  65.14mA    92.5mA     40.77mA
-900mV    47.68mA    78.57mA    26.13mA
-866.7mV  32.63mA    65.15mA    18.99mA
-800mV    13.66mA    40.44mA    14.14mA
-700mV    6.816mA    13.41mA    9.899mA
-633.3mV  4.976mA    5.618mA    7.282mA
-400mV    494.4uA    576.8uA    579.8uA
0V        107.9nA    188.2nA    173.9nA
[Pulldown]
-3.3V     -1.9mA     -1mA       -1.5mA
-2.1V     -5.25mA    -2.26mA    -15.4mA
-600mV    -18.98mA   -11.87mA   -28.78mA
1.1V      35.11mA    22.6mA     52.52mA
2.1V      52.56mA    33.71mA    77.62mA
2.8V      57.55mA    34.61mA    84.94mA
3.4V      58.16mA    34.01mA    85.57mA
4V        51.83mA    22.63mA    85.7mA
4.4V      38.43mA    14.15mA    73.38mA
4.6V      33.13mA    10.53mA    60.74mA
5.5V      12.73mA    3.94mA     29.61mA
6.6V      11.9mA     5.2mA      24.8mA
[Pullup]
-3.3V     10.6mA     4.9mA      17.3mA
-1.8V     12.27mA    7.15mA     16.12mA
-500mV    14.9mA     9.441mA    22.89mA
700mV     -22.26mA   -14.57mA   -33.75mA
1.4V      -39.98mA   -26.64mA   -58.35mA
2.7V      -58.84mA   -38.6mA    -89.64mA
3.4V      -63.52mA   -39.76mA   -95.61mA
3.8V      -63.65mA   -31.99mA   -96.99mA
4.3V      -49.02mA   -18.84mA   -91.47mA
5V        -25.36mA   -4.29mA    -55.93mA
5.5V      -14.01mA   -1.23mA    -36.11mA
6.6V      -2.9mA     -1mA       -10.3mA
[GND_clamp]
-3.3V     -1.738A    -1.232A    -2.455A
-1.1V     -156.2mA   -158mA     -162.2mA
-1.033V   -113.1mA   -127.6mA   -102.5mA
-966.7mV  -72.77mA   -98.11mA   -51.22mA
-900mV    -38.1mA    -70.06mA   -21.27mA
-833.3mV  -15.46mA   -44.45mA   -14.01mA
-766.7mV  -7.654mA   -23.26mA   -10.92mA
-700mV    -5.203mA   -9.589mA   -8.187mA
-633.3mV  -3.542mA   -3.899mA   -5.686mA
-566.7mV  -2.157mA   -1.848mA   -3.497mA
-300mV    -27.28uA   -33.59uA   -33.93uA
3.3V      107.9nA    175uA      154.3nA
[Ramp]
dV/dt_f   1.21842/0.55313357n   0.87756/0.9823359n   1.56414/0.37083079n
dV/dt_r  1.1687298/0.51286972n 0.84626274/0.9792321n  1.5100116/0.2992178n
R_load = 50
[Rising Waveform]
R_fixture = 50
V_fixture = 3.3
V_fixture_min = 2.97
V_fixture_max = 3.63
0s        1.305V     1.529V     1.061V
258.9ps   1.307V     1.533V     1.158V
459.5ps   1.394V     1.533V     3.13V
592.9ps   2.342V     1.53V      3.602V
700ps     2.903V     1.529V     3.623V
823.2ps   3.23V      1.536V     3.626V
929.6ps   3.284V     1.704V     3.628V
1.156ns   3.297V     2.636V     3.629V
1.439ns   3.298V     2.938V     3.63V
5ns       3.3V       2.97V      3.63V
[Rising Waveform]
R_fixture = 50
V_fixture = 0
V_fixture_min = 0
V_fixture_max = 0
168.9ps   0V         0V         0V
455.6ps   -3.625mV   0V         104.1mV
695.2ps   14.2mV     0V         1.262V
841.5ps   257.5mV    0V         1.973V
965.5ps   592.9mV    -4.853mV   2.326V
1.073ns   863.4mV    -6.868mV   2.444V
1.48ns    1.715V     124.9mV    2.488V
1.711ns   1.879V     370.6mV    2.489V
2.87ns    1.913V     1.28V      2.49V
5.169ns   1.938V     1.403V     2.504V
[Falling Waveform]
R_fixture = 50
V_fixture = 3.3
V_fixture_min = 2.97
V_fixture_max = 3.63
0s        3.301V     2.97V      3.631V
355.7ps   3.3V       2.97V      3.634V
666.8ps   3.204V     2.969V     2.084V
934.1ps   2.399V     2.979V     1.265V
1.081ns   2.177V     2.984V     1.093V
1.38ns    1.573V     2.741V     1.048V
1.594ns   1.345V     2.473V     1.047V
2.044ns   1.291V     2.238V     1.047V
2.729ns   1.289V     1.576V     1.047V
5ns       1.3V       1.527V     1.058V
[Falling Waveform]
R_fixture = 50
V_fixture = 0
V_fixture_min = 0
V_fixture_max = 0
168.9ps   1.949V     1.432V     2.506V
282.9ps   1.949V     1.433V     2.299V
365ps     1.948V     1.434V     1.182V
446.1ps   1.873V     1.434V     486.6mV
500.8ps   1.58V      1.433V     182mV
586.6ps   863.9mV    1.432V     39.14mV
823.1ps   70.32mV    1.399V     4.65mV
1.058ns   10.72mV    578.5mV    0V
1.454ns   0V         39.22mV    0V
5.169ns   0V         0V         0V
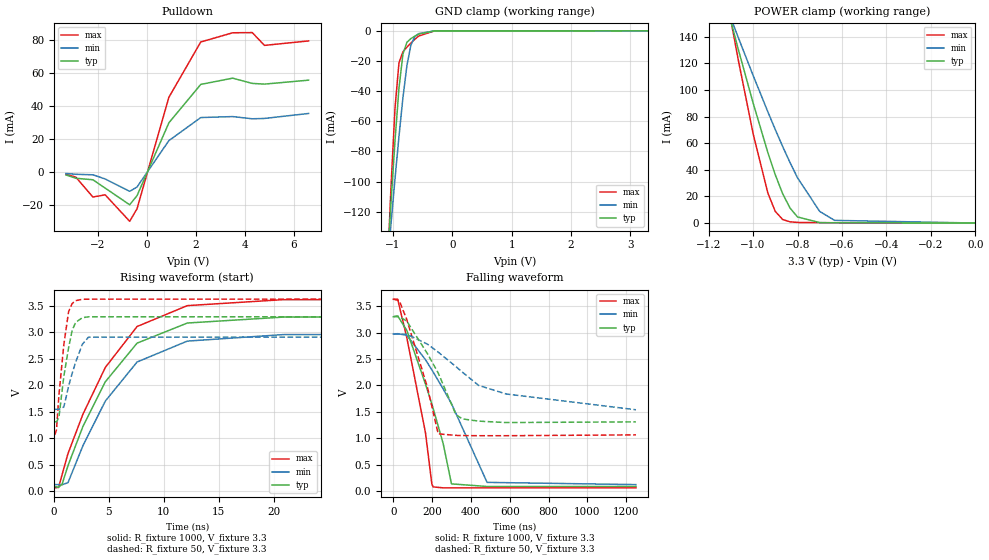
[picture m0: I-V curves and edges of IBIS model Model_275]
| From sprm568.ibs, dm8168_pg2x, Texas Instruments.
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| Model based on original model for BI2C33GFZP18
|   Sub model BI2C33GFZP18
[model]   Model_275
|[Description]  [3.3V-I/O_OPEN_DRAIN-X-X]
|   , ,
|[Input Load]
|[Output Drive]
|Voltage   3.3V
|Mode   I/O_OPEN_DRAIN
Model_type   I/O_open_drain
Polarity   Non-Inverting
Enable   Active-Low
Vinl =  0.99
Vinh =  2.31
Cref =  15.0000pF
Rref =  100.0000M
Vref =  0V
Vmeas =  1.65
C_comp   4.1718p   4.01719p   4.29849p
[Model Spec]
Vinl   0.99   0.891   1.089
Vinh   2.31   2.079   2.541
[Temperature Range]   25   125   -40
[Voltage Range]   3.3   2.97   3.63
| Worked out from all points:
|   slope of the pulldown table from 0 to 0.495 V, typ, clamps not added: 28.3 ohm
|   GND clamp passes 1 mA (typ) near -0.49 V on its own axis
|   POWER clamp passes 1 mA (typ) near -0.74 V on its own axis
|   rising waveform, R_fixture 1000, V_fixture 3.3: 20-80 % time 5.1ns typ, 5.02ns min, 5.19ns max; typ from 0.086 V to 3.3 V
|   rising waveform, R_fixture 50, V_fixture 3.3: 20-80 % time 881ps typ, 1.23ns min, 729ps max; typ from 1.31 V to 3.3 V
|   falling waveform, R_fixture 1000, V_fixture 3.3: 20-80 % time 160ns typ, 243ns min, 111ns max; typ from 3.3 V to 0.086 V
|   falling waveform, R_fixture 50, V_fixture 3.3: 20-80 % time 171ns typ, 386ns min, 121ns max; typ from 3.3 V to 1.31 V
[POWER_clamp]
-3.3V     1.674A     1.189A     2.354A
-1.1V     152mA      154.2mA    152.8mA
-1.067V   131mA      139.7mA    123.2mA
-1V       90.44mA    111.1mA    67.43mA
-933.3mV  52.98mA    83.57mA    22.53mA
-900mV    36.31mA    70.29mA    8.77mA
-866.7mV  22.04mA    57.51mA    2.677mA
-833.3mV  11.2mA     45.34mA    897.8uA
-800mV    4.595mA    34.02mA    480.4uA
-700mV    322.1uA    8.706mA    296.4uA
-633.3mV  171.7uA    2.011mA    237.1uA
0V        51.52nA    88.05nA    93.05nA
[Pulldown]
-3.3V     -1.9mA     -1mA       -1.5mA
-2.9V     -3.9mA     -1.5mA     -3.2mA
-2.2V     -4.83mA    -1.81mA    -15.3mA
-1.7V     -9.89mA    -4.34mA    -13.95mA
-700mV    -19.99mA   -11.85mA   -30.02mA
-400mV    -14.47mA   -9.213mA   -22.43mA
900mV     29.74mA    18.93mA    45.23mA
2.2V      53.02mA    32.91mA    78.76mA
3.5V      56.81mA    33.51mA    84.33mA
4.3V      53.63mA    32.17mA    84.47mA
4.8V      53.2mA     32.37mA    76.69mA
6.6V      55.6mA     35.4mA     79.4mA
[GND_clamp]
-3.3V     -1.738A    -1.232A    -2.454A
-1.1V     -156.1mA   -157.9mA   -162.1mA
-1.033V   -113mA     -127.5mA   -102.4mA
-966.7mV  -72.71mA   -98.06mA   -51.14mA
-900mV    -38.04mA   -70.02mA   -21.19mA
-833.3mV  -15.41mA   -44.42mA   -13.94mA
-766.7mV  -7.608mA   -23.23mA   -10.85mA
-700mV    -5.164mA   -9.563mA   -8.132mA
-633.3mV  -3.508mA   -3.877mA   -5.639mA
-566.7mV  -2.129mA   -1.83mA    -3.459mA
-300mV    -20.76uA   -28.16uA   -24.87uA
3.3V      51.52nA    15.75uA    90.4nA
[Ramp]
dV/dt_f   1.20948/0.17213167u   0.86802/0.4011927u   1.55088/0.12122692u
dV/dt_r  30.58038m/0.30087078n  21.44808m/0.45974375n  38.37924m/0.23456562n
R_load = 50
[Rising Waveform]
R_fixture = 1000
V_fixture = 3.3
V_fixture_min = 2.97
V_fixture_max = 3.63
0s        85.73mV    121.7mV    60.02mV
432ps     72.31mV    122.7mV    67.49mV
748.4ps   127mV      119.2mV    305.6mV
1.286ns   479.3mV    157mV      707.3mV
2.652ns   1.224V     859.5mV    1.455V
4.686ns   2.067V     1.702V     2.338V
7.575ns   2.798V     2.441V     3.112V
12.14ns   3.178V     2.836V     3.507V
20.94ns   3.291V     2.96V      3.621V
1.25us    3.3V       2.97V      3.63V
[Rising Waveform]
R_fixture = 50
V_fixture = 3.3
V_fixture_min = 2.97
V_fixture_max = 3.63
92.53ps   1.31V      1.544V     1.063V
243.3ps   1.309V     1.545V     1.158V
463.2ps   1.391V     1.545V     1.818V
910.4ps   2.172V     1.59V      2.768V
1.34ns    2.708V     1.978V     3.393V
1.664ns   3.032V     2.223V     3.545V
1.978ns   3.189V     2.433V     3.601V
2.593ns   3.278V     2.775V     3.627V
3.149ns   3.296V     2.91V      3.629V
1.25us    3.3V       2.97V      3.63V
[Falling Waveform]
R_fixture = 1000
V_fixture = 3.3
V_fixture_min = 2.97
V_fixture_max = 3.63
0s        3.299V     2.97V      3.629V
22.31ns   3.315V     2.978V     3.632V
69.59ns   3.04V      2.947V     2.903V
166ns     2.022V     2.484V     1.095V
198.7ns   1.644V     2.292V     129.2mV
205.4ns   1.563V     2.252V     77.93mV
256.8ns   900mV      1.933V     60.51mV
299.7ns   135.4mV    1.653V     60.26mV
483ns     86.05mV    163.9mV    60.03mV
1.25us    86.33mV    121.7mV    60.47mV
[Falling Waveform]
R_fixture = 50
V_fixture = 3.3
V_fixture_min = 2.97
V_fixture_max = 3.63
92.53ps   3.3V       2.97V      3.631V
30.67ns   3.301V     2.97V      3.603V
69.58ns   3.214V     2.968V     3.243V
175.4ns   2.602V     2.781V     1.968V
231.3ns   2.234V     2.629V     1.082V
322.9ns   1.443V     2.354V     1.053V
355.9ns   1.365V     2.249V     1.05V
439.5ns   1.323V     1.999V     1.047V
581.1ns   1.296V     1.837V     1.047V
1.25us    1.309V     1.538V     1.063V
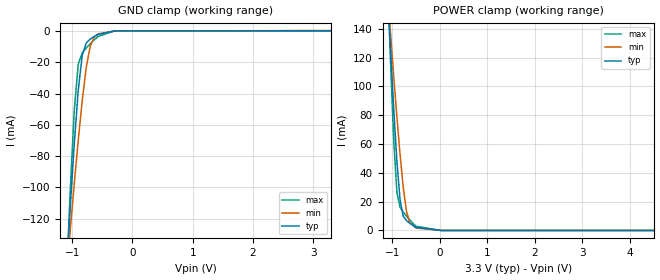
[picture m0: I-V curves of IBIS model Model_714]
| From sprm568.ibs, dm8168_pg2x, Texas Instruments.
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| Model based on original model for BC3340DGHYPBFBP18
|   Sub model WK_PD_ON_3P3
[model]   Model_714
|[Description]  [3.3V-INPUT-PD-X]
|   Weak internal pull-down, ,
|[Input Load]   PD
|[Output Drive]
|Voltage   3.3V
|Mode   INPUT
Model_type   Input
Polarity   Non-Inverting
Vinl =  0.8
Vinh =  2
C_comp   2.89345p   2.82907p   2.94437p
[Model Spec]
Vinl   0.8   0.8   0.8
Vinh   2   2   2
[Temperature Range]   25   125   -40
[Voltage Range]   3.3   2.97   3.63
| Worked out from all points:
|   GND clamp passes 1 mA (typ) near -0.49 V on its own axis
|   POWER clamp passes 1 mA (typ) near -0.44 V on its own axis
[POWER_clamp]
-3.3V     1.74A      1.237A     2.449A
-1.1V     168.3mA    166.6mA    176.5mA
-1.033V   125.1mA    136.3mA    115.9mA
-966.7mV  84.22mA    106.8mA    62.18mA
-900mV    47.74mA    78.59mA    26.24mA
-833.3mV  21.1mA     52.39mA    16.04mA
-766.7mV  9.984mA    29.73mA    12.79mA
-700mV    6.89mA     13.44mA    10.03mA
-633.3mV  5.055mA    5.651mA    7.423mA
-500mV    2.049mA    1.754mA    2.885mA
33.33mV   0A         0A         0A
6.6V      0A         0A         0A
[GND_clamp]
-3.3V     -1.738A    -1.232A    -2.455A
-1.1V     -156.2mA   -158mA     -162.3mA
-1.033V   -113.1mA   -127.6mA   -102.5mA
-966.7mV  -72.79mA   -98.11mA   -51.26mA
-900mV    -38.12mA   -70.07mA   -21.31mA
-833.3mV  -15.49mA   -44.46mA   -14.05mA
-766.7mV  -7.678mA   -23.27mA   -10.95mA
-700mV    -5.228mA   -9.602mA   -8.223mA
-633.3mV  -3.566mA   -3.912mA   -5.721mA
-566.7mV  -2.181mA   -1.861mA   -3.533mA
-300mV    -48.15uA   -44.72uA   -64.61uA
3.3V      93.53uA    219.4uA    161.8uA
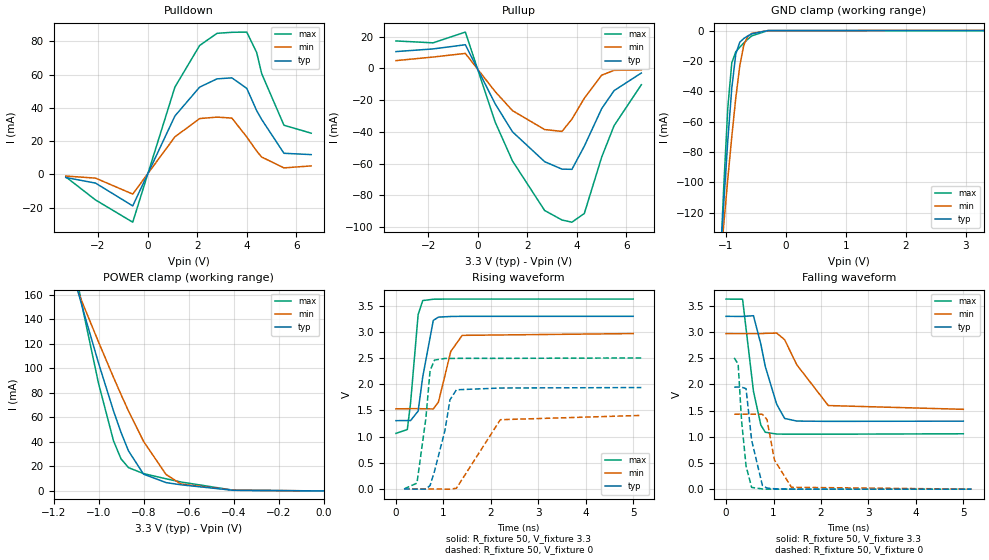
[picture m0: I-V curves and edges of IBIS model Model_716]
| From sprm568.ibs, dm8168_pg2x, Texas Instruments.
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| Model based on original model for BC3340DGHYPBFBP18
|   Sub model DRIVER_MODE_3P3
[model]   Model_716
|[Description]  [3.3V-I/O-PI-X]
|   Weak pull up/down disabled, ,
|[Input Load]   PI
|[Output Drive]
|Voltage   3.3V
|Mode   I/O
Model_type   I/O
Polarity   Non-Inverting
Enable   Active-Low
Vinl =  0.8
Vinh =  2
Cref =  15.0000pF
Rref =  100.0000M
Vref =  0V
Vmeas =  1.65
C_comp   2.89345p   2.82907p   2.94437p
[Model Spec]
Vinl   0.8   0.8   0.8
Vinh   2   2   2
[Temperature Range]   25   125   -40
[Voltage Range]   3.3   2.97   3.63
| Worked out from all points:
|   slope of the pulldown table from 0 to 0.495 V, typ, clamps not added: 28.2 ohm
|   slope of the pullup table from 0 to 0.495 V, typ, clamps not added: 30.7 ohm
|   GND clamp passes 1 mA (typ) near -0.49 V on its own axis
|   POWER clamp passes 1 mA (typ) near -0.44 V on its own axis
|   rising waveform, R_fixture 50, V_fixture 3.3: 20-80 % time 181ps typ, 243ps min, 143ps max; typ from 1.3 V to 3.3 V
|   rising waveform, R_fixture 50, V_fixture 0: 20-80 % time 280ps typ, 519ps min, 178ps max; typ from 0 V to 1.94 V
|   falling waveform, R_fixture 50, V_fixture 3.3: 20-80 % time 330ps typ, 615ps min, 220ps max; typ from 3.3 V to 1.3 V
|   falling waveform, R_fixture 50, V_fixture 0: 20-80 % time 181ps typ, 255ps min, 133ps max; typ from 1.95 V to 0 V
[POWER_clamp]
-3.3V     1.74A      1.237A     2.448A
-1.1V     168.3mA    166.5mA    176.4mA
-1.067V   146.5mA    151.3mA    145.6mA
-1V       104.2mA    121.4mA    87.66mA
-933.3mV  65.14mA    92.5mA     40.77mA
-900mV    47.68mA    78.57mA    26.13mA
-866.7mV  32.63mA    65.15mA    18.98mA
-800mV    13.66mA    40.44mA    14.14mA
-700mV    6.816mA    13.41mA    9.899mA
-633.3mV  4.976mA    5.618mA    7.281mA
-400mV    494.3uA    576.7uA    579.7uA
0V        107.9nA    188.2nA    173.9nA
[Pulldown]
-3.3V     -1.9mA     -1mA       -1.5mA
-2.1V     -5.25mA    -2.25mA    -15.4mA
-600mV    -18.98mA   -11.86mA   -28.78mA
1.1V      35.1mA     22.57mA    52.51mA
2.1V      52.53mA    33.6mA     77.59mA
2.8V      57.49mA    34.47mA    84.89mA
3.4V      58.09mA    33.87mA    85.51mA
4V        51.76mA    22.49mA    85.64mA
4.4V      38.36mA    14.02mA    73.32mA
4.6V      33.07mA    10.44mA    60.69mA
5.5V      12.69mA    3.91mA     29.56mA
6.6V      11.9mA     5.1mA      24.8mA
[Pullup]
-3.3V     10.6mA     4.9mA      17.3mA
-1.8V     12.27mA    7.15mA     16.12mA
-500mV    14.91mA    9.44mA     22.89mA
700mV     -22.26mA   -14.57mA   -33.75mA
1.4V      -39.99mA   -26.63mA   -58.35mA
2.7V      -58.85mA   -38.59mA   -89.65mA
3.4V      -63.54mA   -39.75mA   -95.63mA
3.8V      -63.67mA   -31.98mA   -97.01mA
4.3V      -49.05mA   -18.83mA   -91.49mA
5V        -25.38mA   -4.28mA    -55.95mA
5.5V      -14.03mA   -1.23mA    -36.13mA
6.6V      -2.9mA     -1mA       -10.3mA
[GND_clamp]
-3.3V     -1.738A    -1.232A    -2.455A
-1.1V     -156.2mA   -158mA     -162.2mA
-1.033V   -113.1mA   -127.6mA   -102.5mA
-966.7mV  -72.77mA   -98.11mA   -51.22mA
-900mV    -38.1mA    -70.06mA   -21.27mA
-833.3mV  -15.46mA   -44.45mA   -14.01mA
-766.7mV  -7.654mA   -23.26mA   -10.92mA
-700mV    -5.203mA   -9.589mA   -8.187mA
-633.3mV  -3.542mA   -3.899mA   -5.686mA
-566.7mV  -2.157mA   -1.848mA   -3.497mA
-300mV    -27.28uA   -33.59uA   -33.93uA
3.3V      107.9nA    175uA      154.3nA
[Ramp]
dV/dt_f   1.22556/0.33393264n   0.88242/0.62142633n   1.57572/0.22310901n
dV/dt_r  1.1677048/0.28114567n 0.84613104/0.52101682n  1.5085536/0.17869203n
R_load = 50
[Rising Waveform]
R_fixture = 50
V_fixture = 3.3
V_fixture_min = 2.97
V_fixture_max = 3.63
0s        1.305V     1.531V     1.061V
240ps     1.307V     1.533V     1.135V
308.7ps   1.306V     1.535V     1.643V
468.4ps   1.488V     1.535V     3.336V
564.7ps   2.14V      1.532V     3.601V
787.3ps   3.222V     1.529V     3.627V
897.3ps   3.285V     1.663V     3.629V
1.156ns   3.297V     2.628V     3.63V
1.397ns   3.3V       2.936V     3.63V
5ns       3.3V       2.97V      3.63V
[Rising Waveform]
R_fixture = 50
V_fixture = 0
V_fixture_min = 0
V_fixture_max = 0
171.7ps   0V         0V         0V
443.7ps   -5.378mV   0V         110.2mV
630.5ps   -3.964mV   0V         1.345V
719.7ps   64.03mV    0V         2.261V
812.9ps   338.2mV    0V         2.463V
1.031ns   1.108V     -4.402mV   2.494V
1.139ns   1.704V     -4.717mV   2.495V
1.275ns   1.895V     12.07mV    2.496V
2.2ns     1.929V     1.323V     2.496V
5.172ns   1.938V     1.405V     2.504V
[Falling Waveform]
R_fixture = 50
V_fixture = 3.3
V_fixture_min = 2.97
V_fixture_max = 3.63
0s        3.301V     2.971V     3.631V
348.2ps   3.299V     2.97V      3.628V
577.9ps   3.313V     2.97V      1.869V
733.3ps   2.769V     2.97V      1.224V
827ps     2.343V     2.976V     1.087V
1.067ns   1.622V     2.982V     1.053V
1.234ns   1.351V     2.856V     1.051V
1.49ns    1.301V     2.377V     1.05V
2.155ns   1.295V     1.597V     1.05V
5ns       1.299V     1.525V     1.058V
[Falling Waveform]
R_fixture = 50
V_fixture = 0
V_fixture_min = 0
V_fixture_max = 0
171.7ps   1.949V     1.431V     2.507V
255.1ps   1.95V      1.433V     2.389V
327.1ps   1.949V     1.433V     1.305V
421.5ps   1.919V     1.433V     444.1mV
538.7ps   937.3mV    1.432V     33.96mV
765.7ps   72.49mV    1.43V      4.349mV
862.2ps   21.21mV    1.33V      0V
1.02ns    7.306mV    556.5mV    0V
1.378ns   0V         35.88mV    0V
5.172ns   0V         0V         0V
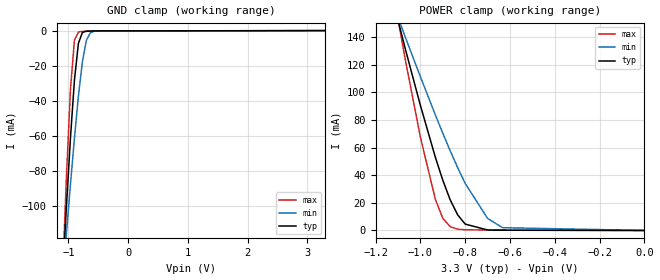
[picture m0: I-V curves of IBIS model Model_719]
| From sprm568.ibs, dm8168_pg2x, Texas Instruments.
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| Model based on original model for IQ33GHYPBFBP18
|   Sub model RX_MODE_3P3
[model]   Model_719
|[Description]  [3.3V-INPUT-PI-X]
|   Weak pull up/down disabled, ,
|[Input Load]   PI
|[Output Drive]
|Voltage   3.3V
|Mode   INPUT
Model_type   Input
Polarity   Non-Inverting
Vinl =  0.8V
Vinh =  2V
C_comp   1.04863p   0.982328p   1.12063p
[Model Spec]
Vinl   0.8V   0.8V   0.8V
Vinh   2V   2V   2V
[Temperature Range]   25   125   -40
[Voltage Range]   3.3   2.97   3.63
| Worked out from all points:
|   GND clamp passes 1 mA (typ) near -0.76 V on its own axis
|   POWER clamp passes 1 mA (typ) near -0.74 V on its own axis
[POWER_clamp]
-3.3V     1.674A     1.189A     2.355A
-1.1V     152mA      154.3mA    152.9mA
-1.067V   131.1mA    139.7mA    123.2mA
-1V       90.48mA    111.2mA    67.49mA
-933.3mV  53.02mA    83.6mA     22.58mA
-900mV    36.35mA    70.33mA    8.824mA
-866.7mV  22.08mA    57.53mA    2.728mA
-833.3mV  11.23mA    45.37mA    944.7uA
-800mV    4.624mA    34.04mA    523uA
-700mV    343.1uA    8.723mA    326.5uA
-633.3mV  187.3uA    2.024mA    259.4uA
0V        85.86nA    155.8nA    147.2nA
[GND_clamp]
-3.3V     -1.661A    -1.178A    -2.34A
-1.1V     -140.3mA   -143.8mA   -139.5mA
-1.033V   -99.32mA   -115.1mA   -82.3mA
-966.7mV  -61.02mA   -87.42mA   -33.31mA
-900mV    -28.15mA   -61.11mA   -5.397mA
-833.3mV  -7.169mA   -37.2mA    -767.6uA
-766.7mV  -1.07mA    -17.63mA   -462uA
-700mV    -329.5uA   -5.477mA   -380.7uA
-633.3mV  -224.3uA   -1.179mA   -309.8uA
-566.7mV  -172.3uA   -283.1uA   -241.3uA
3.3V      85.86nA    16.45uA    144.6nA
